VERSION 5.8 ;
BUSBITCHARS "[]" ;
DIVIDERCHAR "/" ;
UNITS
    DATABASE MICRONS 1000 ;
END UNITS

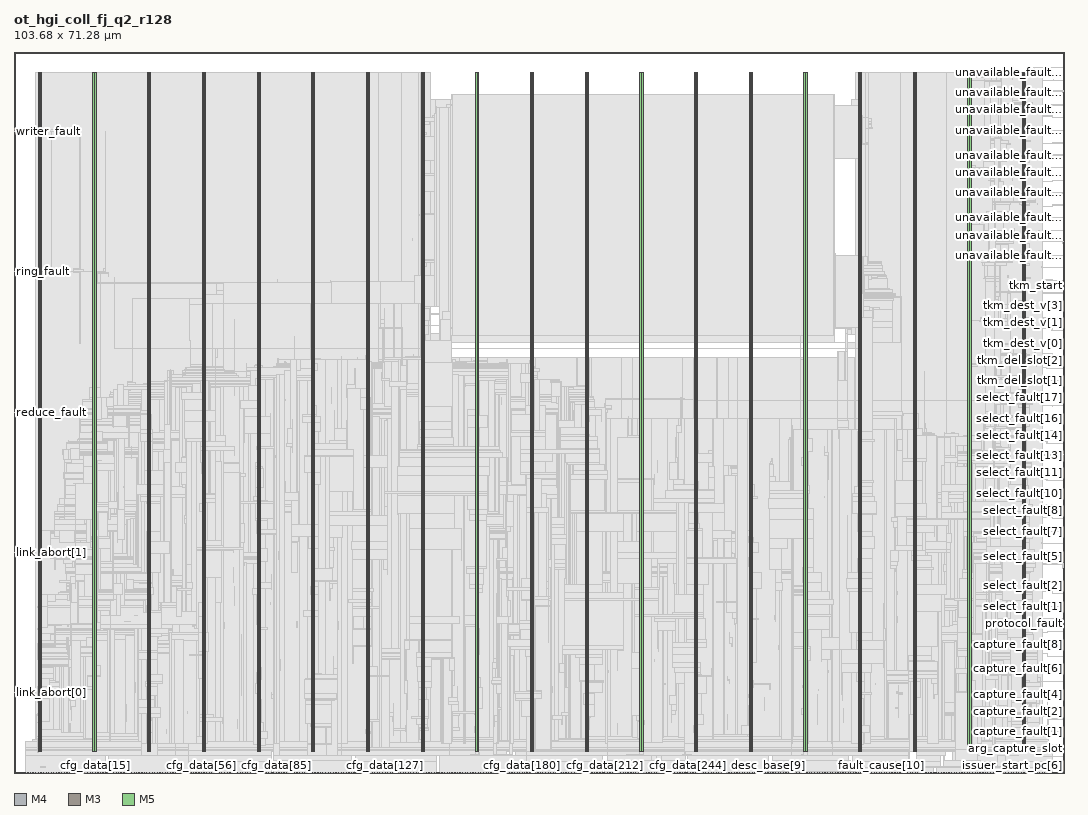
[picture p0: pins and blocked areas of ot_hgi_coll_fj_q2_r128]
MACRO ot_hgi_coll_fj_q2_r128
  FOREIGN ot_hgi_coll_fj_q2_r128 0 0 ;
  CLASS BLOCK ;
  SIZE 103.68 BY 71.28 ;
  PIN arg_capture_slot
    DIRECTION INPUT ;
    USE SIGNAL ;
    PORT
      LAYER M4 ;
        RECT  103.596 1.584 103.68 1.608 ;
    END
  END arg_capture_slot
  PIN capture_fault[0]
    DIRECTION INPUT ;
    USE SIGNAL ;
    PORT
      LAYER M4 ;
        RECT  103.596 2.832 103.68 2.856 ;
    END
  END capture_fault[0]
  PIN capture_fault[1]
    DIRECTION INPUT ;
    USE SIGNAL ;
    PORT
      LAYER M4 ;
        RECT  103.596 4.08 103.68 4.104 ;
    END
  END capture_fault[1]
  PIN capture_fault[2]
    DIRECTION INPUT ;
    USE SIGNAL ;
    PORT
      LAYER M4 ;
        RECT  103.596 5.328 103.68 5.352 ;
    END
  END capture_fault[2]
  PIN capture_fault[3]
    DIRECTION INPUT ;
    USE SIGNAL ;
    PORT
      LAYER M4 ;
        RECT  103.596 6.576 103.68 6.6 ;
    END
  END capture_fault[3]
  PIN capture_fault[4]
    DIRECTION INPUT ;
    USE SIGNAL ;
    PORT
      LAYER M4 ;
        RECT  103.596 7.776 103.68 7.8 ;
    END
  END capture_fault[4]
  PIN capture_fault[5]
    DIRECTION INPUT ;
    USE SIGNAL ;
    PORT
      LAYER M4 ;
        RECT  103.596 9.024 103.68 9.048 ;
    END
  END capture_fault[5]
  PIN capture_fault[6]
    DIRECTION INPUT ;
    USE SIGNAL ;
    PORT
      LAYER M4 ;
        RECT  103.596 10.272 103.68 10.296 ;
    END
  END capture_fault[6]
  PIN capture_fault[7]
    DIRECTION INPUT ;
    USE SIGNAL ;
    PORT
      LAYER M4 ;
        RECT  103.596 11.52 103.68 11.544 ;
    END
  END capture_fault[7]
  PIN capture_fault[8]
    DIRECTION INPUT ;
    USE SIGNAL ;
    PORT
      LAYER M4 ;
        RECT  103.596 12.72 103.68 12.744 ;
    END
  END capture_fault[8]
  PIN cfg_addr[0]
    DIRECTION INPUT ;
    USE SIGNAL ;
    PORT
      LAYER M3 ;
        RECT  1.116 0 1.134 0.038 ;
    END
  END cfg_addr[0]
  PIN cfg_addr[10]
    DIRECTION INPUT ;
    USE SIGNAL ;
    PORT
      LAYER M3 ;
        RECT  3.672 0 3.69 0.038 ;
    END
  END cfg_addr[10]
  PIN cfg_addr[11]
    DIRECTION INPUT ;
    USE SIGNAL ;
    PORT
      LAYER M3 ;
        RECT  3.924 0 3.942 0.038 ;
    END
  END cfg_addr[11]
  PIN cfg_addr[1]
    DIRECTION INPUT ;
    USE SIGNAL ;
    PORT
      LAYER M3 ;
        RECT  1.368 0 1.386 0.038 ;
    END
  END cfg_addr[1]
  PIN cfg_addr[2]
    DIRECTION INPUT ;
    USE SIGNAL ;
    PORT
      LAYER M3 ;
        RECT  1.62 0 1.638 0.038 ;
    END
  END cfg_addr[2]
  PIN cfg_addr[3]
    DIRECTION INPUT ;
    USE SIGNAL ;
    PORT
      LAYER M3 ;
        RECT  1.872 0 1.89 0.038 ;
    END
  END cfg_addr[3]
  PIN cfg_addr[4]
    DIRECTION INPUT ;
    USE SIGNAL ;
    PORT
      LAYER M3 ;
        RECT  2.124 0 2.142 0.038 ;
    END
  END cfg_addr[4]
  PIN cfg_addr[5]
    DIRECTION INPUT ;
    USE SIGNAL ;
    PORT
      LAYER M3 ;
        RECT  2.412 0 2.43 0.038 ;
    END
  END cfg_addr[5]
  PIN cfg_addr[6]
    DIRECTION INPUT ;
    USE SIGNAL ;
    PORT
      LAYER M3 ;
        RECT  2.664 0 2.682 0.038 ;
    END
  END cfg_addr[6]
  PIN cfg_addr[7]
    DIRECTION INPUT ;
    USE SIGNAL ;
    PORT
      LAYER M3 ;
        RECT  2.916 0 2.934 0.038 ;
    END
  END cfg_addr[7]
  PIN cfg_addr[8]
    DIRECTION INPUT ;
    USE SIGNAL ;
    PORT
      LAYER M3 ;
        RECT  3.168 0 3.186 0.038 ;
    END
  END cfg_addr[8]
  PIN cfg_addr[9]
    DIRECTION INPUT ;
    USE SIGNAL ;
    PORT
      LAYER M3 ;
        RECT  3.42 0 3.438 0.038 ;
    END
  END cfg_addr[9]
  PIN cfg_data[0]
    DIRECTION INPUT ;
    USE SIGNAL ;
    PORT
      LAYER M3 ;
        RECT  4.176 0 4.194 0.038 ;
    END
  END cfg_data[0]
  PIN cfg_data[100]
    DIRECTION INPUT ;
    USE SIGNAL ;
    PORT
      LAYER M5 ;
        RECT  29.712 0 29.736 0.084 ;
    END
  END cfg_data[100]
  PIN cfg_data[101]
    DIRECTION INPUT ;
    USE SIGNAL ;
    PORT
      LAYER M5 ;
        RECT  30 0 30.024 0.084 ;
    END
  END cfg_data[101]
  PIN cfg_data[102]
    DIRECTION INPUT ;
    USE SIGNAL ;
    PORT
      LAYER M5 ;
        RECT  30.24 0 30.264 0.084 ;
    END
  END cfg_data[102]
  PIN cfg_data[103]
    DIRECTION INPUT ;
    USE SIGNAL ;
    PORT
      LAYER M5 ;
        RECT  30.48 0 30.504 0.084 ;
    END
  END cfg_data[103]
  PIN cfg_data[104]
    DIRECTION INPUT ;
    USE SIGNAL ;
    PORT
      LAYER M5 ;
        RECT  30.768 0 30.792 0.084 ;
    END
  END cfg_data[104]
  PIN cfg_data[105]
    DIRECTION INPUT ;
    USE SIGNAL ;
    PORT
      LAYER M5 ;
        RECT  31.008 0 31.032 0.084 ;
    END
  END cfg_data[105]
  PIN cfg_data[106]
    DIRECTION INPUT ;
    USE SIGNAL ;
    PORT
      LAYER M5 ;
        RECT  31.248 0 31.272 0.084 ;
    END
  END cfg_data[106]
  PIN cfg_data[107]
    DIRECTION INPUT ;
    USE SIGNAL ;
    PORT
      LAYER M5 ;
        RECT  31.536 0 31.56 0.084 ;
    END
  END cfg_data[107]
  PIN cfg_data[108]
    DIRECTION INPUT ;
    USE SIGNAL ;
    PORT
      LAYER M5 ;
        RECT  31.776 0 31.8 0.084 ;
    END
  END cfg_data[108]
  PIN cfg_data[109]
    DIRECTION INPUT ;
    USE SIGNAL ;
    PORT
      LAYER M5 ;
        RECT  32.016 0 32.04 0.084 ;
    END
  END cfg_data[109]
  PIN cfg_data[10]
    DIRECTION INPUT ;
    USE SIGNAL ;
    PORT
      LAYER M3 ;
        RECT  6.732 0 6.75 0.038 ;
    END
  END cfg_data[10]
  PIN cfg_data[110]
    DIRECTION INPUT ;
    USE SIGNAL ;
    PORT
      LAYER M5 ;
        RECT  32.304 0 32.328 0.084 ;
    END
  END cfg_data[110]
  PIN cfg_data[111]
    DIRECTION INPUT ;
    USE SIGNAL ;
    PORT
      LAYER M5 ;
        RECT  32.544 0 32.568 0.084 ;
    END
  END cfg_data[111]
  PIN cfg_data[112]
    DIRECTION INPUT ;
    USE SIGNAL ;
    PORT
      LAYER M5 ;
        RECT  32.784 0 32.808 0.084 ;
    END
  END cfg_data[112]
  PIN cfg_data[113]
    DIRECTION INPUT ;
    USE SIGNAL ;
    PORT
      LAYER M5 ;
        RECT  33.072 0 33.096 0.084 ;
    END
  END cfg_data[113]
  PIN cfg_data[114]
    DIRECTION INPUT ;
    USE SIGNAL ;
    PORT
      LAYER M5 ;
        RECT  33.312 0 33.336 0.084 ;
    END
  END cfg_data[114]
  PIN cfg_data[115]
    DIRECTION INPUT ;
    USE SIGNAL ;
    PORT
      LAYER M5 ;
        RECT  33.552 0 33.576 0.084 ;
    END
  END cfg_data[115]
  PIN cfg_data[116]
    DIRECTION INPUT ;
    USE SIGNAL ;
    PORT
      LAYER M3 ;
        RECT  33.804 0 33.822 0.038 ;
    END
  END cfg_data[116]
  PIN cfg_data[117]
    DIRECTION INPUT ;
    USE SIGNAL ;
    PORT
      LAYER M3 ;
        RECT  34.092 0 34.11 0.038 ;
    END
  END cfg_data[117]
  PIN cfg_data[118]
    DIRECTION INPUT ;
    USE SIGNAL ;
    PORT
      LAYER M3 ;
        RECT  34.344 0 34.362 0.038 ;
    END
  END cfg_data[118]
  PIN cfg_data[119]
    DIRECTION INPUT ;
    USE SIGNAL ;
    PORT
      LAYER M3 ;
        RECT  34.596 0 34.614 0.038 ;
    END
  END cfg_data[119]
  PIN cfg_data[11]
    DIRECTION INPUT ;
    USE SIGNAL ;
    PORT
      LAYER M3 ;
        RECT  6.984 0 7.002 0.038 ;
    END
  END cfg_data[11]
  PIN cfg_data[120]
    DIRECTION INPUT ;
    USE SIGNAL ;
    PORT
      LAYER M3 ;
        RECT  34.848 0 34.866 0.038 ;
    END
  END cfg_data[120]
  PIN cfg_data[121]
    DIRECTION INPUT ;
    USE SIGNAL ;
    PORT
      LAYER M3 ;
        RECT  35.1 0 35.118 0.038 ;
    END
  END cfg_data[121]
  PIN cfg_data[122]
    DIRECTION INPUT ;
    USE SIGNAL ;
    PORT
      LAYER M3 ;
        RECT  35.352 0 35.37 0.038 ;
    END
  END cfg_data[122]
  PIN cfg_data[123]
    DIRECTION INPUT ;
    USE SIGNAL ;
    PORT
      LAYER M3 ;
        RECT  35.604 0 35.622 0.038 ;
    END
  END cfg_data[123]
  PIN cfg_data[124]
    DIRECTION INPUT ;
    USE SIGNAL ;
    PORT
      LAYER M3 ;
        RECT  35.856 0 35.874 0.038 ;
    END
  END cfg_data[124]
  PIN cfg_data[125]
    DIRECTION INPUT ;
    USE SIGNAL ;
    PORT
      LAYER M3 ;
        RECT  36.108 0 36.126 0.038 ;
    END
  END cfg_data[125]
  PIN cfg_data[126]
    DIRECTION INPUT ;
    USE SIGNAL ;
    PORT
      LAYER M3 ;
        RECT  36.36 0 36.378 0.038 ;
    END
  END cfg_data[126]
  PIN cfg_data[127]
    DIRECTION INPUT ;
    USE SIGNAL ;
    PORT
      LAYER M3 ;
        RECT  36.648 0 36.666 0.038 ;
    END
  END cfg_data[127]
  PIN cfg_data[128]
    DIRECTION INPUT ;
    USE SIGNAL ;
    PORT
      LAYER M3 ;
        RECT  36.9 0 36.918 0.038 ;
    END
  END cfg_data[128]
  PIN cfg_data[129]
    DIRECTION INPUT ;
    USE SIGNAL ;
    PORT
      LAYER M3 ;
        RECT  37.152 0 37.17 0.038 ;
    END
  END cfg_data[129]
  PIN cfg_data[12]
    DIRECTION INPUT ;
    USE SIGNAL ;
    PORT
      LAYER M3 ;
        RECT  7.236 0 7.254 0.038 ;
    END
  END cfg_data[12]
  PIN cfg_data[130]
    DIRECTION INPUT ;
    USE SIGNAL ;
    PORT
      LAYER M3 ;
        RECT  37.404 0 37.422 0.038 ;
    END
  END cfg_data[130]
  PIN cfg_data[131]
    DIRECTION INPUT ;
    USE SIGNAL ;
    PORT
      LAYER M3 ;
        RECT  37.656 0 37.674 0.038 ;
    END
  END cfg_data[131]
  PIN cfg_data[132]
    DIRECTION INPUT ;
    USE SIGNAL ;
    PORT
      LAYER M3 ;
        RECT  37.908 0 37.926 0.038 ;
    END
  END cfg_data[132]
  PIN cfg_data[133]
    DIRECTION INPUT ;
    USE SIGNAL ;
    PORT
      LAYER M3 ;
        RECT  38.16 0 38.178 0.038 ;
    END
  END cfg_data[133]
  PIN cfg_data[134]
    DIRECTION INPUT ;
    USE SIGNAL ;
    PORT
      LAYER M3 ;
        RECT  38.412 0 38.43 0.038 ;
    END
  END cfg_data[134]
  PIN cfg_data[135]
    DIRECTION INPUT ;
    USE SIGNAL ;
    PORT
      LAYER M3 ;
        RECT  38.664 0 38.682 0.038 ;
    END
  END cfg_data[135]
  PIN cfg_data[136]
    DIRECTION INPUT ;
    USE SIGNAL ;
    PORT
      LAYER M3 ;
        RECT  38.916 0 38.934 0.038 ;
    END
  END cfg_data[136]
  PIN cfg_data[137]
    DIRECTION INPUT ;
    USE SIGNAL ;
    PORT
      LAYER M3 ;
        RECT  39.168 0 39.186 0.038 ;
    END
  END cfg_data[137]
  PIN cfg_data[138]
    DIRECTION INPUT ;
    USE SIGNAL ;
    PORT
      LAYER M3 ;
        RECT  39.456 0 39.474 0.038 ;
    END
  END cfg_data[138]
  PIN cfg_data[139]
    DIRECTION INPUT ;
    USE SIGNAL ;
    PORT
      LAYER M3 ;
        RECT  39.708 0 39.726 0.038 ;
    END
  END cfg_data[139]
  PIN cfg_data[13]
    DIRECTION INPUT ;
    USE SIGNAL ;
    PORT
      LAYER M3 ;
        RECT  7.524 0 7.542 0.038 ;
    END
  END cfg_data[13]
  PIN cfg_data[140]
    DIRECTION INPUT ;
    USE SIGNAL ;
    PORT
      LAYER M3 ;
        RECT  39.96 0 39.978 0.038 ;
    END
  END cfg_data[140]
  PIN cfg_data[141]
    DIRECTION INPUT ;
    USE SIGNAL ;
    PORT
      LAYER M3 ;
        RECT  40.212 0 40.23 0.038 ;
    END
  END cfg_data[141]
  PIN cfg_data[142]
    DIRECTION INPUT ;
    USE SIGNAL ;
    PORT
      LAYER M3 ;
        RECT  40.464 0 40.482 0.038 ;
    END
  END cfg_data[142]
  PIN cfg_data[143]
    DIRECTION INPUT ;
    USE SIGNAL ;
    PORT
      LAYER M3 ;
        RECT  40.716 0 40.734 0.038 ;
    END
  END cfg_data[143]
  PIN cfg_data[144]
    DIRECTION INPUT ;
    USE SIGNAL ;
    PORT
      LAYER M3 ;
        RECT  40.968 0 40.986 0.038 ;
    END
  END cfg_data[144]
  PIN cfg_data[145]
    DIRECTION INPUT ;
    USE SIGNAL ;
    PORT
      LAYER M3 ;
        RECT  41.22 0 41.238 0.038 ;
    END
  END cfg_data[145]
  PIN cfg_data[146]
    DIRECTION INPUT ;
    USE SIGNAL ;
    PORT
      LAYER M3 ;
        RECT  41.472 0 41.49 0.038 ;
    END
  END cfg_data[146]
  PIN cfg_data[147]
    DIRECTION INPUT ;
    USE SIGNAL ;
    PORT
      LAYER M3 ;
        RECT  41.724 0 41.742 0.038 ;
    END
  END cfg_data[147]
  PIN cfg_data[148]
    DIRECTION INPUT ;
    USE SIGNAL ;
    PORT
      LAYER M5 ;
        RECT  42 0 42.024 0.084 ;
    END
  END cfg_data[148]
  PIN cfg_data[149]
    DIRECTION INPUT ;
    USE SIGNAL ;
    PORT
      LAYER M5 ;
        RECT  42.24 0 42.264 0.084 ;
    END
  END cfg_data[149]
  PIN cfg_data[14]
    DIRECTION INPUT ;
    USE SIGNAL ;
    PORT
      LAYER M3 ;
        RECT  7.776 0 7.794 0.038 ;
    END
  END cfg_data[14]
  PIN cfg_data[150]
    DIRECTION INPUT ;
    USE SIGNAL ;
    PORT
      LAYER M5 ;
        RECT  42.48 0 42.504 0.084 ;
    END
  END cfg_data[150]
  PIN cfg_data[151]
    DIRECTION INPUT ;
    USE SIGNAL ;
    PORT
      LAYER M5 ;
        RECT  42.768 0 42.792 0.084 ;
    END
  END cfg_data[151]
  PIN cfg_data[152]
    DIRECTION INPUT ;
    USE SIGNAL ;
    PORT
      LAYER M5 ;
        RECT  43.008 0 43.032 0.084 ;
    END
  END cfg_data[152]
  PIN cfg_data[153]
    DIRECTION INPUT ;
    USE SIGNAL ;
    PORT
      LAYER M5 ;
        RECT  43.248 0 43.272 0.084 ;
    END
  END cfg_data[153]
  PIN cfg_data[154]
    DIRECTION INPUT ;
    USE SIGNAL ;
    PORT
      LAYER M5 ;
        RECT  43.536 0 43.56 0.084 ;
    END
  END cfg_data[154]
  PIN cfg_data[155]
    DIRECTION INPUT ;
    USE SIGNAL ;
    PORT
      LAYER M5 ;
        RECT  43.776 0 43.8 0.084 ;
    END
  END cfg_data[155]
  PIN cfg_data[156]
    DIRECTION INPUT ;
    USE SIGNAL ;
    PORT
      LAYER M5 ;
        RECT  44.016 0 44.04 0.084 ;
    END
  END cfg_data[156]
  PIN cfg_data[157]
    DIRECTION INPUT ;
    USE SIGNAL ;
    PORT
      LAYER M5 ;
        RECT  44.304 0 44.328 0.084 ;
    END
  END cfg_data[157]
  PIN cfg_data[158]
    DIRECTION INPUT ;
    USE SIGNAL ;
    PORT
      LAYER M5 ;
        RECT  44.544 0 44.568 0.084 ;
    END
  END cfg_data[158]
  PIN cfg_data[159]
    DIRECTION INPUT ;
    USE SIGNAL ;
    PORT
      LAYER M5 ;
        RECT  44.784 0 44.808 0.084 ;
    END
  END cfg_data[159]
  PIN cfg_data[15]
    DIRECTION INPUT ;
    USE SIGNAL ;
    PORT
      LAYER M3 ;
        RECT  8.028 0 8.046 0.038 ;
    END
  END cfg_data[15]
  PIN cfg_data[160]
    DIRECTION INPUT ;
    USE SIGNAL ;
    PORT
      LAYER M5 ;
        RECT  45.072 0 45.096 0.084 ;
    END
  END cfg_data[160]
  PIN cfg_data[161]
    DIRECTION INPUT ;
    USE SIGNAL ;
    PORT
      LAYER M5 ;
        RECT  45.312 0 45.336 0.084 ;
    END
  END cfg_data[161]
  PIN cfg_data[162]
    DIRECTION INPUT ;
    USE SIGNAL ;
    PORT
      LAYER M5 ;
        RECT  45.552 0 45.576 0.084 ;
    END
  END cfg_data[162]
  PIN cfg_data[163]
    DIRECTION INPUT ;
    USE SIGNAL ;
    PORT
      LAYER M5 ;
        RECT  45.84 0 45.864 0.084 ;
    END
  END cfg_data[163]
  PIN cfg_data[164]
    DIRECTION INPUT ;
    USE SIGNAL ;
    PORT
      LAYER M5 ;
        RECT  46.08 0 46.104 0.084 ;
    END
  END cfg_data[164]
  PIN cfg_data[165]
    DIRECTION INPUT ;
    USE SIGNAL ;
    PORT
      LAYER M5 ;
        RECT  46.32 0 46.344 0.084 ;
    END
  END cfg_data[165]
  PIN cfg_data[166]
    DIRECTION INPUT ;
    USE SIGNAL ;
    PORT
      LAYER M5 ;
        RECT  46.608 0 46.632 0.084 ;
    END
  END cfg_data[166]
  PIN cfg_data[167]
    DIRECTION INPUT ;
    USE SIGNAL ;
    PORT
      LAYER M5 ;
        RECT  46.848 0 46.872 0.084 ;
    END
  END cfg_data[167]
  PIN cfg_data[168]
    DIRECTION INPUT ;
    USE SIGNAL ;
    PORT
      LAYER M5 ;
        RECT  47.088 0 47.112 0.084 ;
    END
  END cfg_data[168]
  PIN cfg_data[169]
    DIRECTION INPUT ;
    USE SIGNAL ;
    PORT
      LAYER M5 ;
        RECT  47.376 0 47.4 0.084 ;
    END
  END cfg_data[169]
  PIN cfg_data[16]
    DIRECTION INPUT ;
    USE SIGNAL ;
    PORT
      LAYER M3 ;
        RECT  8.28 0 8.298 0.038 ;
    END
  END cfg_data[16]
  PIN cfg_data[170]
    DIRECTION INPUT ;
    USE SIGNAL ;
    PORT
      LAYER M5 ;
        RECT  47.616 0 47.64 0.084 ;
    END
  END cfg_data[170]
  PIN cfg_data[171]
    DIRECTION INPUT ;
    USE SIGNAL ;
    PORT
      LAYER M5 ;
        RECT  47.856 0 47.88 0.084 ;
    END
  END cfg_data[171]
  PIN cfg_data[172]
    DIRECTION INPUT ;
    USE SIGNAL ;
    PORT
      LAYER M5 ;
        RECT  48.144 0 48.168 0.084 ;
    END
  END cfg_data[172]
  PIN cfg_data[173]
    DIRECTION INPUT ;
    USE SIGNAL ;
    PORT
      LAYER M5 ;
        RECT  48.384 0 48.408 0.084 ;
    END
  END cfg_data[173]
  PIN cfg_data[174]
    DIRECTION INPUT ;
    USE SIGNAL ;
    PORT
      LAYER M5 ;
        RECT  48.624 0 48.648 0.084 ;
    END
  END cfg_data[174]
  PIN cfg_data[175]
    DIRECTION INPUT ;
    USE SIGNAL ;
    PORT
      LAYER M5 ;
        RECT  48.912 0 48.936 0.084 ;
    END
  END cfg_data[175]
  PIN cfg_data[176]
    DIRECTION INPUT ;
    USE SIGNAL ;
    PORT
      LAYER M5 ;
        RECT  49.152 0 49.176 0.084 ;
    END
  END cfg_data[176]
  PIN cfg_data[177]
    DIRECTION INPUT ;
    USE SIGNAL ;
    PORT
      LAYER M5 ;
        RECT  49.392 0 49.416 0.084 ;
    END
  END cfg_data[177]
  PIN cfg_data[178]
    DIRECTION INPUT ;
    USE SIGNAL ;
    PORT
      LAYER M5 ;
        RECT  49.68 0 49.704 0.084 ;
    END
  END cfg_data[178]
  PIN cfg_data[179]
    DIRECTION INPUT ;
    USE SIGNAL ;
    PORT
      LAYER M5 ;
        RECT  49.92 0 49.944 0.084 ;
    END
  END cfg_data[179]
  PIN cfg_data[17]
    DIRECTION INPUT ;
    USE SIGNAL ;
    PORT
      LAYER M3 ;
        RECT  8.532 0 8.55 0.038 ;
    END
  END cfg_data[17]
  PIN cfg_data[180]
    DIRECTION INPUT ;
    USE SIGNAL ;
    PORT
      LAYER M3 ;
        RECT  50.184 0 50.202 0.038 ;
    END
  END cfg_data[180]
  PIN cfg_data[181]
    DIRECTION INPUT ;
    USE SIGNAL ;
    PORT
      LAYER M3 ;
        RECT  50.436 0 50.454 0.038 ;
    END
  END cfg_data[181]
  PIN cfg_data[182]
    DIRECTION INPUT ;
    USE SIGNAL ;
    PORT
      LAYER M3 ;
        RECT  50.688 0 50.706 0.038 ;
    END
  END cfg_data[182]
  PIN cfg_data[183]
    DIRECTION INPUT ;
    USE SIGNAL ;
    PORT
      LAYER M3 ;
        RECT  50.94 0 50.958 0.038 ;
    END
  END cfg_data[183]
  PIN cfg_data[184]
    DIRECTION INPUT ;
    USE SIGNAL ;
    PORT
      LAYER M3 ;
        RECT  51.192 0 51.21 0.038 ;
    END
  END cfg_data[184]
  PIN cfg_data[185]
    DIRECTION INPUT ;
    USE SIGNAL ;
    PORT
      LAYER M3 ;
        RECT  51.444 0 51.462 0.038 ;
    END
  END cfg_data[185]
  PIN cfg_data[186]
    DIRECTION INPUT ;
    USE SIGNAL ;
    PORT
      LAYER M3 ;
        RECT  51.696 0 51.714 0.038 ;
    END
  END cfg_data[186]
  PIN cfg_data[187]
    DIRECTION INPUT ;
    USE SIGNAL ;
    PORT
      LAYER M3 ;
        RECT  51.948 0 51.966 0.038 ;
    END
  END cfg_data[187]
  PIN cfg_data[188]
    DIRECTION INPUT ;
    USE SIGNAL ;
    PORT
      LAYER M3 ;
        RECT  52.2 0 52.218 0.038 ;
    END
  END cfg_data[188]
  PIN cfg_data[189]
    DIRECTION INPUT ;
    USE SIGNAL ;
    PORT
      LAYER M3 ;
        RECT  52.488 0 52.506 0.038 ;
    END
  END cfg_data[189]
  PIN cfg_data[18]
    DIRECTION INPUT ;
    USE SIGNAL ;
    PORT
      LAYER M3 ;
        RECT  8.784 0 8.802 0.038 ;
    END
  END cfg_data[18]
  PIN cfg_data[190]
    DIRECTION INPUT ;
    USE SIGNAL ;
    PORT
      LAYER M3 ;
        RECT  52.74 0 52.758 0.038 ;
    END
  END cfg_data[190]
  PIN cfg_data[191]
    DIRECTION INPUT ;
    USE SIGNAL ;
    PORT
      LAYER M3 ;
        RECT  52.992 0 53.01 0.038 ;
    END
  END cfg_data[191]
  PIN cfg_data[192]
    DIRECTION INPUT ;
    USE SIGNAL ;
    PORT
      LAYER M3 ;
        RECT  53.244 0 53.262 0.038 ;
    END
  END cfg_data[192]
  PIN cfg_data[193]
    DIRECTION INPUT ;
    USE SIGNAL ;
    PORT
      LAYER M3 ;
        RECT  53.496 0 53.514 0.038 ;
    END
  END cfg_data[193]
  PIN cfg_data[194]
    DIRECTION INPUT ;
    USE SIGNAL ;
    PORT
      LAYER M3 ;
        RECT  53.748 0 53.766 0.038 ;
    END
  END cfg_data[194]
  PIN cfg_data[195]
    DIRECTION INPUT ;
    USE SIGNAL ;
    PORT
      LAYER M3 ;
        RECT  54 0 54.018 0.038 ;
    END
  END cfg_data[195]
  PIN cfg_data[196]
    DIRECTION INPUT ;
    USE SIGNAL ;
    PORT
      LAYER M3 ;
        RECT  54.252 0 54.27 0.038 ;
    END
  END cfg_data[196]
  PIN cfg_data[197]
    DIRECTION INPUT ;
    USE SIGNAL ;
    PORT
      LAYER M3 ;
        RECT  54.504 0 54.522 0.038 ;
    END
  END cfg_data[197]
  PIN cfg_data[198]
    DIRECTION INPUT ;
    USE SIGNAL ;
    PORT
      LAYER M3 ;
        RECT  54.756 0 54.774 0.038 ;
    END
  END cfg_data[198]
  PIN cfg_data[199]
    DIRECTION INPUT ;
    USE SIGNAL ;
    PORT
      LAYER M3 ;
        RECT  55.008 0 55.026 0.038 ;
    END
  END cfg_data[199]
  PIN cfg_data[19]
    DIRECTION INPUT ;
    USE SIGNAL ;
    PORT
      LAYER M3 ;
        RECT  9.036 0 9.054 0.038 ;
    END
  END cfg_data[19]
  PIN cfg_data[1]
    DIRECTION INPUT ;
    USE SIGNAL ;
    PORT
      LAYER M3 ;
        RECT  4.428 0 4.446 0.038 ;
    END
  END cfg_data[1]
  PIN cfg_data[200]
    DIRECTION INPUT ;
    USE SIGNAL ;
    PORT
      LAYER M3 ;
        RECT  55.296 0 55.314 0.038 ;
    END
  END cfg_data[200]
  PIN cfg_data[201]
    DIRECTION INPUT ;
    USE SIGNAL ;
    PORT
      LAYER M3 ;
        RECT  55.548 0 55.566 0.038 ;
    END
  END cfg_data[201]
  PIN cfg_data[202]
    DIRECTION INPUT ;
    USE SIGNAL ;
    PORT
      LAYER M3 ;
        RECT  55.8 0 55.818 0.038 ;
    END
  END cfg_data[202]
  PIN cfg_data[203]
    DIRECTION INPUT ;
    USE SIGNAL ;
    PORT
      LAYER M3 ;
        RECT  56.052 0 56.07 0.038 ;
    END
  END cfg_data[203]
  PIN cfg_data[204]
    DIRECTION INPUT ;
    USE SIGNAL ;
    PORT
      LAYER M3 ;
        RECT  56.304 0 56.322 0.038 ;
    END
  END cfg_data[204]
  PIN cfg_data[205]
    DIRECTION INPUT ;
    USE SIGNAL ;
    PORT
      LAYER M3 ;
        RECT  56.556 0 56.574 0.038 ;
    END
  END cfg_data[205]
  PIN cfg_data[206]
    DIRECTION INPUT ;
    USE SIGNAL ;
    PORT
      LAYER M3 ;
        RECT  56.808 0 56.826 0.038 ;
    END
  END cfg_data[206]
  PIN cfg_data[207]
    DIRECTION INPUT ;
    USE SIGNAL ;
    PORT
      LAYER M3 ;
        RECT  57.06 0 57.078 0.038 ;
    END
  END cfg_data[207]
  PIN cfg_data[208]
    DIRECTION INPUT ;
    USE SIGNAL ;
    PORT
      LAYER M3 ;
        RECT  57.312 0 57.33 0.038 ;
    END
  END cfg_data[208]
  PIN cfg_data[209]
    DIRECTION INPUT ;
    USE SIGNAL ;
    PORT
      LAYER M3 ;
        RECT  57.564 0 57.582 0.038 ;
    END
  END cfg_data[209]
  PIN cfg_data[20]
    DIRECTION INPUT ;
    USE SIGNAL ;
    PORT
      LAYER M5 ;
        RECT  9.312 0 9.336 0.084 ;
    END
  END cfg_data[20]
  PIN cfg_data[210]
    DIRECTION INPUT ;
    USE SIGNAL ;
    PORT
      LAYER M3 ;
        RECT  57.852 0 57.87 0.038 ;
    END
  END cfg_data[210]
  PIN cfg_data[211]
    DIRECTION INPUT ;
    USE SIGNAL ;
    PORT
      LAYER M3 ;
        RECT  58.104 0 58.122 0.038 ;
    END
  END cfg_data[211]
  PIN cfg_data[212]
    DIRECTION INPUT ;
    USE SIGNAL ;
    PORT
      LAYER M5 ;
        RECT  58.32 0 58.344 0.084 ;
    END
  END cfg_data[212]
  PIN cfg_data[213]
    DIRECTION INPUT ;
    USE SIGNAL ;
    PORT
      LAYER M5 ;
        RECT  58.608 0 58.632 0.084 ;
    END
  END cfg_data[213]
  PIN cfg_data[214]
    DIRECTION INPUT ;
    USE SIGNAL ;
    PORT
      LAYER M5 ;
        RECT  58.848 0 58.872 0.084 ;
    END
  END cfg_data[214]
  PIN cfg_data[215]
    DIRECTION INPUT ;
    USE SIGNAL ;
    PORT
      LAYER M5 ;
        RECT  59.088 0 59.112 0.084 ;
    END
  END cfg_data[215]
  PIN cfg_data[216]
    DIRECTION INPUT ;
    USE SIGNAL ;
    PORT
      LAYER M5 ;
        RECT  59.376 0 59.4 0.084 ;
    END
  END cfg_data[216]
  PIN cfg_data[217]
    DIRECTION INPUT ;
    USE SIGNAL ;
    PORT
      LAYER M5 ;
        RECT  59.616 0 59.64 0.084 ;
    END
  END cfg_data[217]
  PIN cfg_data[218]
    DIRECTION INPUT ;
    USE SIGNAL ;
    PORT
      LAYER M5 ;
        RECT  59.856 0 59.88 0.084 ;
    END
  END cfg_data[218]
  PIN cfg_data[219]
    DIRECTION INPUT ;
    USE SIGNAL ;
    PORT
      LAYER M5 ;
        RECT  60.144 0 60.168 0.084 ;
    END
  END cfg_data[219]
  PIN cfg_data[21]
    DIRECTION INPUT ;
    USE SIGNAL ;
    PORT
      LAYER M5 ;
        RECT  9.552 0 9.576 0.084 ;
    END
  END cfg_data[21]
  PIN cfg_data[220]
    DIRECTION INPUT ;
    USE SIGNAL ;
    PORT
      LAYER M5 ;
        RECT  60.384 0 60.408 0.084 ;
    END
  END cfg_data[220]
  PIN cfg_data[221]
    DIRECTION INPUT ;
    USE SIGNAL ;
    PORT
      LAYER M5 ;
        RECT  60.624 0 60.648 0.084 ;
    END
  END cfg_data[221]
  PIN cfg_data[222]
    DIRECTION INPUT ;
    USE SIGNAL ;
    PORT
      LAYER M5 ;
        RECT  60.912 0 60.936 0.084 ;
    END
  END cfg_data[222]
  PIN cfg_data[223]
    DIRECTION INPUT ;
    USE SIGNAL ;
    PORT
      LAYER M5 ;
        RECT  61.152 0 61.176 0.084 ;
    END
  END cfg_data[223]
  PIN cfg_data[224]
    DIRECTION INPUT ;
    USE SIGNAL ;
    PORT
      LAYER M5 ;
        RECT  61.392 0 61.416 0.084 ;
    END
  END cfg_data[224]
  PIN cfg_data[225]
    DIRECTION INPUT ;
    USE SIGNAL ;
    PORT
      LAYER M5 ;
        RECT  61.68 0 61.704 0.084 ;
    END
  END cfg_data[225]
  PIN cfg_data[226]
    DIRECTION INPUT ;
    USE SIGNAL ;
    PORT
      LAYER M5 ;
        RECT  61.92 0 61.944 0.084 ;
    END
  END cfg_data[226]
  PIN cfg_data[227]
    DIRECTION INPUT ;
    USE SIGNAL ;
    PORT
      LAYER M5 ;
        RECT  62.16 0 62.184 0.084 ;
    END
  END cfg_data[227]
  PIN cfg_data[228]
    DIRECTION INPUT ;
    USE SIGNAL ;
    PORT
      LAYER M5 ;
        RECT  62.448 0 62.472 0.084 ;
    END
  END cfg_data[228]
  PIN cfg_data[229]
    DIRECTION INPUT ;
    USE SIGNAL ;
    PORT
      LAYER M5 ;
        RECT  62.688 0 62.712 0.084 ;
    END
  END cfg_data[229]
  PIN cfg_data[22]
    DIRECTION INPUT ;
    USE SIGNAL ;
    PORT
      LAYER M5 ;
        RECT  9.792 0 9.816 0.084 ;
    END
  END cfg_data[22]
  PIN cfg_data[230]
    DIRECTION INPUT ;
    USE SIGNAL ;
    PORT
      LAYER M5 ;
        RECT  62.928 0 62.952 0.084 ;
    END
  END cfg_data[230]
  PIN cfg_data[231]
    DIRECTION INPUT ;
    USE SIGNAL ;
    PORT
      LAYER M5 ;
        RECT  63.216 0 63.24 0.084 ;
    END
  END cfg_data[231]
  PIN cfg_data[232]
    DIRECTION INPUT ;
    USE SIGNAL ;
    PORT
      LAYER M5 ;
        RECT  63.456 0 63.48 0.084 ;
    END
  END cfg_data[232]
  PIN cfg_data[233]
    DIRECTION INPUT ;
    USE SIGNAL ;
    PORT
      LAYER M5 ;
        RECT  63.696 0 63.72 0.084 ;
    END
  END cfg_data[233]
  PIN cfg_data[234]
    DIRECTION INPUT ;
    USE SIGNAL ;
    PORT
      LAYER M5 ;
        RECT  63.984 0 64.008 0.084 ;
    END
  END cfg_data[234]
  PIN cfg_data[235]
    DIRECTION INPUT ;
    USE SIGNAL ;
    PORT
      LAYER M5 ;
        RECT  64.224 0 64.248 0.084 ;
    END
  END cfg_data[235]
  PIN cfg_data[236]
    DIRECTION INPUT ;
    USE SIGNAL ;
    PORT
      LAYER M5 ;
        RECT  64.464 0 64.488 0.084 ;
    END
  END cfg_data[236]
  PIN cfg_data[237]
    DIRECTION INPUT ;
    USE SIGNAL ;
    PORT
      LAYER M5 ;
        RECT  64.752 0 64.776 0.084 ;
    END
  END cfg_data[237]
  PIN cfg_data[238]
    DIRECTION INPUT ;
    USE SIGNAL ;
    PORT
      LAYER M5 ;
        RECT  64.992 0 65.016 0.084 ;
    END
  END cfg_data[238]
  PIN cfg_data[239]
    DIRECTION INPUT ;
    USE SIGNAL ;
    PORT
      LAYER M5 ;
        RECT  65.232 0 65.256 0.084 ;
    END
  END cfg_data[239]
  PIN cfg_data[23]
    DIRECTION INPUT ;
    USE SIGNAL ;
    PORT
      LAYER M5 ;
        RECT  10.08 0 10.104 0.084 ;
    END
  END cfg_data[23]
  PIN cfg_data[240]
    DIRECTION INPUT ;
    USE SIGNAL ;
    PORT
      LAYER M5 ;
        RECT  65.52 0 65.544 0.084 ;
    END
  END cfg_data[240]
  PIN cfg_data[241]
    DIRECTION INPUT ;
    USE SIGNAL ;
    PORT
      LAYER M5 ;
        RECT  65.76 0 65.784 0.084 ;
    END
  END cfg_data[241]
  PIN cfg_data[242]
    DIRECTION INPUT ;
    USE SIGNAL ;
    PORT
      LAYER M5 ;
        RECT  66 0 66.024 0.084 ;
    END
  END cfg_data[242]
  PIN cfg_data[243]
    DIRECTION INPUT ;
    USE SIGNAL ;
    PORT
      LAYER M5 ;
        RECT  66.24 0 66.264 0.084 ;
    END
  END cfg_data[243]
  PIN cfg_data[244]
    DIRECTION INPUT ;
    USE SIGNAL ;
    PORT
      LAYER M3 ;
        RECT  66.528 0 66.546 0.038 ;
    END
  END cfg_data[244]
  PIN cfg_data[245]
    DIRECTION INPUT ;
    USE SIGNAL ;
    PORT
      LAYER M3 ;
        RECT  66.78 0 66.798 0.038 ;
    END
  END cfg_data[245]
  PIN cfg_data[246]
    DIRECTION INPUT ;
    USE SIGNAL ;
    PORT
      LAYER M3 ;
        RECT  67.032 0 67.05 0.038 ;
    END
  END cfg_data[246]
  PIN cfg_data[247]
    DIRECTION INPUT ;
    USE SIGNAL ;
    PORT
      LAYER M3 ;
        RECT  67.284 0 67.302 0.038 ;
    END
  END cfg_data[247]
  PIN cfg_data[248]
    DIRECTION INPUT ;
    USE SIGNAL ;
    PORT
      LAYER M3 ;
        RECT  67.536 0 67.554 0.038 ;
    END
  END cfg_data[248]
  PIN cfg_data[249]
    DIRECTION INPUT ;
    USE SIGNAL ;
    PORT
      LAYER M3 ;
        RECT  67.788 0 67.806 0.038 ;
    END
  END cfg_data[249]
  PIN cfg_data[24]
    DIRECTION INPUT ;
    USE SIGNAL ;
    PORT
      LAYER M5 ;
        RECT  10.32 0 10.344 0.084 ;
    END
  END cfg_data[24]
  PIN cfg_data[250]
    DIRECTION INPUT ;
    USE SIGNAL ;
    PORT
      LAYER M3 ;
        RECT  68.04 0 68.058 0.038 ;
    END
  END cfg_data[250]
  PIN cfg_data[251]
    DIRECTION INPUT ;
    USE SIGNAL ;
    PORT
      LAYER M3 ;
        RECT  68.292 0 68.31 0.038 ;
    END
  END cfg_data[251]
  PIN cfg_data[252]
    DIRECTION INPUT ;
    USE SIGNAL ;
    PORT
      LAYER M3 ;
        RECT  68.58 0 68.598 0.038 ;
    END
  END cfg_data[252]
  PIN cfg_data[253]
    DIRECTION INPUT ;
    USE SIGNAL ;
    PORT
      LAYER M3 ;
        RECT  68.832 0 68.85 0.038 ;
    END
  END cfg_data[253]
  PIN cfg_data[254]
    DIRECTION INPUT ;
    USE SIGNAL ;
    PORT
      LAYER M3 ;
        RECT  69.084 0 69.102 0.038 ;
    END
  END cfg_data[254]
  PIN cfg_data[255]
    DIRECTION INPUT ;
    USE SIGNAL ;
    PORT
      LAYER M3 ;
        RECT  69.336 0 69.354 0.038 ;
    END
  END cfg_data[255]
  PIN cfg_data[25]
    DIRECTION INPUT ;
    USE SIGNAL ;
    PORT
      LAYER M5 ;
        RECT  10.56 0 10.584 0.084 ;
    END
  END cfg_data[25]
  PIN cfg_data[26]
    DIRECTION INPUT ;
    USE SIGNAL ;
    PORT
      LAYER M5 ;
        RECT  10.848 0 10.872 0.084 ;
    END
  END cfg_data[26]
  PIN cfg_data[27]
    DIRECTION INPUT ;
    USE SIGNAL ;
    PORT
      LAYER M5 ;
        RECT  11.088 0 11.112 0.084 ;
    END
  END cfg_data[27]
  PIN cfg_data[28]
    DIRECTION INPUT ;
    USE SIGNAL ;
    PORT
      LAYER M5 ;
        RECT  11.328 0 11.352 0.084 ;
    END
  END cfg_data[28]
  PIN cfg_data[29]
    DIRECTION INPUT ;
    USE SIGNAL ;
    PORT
      LAYER M5 ;
        RECT  11.568 0 11.592 0.084 ;
    END
  END cfg_data[29]
  PIN cfg_data[2]
    DIRECTION INPUT ;
    USE SIGNAL ;
    PORT
      LAYER M3 ;
        RECT  4.68 0 4.698 0.038 ;
    END
  END cfg_data[2]
  PIN cfg_data[30]
    DIRECTION INPUT ;
    USE SIGNAL ;
    PORT
      LAYER M5 ;
        RECT  11.856 0 11.88 0.084 ;
    END
  END cfg_data[30]
  PIN cfg_data[31]
    DIRECTION INPUT ;
    USE SIGNAL ;
    PORT
      LAYER M5 ;
        RECT  12.096 0 12.12 0.084 ;
    END
  END cfg_data[31]
  PIN cfg_data[32]
    DIRECTION INPUT ;
    USE SIGNAL ;
    PORT
      LAYER M5 ;
        RECT  12.336 0 12.36 0.084 ;
    END
  END cfg_data[32]
  PIN cfg_data[33]
    DIRECTION INPUT ;
    USE SIGNAL ;
    PORT
      LAYER M5 ;
        RECT  12.624 0 12.648 0.084 ;
    END
  END cfg_data[33]
  PIN cfg_data[34]
    DIRECTION INPUT ;
    USE SIGNAL ;
    PORT
      LAYER M5 ;
        RECT  12.864 0 12.888 0.084 ;
    END
  END cfg_data[34]
  PIN cfg_data[35]
    DIRECTION INPUT ;
    USE SIGNAL ;
    PORT
      LAYER M5 ;
        RECT  13.104 0 13.128 0.084 ;
    END
  END cfg_data[35]
  PIN cfg_data[36]
    DIRECTION INPUT ;
    USE SIGNAL ;
    PORT
      LAYER M5 ;
        RECT  13.392 0 13.416 0.084 ;
    END
  END cfg_data[36]
  PIN cfg_data[37]
    DIRECTION INPUT ;
    USE SIGNAL ;
    PORT
      LAYER M5 ;
        RECT  13.632 0 13.656 0.084 ;
    END
  END cfg_data[37]
  PIN cfg_data[38]
    DIRECTION INPUT ;
    USE SIGNAL ;
    PORT
      LAYER M5 ;
        RECT  13.872 0 13.896 0.084 ;
    END
  END cfg_data[38]
  PIN cfg_data[39]
    DIRECTION INPUT ;
    USE SIGNAL ;
    PORT
      LAYER M5 ;
        RECT  14.16 0 14.184 0.084 ;
    END
  END cfg_data[39]
  PIN cfg_data[3]
    DIRECTION INPUT ;
    USE SIGNAL ;
    PORT
      LAYER M3 ;
        RECT  4.968 0 4.986 0.038 ;
    END
  END cfg_data[3]
  PIN cfg_data[40]
    DIRECTION INPUT ;
    USE SIGNAL ;
    PORT
      LAYER M5 ;
        RECT  14.4 0 14.424 0.084 ;
    END
  END cfg_data[40]
  PIN cfg_data[41]
    DIRECTION INPUT ;
    USE SIGNAL ;
    PORT
      LAYER M5 ;
        RECT  14.64 0 14.664 0.084 ;
    END
  END cfg_data[41]
  PIN cfg_data[42]
    DIRECTION INPUT ;
    USE SIGNAL ;
    PORT
      LAYER M5 ;
        RECT  14.928 0 14.952 0.084 ;
    END
  END cfg_data[42]
  PIN cfg_data[43]
    DIRECTION INPUT ;
    USE SIGNAL ;
    PORT
      LAYER M5 ;
        RECT  15.168 0 15.192 0.084 ;
    END
  END cfg_data[43]
  PIN cfg_data[44]
    DIRECTION INPUT ;
    USE SIGNAL ;
    PORT
      LAYER M5 ;
        RECT  15.408 0 15.432 0.084 ;
    END
  END cfg_data[44]
  PIN cfg_data[45]
    DIRECTION INPUT ;
    USE SIGNAL ;
    PORT
      LAYER M5 ;
        RECT  15.696 0 15.72 0.084 ;
    END
  END cfg_data[45]
  PIN cfg_data[46]
    DIRECTION INPUT ;
    USE SIGNAL ;
    PORT
      LAYER M5 ;
        RECT  15.936 0 15.96 0.084 ;
    END
  END cfg_data[46]
  PIN cfg_data[47]
    DIRECTION INPUT ;
    USE SIGNAL ;
    PORT
      LAYER M5 ;
        RECT  16.176 0 16.2 0.084 ;
    END
  END cfg_data[47]
  PIN cfg_data[48]
    DIRECTION INPUT ;
    USE SIGNAL ;
    PORT
      LAYER M5 ;
        RECT  16.464 0 16.488 0.084 ;
    END
  END cfg_data[48]
  PIN cfg_data[49]
    DIRECTION INPUT ;
    USE SIGNAL ;
    PORT
      LAYER M5 ;
        RECT  16.704 0 16.728 0.084 ;
    END
  END cfg_data[49]
  PIN cfg_data[4]
    DIRECTION INPUT ;
    USE SIGNAL ;
    PORT
      LAYER M3 ;
        RECT  5.22 0 5.238 0.038 ;
    END
  END cfg_data[4]
  PIN cfg_data[50]
    DIRECTION INPUT ;
    USE SIGNAL ;
    PORT
      LAYER M5 ;
        RECT  16.944 0 16.968 0.084 ;
    END
  END cfg_data[50]
  PIN cfg_data[51]
    DIRECTION INPUT ;
    USE SIGNAL ;
    PORT
      LAYER M5 ;
        RECT  17.232 0 17.256 0.084 ;
    END
  END cfg_data[51]
  PIN cfg_data[52]
    DIRECTION INPUT ;
    USE SIGNAL ;
    PORT
      LAYER M3 ;
        RECT  17.46 0 17.478 0.038 ;
    END
  END cfg_data[52]
  PIN cfg_data[53]
    DIRECTION INPUT ;
    USE SIGNAL ;
    PORT
      LAYER M3 ;
        RECT  17.712 0 17.73 0.038 ;
    END
  END cfg_data[53]
  PIN cfg_data[54]
    DIRECTION INPUT ;
    USE SIGNAL ;
    PORT
      LAYER M3 ;
        RECT  17.964 0 17.982 0.038 ;
    END
  END cfg_data[54]
  PIN cfg_data[55]
    DIRECTION INPUT ;
    USE SIGNAL ;
    PORT
      LAYER M3 ;
        RECT  18.252 0 18.27 0.038 ;
    END
  END cfg_data[55]
  PIN cfg_data[56]
    DIRECTION INPUT ;
    USE SIGNAL ;
    PORT
      LAYER M3 ;
        RECT  18.504 0 18.522 0.038 ;
    END
  END cfg_data[56]
  PIN cfg_data[57]
    DIRECTION INPUT ;
    USE SIGNAL ;
    PORT
      LAYER M3 ;
        RECT  18.756 0 18.774 0.038 ;
    END
  END cfg_data[57]
  PIN cfg_data[58]
    DIRECTION INPUT ;
    USE SIGNAL ;
    PORT
      LAYER M3 ;
        RECT  19.008 0 19.026 0.038 ;
    END
  END cfg_data[58]
  PIN cfg_data[59]
    DIRECTION INPUT ;
    USE SIGNAL ;
    PORT
      LAYER M3 ;
        RECT  19.26 0 19.278 0.038 ;
    END
  END cfg_data[59]
  PIN cfg_data[5]
    DIRECTION INPUT ;
    USE SIGNAL ;
    PORT
      LAYER M3 ;
        RECT  5.472 0 5.49 0.038 ;
    END
  END cfg_data[5]
  PIN cfg_data[60]
    DIRECTION INPUT ;
    USE SIGNAL ;
    PORT
      LAYER M3 ;
        RECT  19.512 0 19.53 0.038 ;
    END
  END cfg_data[60]
  PIN cfg_data[61]
    DIRECTION INPUT ;
    USE SIGNAL ;
    PORT
      LAYER M3 ;
        RECT  19.764 0 19.782 0.038 ;
    END
  END cfg_data[61]
  PIN cfg_data[62]
    DIRECTION INPUT ;
    USE SIGNAL ;
    PORT
      LAYER M3 ;
        RECT  20.016 0 20.034 0.038 ;
    END
  END cfg_data[62]
  PIN cfg_data[63]
    DIRECTION INPUT ;
    USE SIGNAL ;
    PORT
      LAYER M3 ;
        RECT  20.268 0 20.286 0.038 ;
    END
  END cfg_data[63]
  PIN cfg_data[64]
    DIRECTION INPUT ;
    USE SIGNAL ;
    PORT
      LAYER M3 ;
        RECT  20.52 0 20.538 0.038 ;
    END
  END cfg_data[64]
  PIN cfg_data[65]
    DIRECTION INPUT ;
    USE SIGNAL ;
    PORT
      LAYER M3 ;
        RECT  20.808 0 20.826 0.038 ;
    END
  END cfg_data[65]
  PIN cfg_data[66]
    DIRECTION INPUT ;
    USE SIGNAL ;
    PORT
      LAYER M3 ;
        RECT  21.06 0 21.078 0.038 ;
    END
  END cfg_data[66]
  PIN cfg_data[67]
    DIRECTION INPUT ;
    USE SIGNAL ;
    PORT
      LAYER M3 ;
        RECT  21.312 0 21.33 0.038 ;
    END
  END cfg_data[67]
  PIN cfg_data[68]
    DIRECTION INPUT ;
    USE SIGNAL ;
    PORT
      LAYER M3 ;
        RECT  21.564 0 21.582 0.038 ;
    END
  END cfg_data[68]
  PIN cfg_data[69]
    DIRECTION INPUT ;
    USE SIGNAL ;
    PORT
      LAYER M3 ;
        RECT  21.816 0 21.834 0.038 ;
    END
  END cfg_data[69]
  PIN cfg_data[6]
    DIRECTION INPUT ;
    USE SIGNAL ;
    PORT
      LAYER M3 ;
        RECT  5.724 0 5.742 0.038 ;
    END
  END cfg_data[6]
  PIN cfg_data[70]
    DIRECTION INPUT ;
    USE SIGNAL ;
    PORT
      LAYER M3 ;
        RECT  22.068 0 22.086 0.038 ;
    END
  END cfg_data[70]
  PIN cfg_data[71]
    DIRECTION INPUT ;
    USE SIGNAL ;
    PORT
      LAYER M3 ;
        RECT  22.32 0 22.338 0.038 ;
    END
  END cfg_data[71]
  PIN cfg_data[72]
    DIRECTION INPUT ;
    USE SIGNAL ;
    PORT
      LAYER M3 ;
        RECT  22.572 0 22.59 0.038 ;
    END
  END cfg_data[72]
  PIN cfg_data[73]
    DIRECTION INPUT ;
    USE SIGNAL ;
    PORT
      LAYER M3 ;
        RECT  22.824 0 22.842 0.038 ;
    END
  END cfg_data[73]
  PIN cfg_data[74]
    DIRECTION INPUT ;
    USE SIGNAL ;
    PORT
      LAYER M3 ;
        RECT  23.076 0 23.094 0.038 ;
    END
  END cfg_data[74]
  PIN cfg_data[75]
    DIRECTION INPUT ;
    USE SIGNAL ;
    PORT
      LAYER M3 ;
        RECT  23.328 0 23.346 0.038 ;
    END
  END cfg_data[75]
  PIN cfg_data[76]
    DIRECTION INPUT ;
    USE SIGNAL ;
    PORT
      LAYER M3 ;
        RECT  23.616 0 23.634 0.038 ;
    END
  END cfg_data[76]
  PIN cfg_data[77]
    DIRECTION INPUT ;
    USE SIGNAL ;
    PORT
      LAYER M3 ;
        RECT  23.868 0 23.886 0.038 ;
    END
  END cfg_data[77]
  PIN cfg_data[78]
    DIRECTION INPUT ;
    USE SIGNAL ;
    PORT
      LAYER M3 ;
        RECT  24.12 0 24.138 0.038 ;
    END
  END cfg_data[78]
  PIN cfg_data[79]
    DIRECTION INPUT ;
    USE SIGNAL ;
    PORT
      LAYER M3 ;
        RECT  24.372 0 24.39 0.038 ;
    END
  END cfg_data[79]
  PIN cfg_data[7]
    DIRECTION INPUT ;
    USE SIGNAL ;
    PORT
      LAYER M3 ;
        RECT  5.976 0 5.994 0.038 ;
    END
  END cfg_data[7]
  PIN cfg_data[80]
    DIRECTION INPUT ;
    USE SIGNAL ;
    PORT
      LAYER M3 ;
        RECT  24.624 0 24.642 0.038 ;
    END
  END cfg_data[80]
  PIN cfg_data[81]
    DIRECTION INPUT ;
    USE SIGNAL ;
    PORT
      LAYER M3 ;
        RECT  24.876 0 24.894 0.038 ;
    END
  END cfg_data[81]
  PIN cfg_data[82]
    DIRECTION INPUT ;
    USE SIGNAL ;
    PORT
      LAYER M3 ;
        RECT  25.128 0 25.146 0.038 ;
    END
  END cfg_data[82]
  PIN cfg_data[83]
    DIRECTION INPUT ;
    USE SIGNAL ;
    PORT
      LAYER M3 ;
        RECT  25.38 0 25.398 0.038 ;
    END
  END cfg_data[83]
  PIN cfg_data[84]
    DIRECTION INPUT ;
    USE SIGNAL ;
    PORT
      LAYER M5 ;
        RECT  25.632 0 25.656 0.084 ;
    END
  END cfg_data[84]
  PIN cfg_data[85]
    DIRECTION INPUT ;
    USE SIGNAL ;
    PORT
      LAYER M5 ;
        RECT  25.92 0 25.944 0.084 ;
    END
  END cfg_data[85]
  PIN cfg_data[86]
    DIRECTION INPUT ;
    USE SIGNAL ;
    PORT
      LAYER M5 ;
        RECT  26.16 0 26.184 0.084 ;
    END
  END cfg_data[86]
  PIN cfg_data[87]
    DIRECTION INPUT ;
    USE SIGNAL ;
    PORT
      LAYER M5 ;
        RECT  26.4 0 26.424 0.084 ;
    END
  END cfg_data[87]
  PIN cfg_data[88]
    DIRECTION INPUT ;
    USE SIGNAL ;
    PORT
      LAYER M5 ;
        RECT  26.64 0 26.664 0.084 ;
    END
  END cfg_data[88]
  PIN cfg_data[89]
    DIRECTION INPUT ;
    USE SIGNAL ;
    PORT
      LAYER M5 ;
        RECT  26.928 0 26.952 0.084 ;
    END
  END cfg_data[89]
  PIN cfg_data[8]
    DIRECTION INPUT ;
    USE SIGNAL ;
    PORT
      LAYER M3 ;
        RECT  6.228 0 6.246 0.038 ;
    END
  END cfg_data[8]
  PIN cfg_data[90]
    DIRECTION INPUT ;
    USE SIGNAL ;
    PORT
      LAYER M5 ;
        RECT  27.168 0 27.192 0.084 ;
    END
  END cfg_data[90]
  PIN cfg_data[91]
    DIRECTION INPUT ;
    USE SIGNAL ;
    PORT
      LAYER M5 ;
        RECT  27.408 0 27.432 0.084 ;
    END
  END cfg_data[91]
  PIN cfg_data[92]
    DIRECTION INPUT ;
    USE SIGNAL ;
    PORT
      LAYER M5 ;
        RECT  27.696 0 27.72 0.084 ;
    END
  END cfg_data[92]
  PIN cfg_data[93]
    DIRECTION INPUT ;
    USE SIGNAL ;
    PORT
      LAYER M5 ;
        RECT  27.936 0 27.96 0.084 ;
    END
  END cfg_data[93]
  PIN cfg_data[94]
    DIRECTION INPUT ;
    USE SIGNAL ;
    PORT
      LAYER M5 ;
        RECT  28.176 0 28.2 0.084 ;
    END
  END cfg_data[94]
  PIN cfg_data[95]
    DIRECTION INPUT ;
    USE SIGNAL ;
    PORT
      LAYER M5 ;
        RECT  28.464 0 28.488 0.084 ;
    END
  END cfg_data[95]
  PIN cfg_data[96]
    DIRECTION INPUT ;
    USE SIGNAL ;
    PORT
      LAYER M5 ;
        RECT  28.704 0 28.728 0.084 ;
    END
  END cfg_data[96]
  PIN cfg_data[97]
    DIRECTION INPUT ;
    USE SIGNAL ;
    PORT
      LAYER M5 ;
        RECT  28.944 0 28.968 0.084 ;
    END
  END cfg_data[97]
  PIN cfg_data[98]
    DIRECTION INPUT ;
    USE SIGNAL ;
    PORT
      LAYER M5 ;
        RECT  29.232 0 29.256 0.084 ;
    END
  END cfg_data[98]
  PIN cfg_data[99]
    DIRECTION INPUT ;
    USE SIGNAL ;
    PORT
      LAYER M5 ;
        RECT  29.472 0 29.496 0.084 ;
    END
  END cfg_data[99]
  PIN cfg_data[9]
    DIRECTION INPUT ;
    USE SIGNAL ;
    PORT
      LAYER M3 ;
        RECT  6.48 0 6.498 0.038 ;
    END
  END cfg_data[9]
  PIN cfg_target[0]
    DIRECTION INPUT ;
    USE SIGNAL ;
    PORT
      LAYER M3 ;
        RECT  69.588 0 69.606 0.038 ;
    END
  END cfg_target[0]
  PIN cfg_target[1]
    DIRECTION INPUT ;
    USE SIGNAL ;
    PORT
      LAYER M3 ;
        RECT  69.84 0 69.858 0.038 ;
    END
  END cfg_target[1]
  PIN cfg_target[2]
    DIRECTION INPUT ;
    USE SIGNAL ;
    PORT
      LAYER M3 ;
        RECT  70.092 0 70.11 0.038 ;
    END
  END cfg_target[2]
  PIN cfg_target[3]
    DIRECTION INPUT ;
    USE SIGNAL ;
    PORT
      LAYER M3 ;
        RECT  70.344 0 70.362 0.038 ;
    END
  END cfg_target[3]
  PIN cfg_target[4]
    DIRECTION INPUT ;
    USE SIGNAL ;
    PORT
      LAYER M3 ;
        RECT  70.596 0 70.614 0.038 ;
    END
  END cfg_target[4]
  PIN cfg_target[5]
    DIRECTION INPUT ;
    USE SIGNAL ;
    PORT
      LAYER M3 ;
        RECT  70.848 0 70.866 0.038 ;
    END
  END cfg_target[5]
  PIN cfg_target[6]
    DIRECTION INPUT ;
    USE SIGNAL ;
    PORT
      LAYER M3 ;
        RECT  71.136 0 71.154 0.038 ;
    END
  END cfg_target[6]
  PIN cfg_target[7]
    DIRECTION INPUT ;
    USE SIGNAL ;
    PORT
      LAYER M3 ;
        RECT  71.388 0 71.406 0.038 ;
    END
  END cfg_target[7]
  PIN cfg_v
    DIRECTION INPUT ;
    USE SIGNAL ;
    PORT
      LAYER M3 ;
        RECT  71.64 0 71.658 0.038 ;
    END
  END cfg_v
  PIN clk
    DIRECTION INPUT ;
    USE SIGNAL ;
    PORT
      LAYER M3 ;
        RECT  50.58 0 50.598 0.038 ;
    END
  END clk
  PIN configured
    DIRECTION OUTPUT ;
    USE SIGNAL ;
    PORT
      LAYER M3 ;
        RECT  71.892 0 71.91 0.038 ;
    END
  END configured
  PIN desc_base[0]
    DIRECTION INPUT ;
    USE SIGNAL ;
    PORT
      LAYER M3 ;
        RECT  72.144 0 72.162 0.038 ;
    END
  END desc_base[0]
  PIN desc_base[10]
    DIRECTION INPUT ;
    USE SIGNAL ;
    PORT
      LAYER M5 ;
        RECT  74.688 0 74.712 0.084 ;
    END
  END desc_base[10]
  PIN desc_base[11]
    DIRECTION INPUT ;
    USE SIGNAL ;
    PORT
      LAYER M5 ;
        RECT  74.928 0 74.952 0.084 ;
    END
  END desc_base[11]
  PIN desc_base[1]
    DIRECTION INPUT ;
    USE SIGNAL ;
    PORT
      LAYER M3 ;
        RECT  72.396 0 72.414 0.038 ;
    END
  END desc_base[1]
  PIN desc_base[2]
    DIRECTION INPUT ;
    USE SIGNAL ;
    PORT
      LAYER M3 ;
        RECT  72.648 0 72.666 0.038 ;
    END
  END desc_base[2]
  PIN desc_base[3]
    DIRECTION INPUT ;
    USE SIGNAL ;
    PORT
      LAYER M3 ;
        RECT  72.9 0 72.918 0.038 ;
    END
  END desc_base[3]
  PIN desc_base[4]
    DIRECTION INPUT ;
    USE SIGNAL ;
    PORT
      LAYER M3 ;
        RECT  73.152 0 73.17 0.038 ;
    END
  END desc_base[4]
  PIN desc_base[5]
    DIRECTION INPUT ;
    USE SIGNAL ;
    PORT
      LAYER M3 ;
        RECT  73.404 0 73.422 0.038 ;
    END
  END desc_base[5]
  PIN desc_base[6]
    DIRECTION INPUT ;
    USE SIGNAL ;
    PORT
      LAYER M3 ;
        RECT  73.692 0 73.71 0.038 ;
    END
  END desc_base[6]
  PIN desc_base[7]
    DIRECTION INPUT ;
    USE SIGNAL ;
    PORT
      LAYER M3 ;
        RECT  73.944 0 73.962 0.038 ;
    END
  END desc_base[7]
  PIN desc_base[8]
    DIRECTION INPUT ;
    USE SIGNAL ;
    PORT
      LAYER M3 ;
        RECT  74.196 0 74.214 0.038 ;
    END
  END desc_base[8]
  PIN desc_base[9]
    DIRECTION INPUT ;
    USE SIGNAL ;
    PORT
      LAYER M3 ;
        RECT  74.448 0 74.466 0.038 ;
    END
  END desc_base[9]
  PIN desc_limit[0]
    DIRECTION INPUT ;
    USE SIGNAL ;
    PORT
      LAYER M5 ;
        RECT  75.216 0 75.24 0.084 ;
    END
  END desc_limit[0]
  PIN desc_limit[10]
    DIRECTION INPUT ;
    USE SIGNAL ;
    PORT
      LAYER M5 ;
        RECT  77.76 0 77.784 0.084 ;
    END
  END desc_limit[10]
  PIN desc_limit[11]
    DIRECTION INPUT ;
    USE SIGNAL ;
    PORT
      LAYER M5 ;
        RECT  78 0 78.024 0.084 ;
    END
  END desc_limit[11]
  PIN desc_limit[12]
    DIRECTION INPUT ;
    USE SIGNAL ;
    PORT
      LAYER M5 ;
        RECT  78.288 0 78.312 0.084 ;
    END
  END desc_limit[12]
  PIN desc_limit[1]
    DIRECTION INPUT ;
    USE SIGNAL ;
    PORT
      LAYER M5 ;
        RECT  75.456 0 75.48 0.084 ;
    END
  END desc_limit[1]
  PIN desc_limit[2]
    DIRECTION INPUT ;
    USE SIGNAL ;
    PORT
      LAYER M5 ;
        RECT  75.696 0 75.72 0.084 ;
    END
  END desc_limit[2]
  PIN desc_limit[3]
    DIRECTION INPUT ;
    USE SIGNAL ;
    PORT
      LAYER M5 ;
        RECT  75.984 0 76.008 0.084 ;
    END
  END desc_limit[3]
  PIN desc_limit[4]
    DIRECTION INPUT ;
    USE SIGNAL ;
    PORT
      LAYER M5 ;
        RECT  76.224 0 76.248 0.084 ;
    END
  END desc_limit[4]
  PIN desc_limit[5]
    DIRECTION INPUT ;
    USE SIGNAL ;
    PORT
      LAYER M5 ;
        RECT  76.464 0 76.488 0.084 ;
    END
  END desc_limit[5]
  PIN desc_limit[6]
    DIRECTION INPUT ;
    USE SIGNAL ;
    PORT
      LAYER M5 ;
        RECT  76.752 0 76.776 0.084 ;
    END
  END desc_limit[6]
  PIN desc_limit[7]
    DIRECTION INPUT ;
    USE SIGNAL ;
    PORT
      LAYER M5 ;
        RECT  76.992 0 77.016 0.084 ;
    END
  END desc_limit[7]
  PIN desc_limit[8]
    DIRECTION INPUT ;
    USE SIGNAL ;
    PORT
      LAYER M5 ;
        RECT  77.232 0 77.256 0.084 ;
    END
  END desc_limit[8]
  PIN desc_limit[9]
    DIRECTION INPUT ;
    USE SIGNAL ;
    PORT
      LAYER M5 ;
        RECT  77.52 0 77.544 0.084 ;
    END
  END desc_limit[9]
  PIN desc_loops[0]
    DIRECTION INPUT ;
    USE SIGNAL ;
    PORT
      LAYER M5 ;
        RECT  78.528 0 78.552 0.084 ;
    END
  END desc_loops[0]
  PIN desc_loops[10]
    DIRECTION INPUT ;
    USE SIGNAL ;
    PORT
      LAYER M5 ;
        RECT  81.072 0 81.096 0.084 ;
    END
  END desc_loops[10]
  PIN desc_loops[11]
    DIRECTION INPUT ;
    USE SIGNAL ;
    PORT
      LAYER M5 ;
        RECT  81.36 0 81.384 0.084 ;
    END
  END desc_loops[11]
  PIN desc_loops[12]
    DIRECTION INPUT ;
    USE SIGNAL ;
    PORT
      LAYER M5 ;
        RECT  81.6 0 81.624 0.084 ;
    END
  END desc_loops[12]
  PIN desc_loops[13]
    DIRECTION INPUT ;
    USE SIGNAL ;
    PORT
      LAYER M5 ;
        RECT  81.84 0 81.864 0.084 ;
    END
  END desc_loops[13]
  PIN desc_loops[14]
    DIRECTION INPUT ;
    USE SIGNAL ;
    PORT
      LAYER M5 ;
        RECT  82.08 0 82.104 0.084 ;
    END
  END desc_loops[14]
  PIN desc_loops[15]
    DIRECTION INPUT ;
    USE SIGNAL ;
    PORT
      LAYER M5 ;
        RECT  82.368 0 82.392 0.084 ;
    END
  END desc_loops[15]
  PIN desc_loops[1]
    DIRECTION INPUT ;
    USE SIGNAL ;
    PORT
      LAYER M5 ;
        RECT  78.768 0 78.792 0.084 ;
    END
  END desc_loops[1]
  PIN desc_loops[2]
    DIRECTION INPUT ;
    USE SIGNAL ;
    PORT
      LAYER M5 ;
        RECT  79.056 0 79.08 0.084 ;
    END
  END desc_loops[2]
  PIN desc_loops[3]
    DIRECTION INPUT ;
    USE SIGNAL ;
    PORT
      LAYER M5 ;
        RECT  79.296 0 79.32 0.084 ;
    END
  END desc_loops[3]
  PIN desc_loops[4]
    DIRECTION INPUT ;
    USE SIGNAL ;
    PORT
      LAYER M5 ;
        RECT  79.536 0 79.56 0.084 ;
    END
  END desc_loops[4]
  PIN desc_loops[5]
    DIRECTION INPUT ;
    USE SIGNAL ;
    PORT
      LAYER M5 ;
        RECT  79.824 0 79.848 0.084 ;
    END
  END desc_loops[5]
  PIN desc_loops[6]
    DIRECTION INPUT ;
    USE SIGNAL ;
    PORT
      LAYER M5 ;
        RECT  80.064 0 80.088 0.084 ;
    END
  END desc_loops[6]
  PIN desc_loops[7]
    DIRECTION INPUT ;
    USE SIGNAL ;
    PORT
      LAYER M5 ;
        RECT  80.304 0 80.328 0.084 ;
    END
  END desc_loops[7]
  PIN desc_loops[8]
    DIRECTION INPUT ;
    USE SIGNAL ;
    PORT
      LAYER M5 ;
        RECT  80.592 0 80.616 0.084 ;
    END
  END desc_loops[8]
  PIN desc_loops[9]
    DIRECTION INPUT ;
    USE SIGNAL ;
    PORT
      LAYER M5 ;
        RECT  80.832 0 80.856 0.084 ;
    END
  END desc_loops[9]
  PIN desc_v
    DIRECTION INPUT ;
    USE SIGNAL ;
    PORT
      LAYER M5 ;
        RECT  82.608 0 82.632 0.084 ;
    END
  END desc_v
  PIN fault
    DIRECTION OUTPUT ;
    USE SIGNAL ;
    PORT
      LAYER M3 ;
        RECT  82.872 0 82.89 0.038 ;
    END
  END fault
  PIN fault_cause[0]
    DIRECTION OUTPUT ;
    USE SIGNAL ;
    PORT
      LAYER M3 ;
        RECT  83.124 0 83.142 0.038 ;
    END
  END fault_cause[0]
  PIN fault_cause[10]
    DIRECTION OUTPUT ;
    USE SIGNAL ;
    PORT
      LAYER M3 ;
        RECT  85.68 0 85.698 0.038 ;
    END
  END fault_cause[10]
  PIN fault_cause[11]
    DIRECTION OUTPUT ;
    USE SIGNAL ;
    PORT
      LAYER M3 ;
        RECT  85.932 0 85.95 0.038 ;
    END
  END fault_cause[11]
  PIN fault_cause[12]
    DIRECTION OUTPUT ;
    USE SIGNAL ;
    PORT
      LAYER M3 ;
        RECT  86.184 0 86.202 0.038 ;
    END
  END fault_cause[12]
  PIN fault_cause[13]
    DIRECTION OUTPUT ;
    USE SIGNAL ;
    PORT
      LAYER M3 ;
        RECT  86.436 0 86.454 0.038 ;
    END
  END fault_cause[13]
  PIN fault_cause[14]
    DIRECTION OUTPUT ;
    USE SIGNAL ;
    PORT
      LAYER M3 ;
        RECT  86.688 0 86.706 0.038 ;
    END
  END fault_cause[14]
  PIN fault_cause[15]
    DIRECTION OUTPUT ;
    USE SIGNAL ;
    PORT
      LAYER M3 ;
        RECT  86.976 0 86.994 0.038 ;
    END
  END fault_cause[15]
  PIN fault_cause[1]
    DIRECTION OUTPUT ;
    USE SIGNAL ;
    PORT
      LAYER M3 ;
        RECT  83.376 0 83.394 0.038 ;
    END
  END fault_cause[1]
  PIN fault_cause[2]
    DIRECTION OUTPUT ;
    USE SIGNAL ;
    PORT
      LAYER M3 ;
        RECT  83.628 0 83.646 0.038 ;
    END
  END fault_cause[2]
  PIN fault_cause[3]
    DIRECTION OUTPUT ;
    USE SIGNAL ;
    PORT
      LAYER M3 ;
        RECT  83.88 0 83.898 0.038 ;
    END
  END fault_cause[3]
  PIN fault_cause[4]
    DIRECTION OUTPUT ;
    USE SIGNAL ;
    PORT
      LAYER M3 ;
        RECT  84.132 0 84.15 0.038 ;
    END
  END fault_cause[4]
  PIN fault_cause[5]
    DIRECTION OUTPUT ;
    USE SIGNAL ;
    PORT
      LAYER M3 ;
        RECT  84.42 0 84.438 0.038 ;
    END
  END fault_cause[5]
  PIN fault_cause[6]
    DIRECTION OUTPUT ;
    USE SIGNAL ;
    PORT
      LAYER M3 ;
        RECT  84.672 0 84.69 0.038 ;
    END
  END fault_cause[6]
  PIN fault_cause[7]
    DIRECTION OUTPUT ;
    USE SIGNAL ;
    PORT
      LAYER M3 ;
        RECT  84.924 0 84.942 0.038 ;
    END
  END fault_cause[7]
  PIN fault_cause[8]
    DIRECTION OUTPUT ;
    USE SIGNAL ;
    PORT
      LAYER M3 ;
        RECT  85.176 0 85.194 0.038 ;
    END
  END fault_cause[8]
  PIN fault_cause[9]
    DIRECTION OUTPUT ;
    USE SIGNAL ;
    PORT
      LAYER M3 ;
        RECT  85.428 0 85.446 0.038 ;
    END
  END fault_cause[9]
  PIN init_busy
    DIRECTION OUTPUT ;
    USE SIGNAL ;
    PORT
      LAYER M3 ;
        RECT  87.228 0 87.246 0.038 ;
    END
  END init_busy
  PIN issuer_busy
    DIRECTION INPUT ;
    USE SIGNAL ;
    PORT
      LAYER M3 ;
        RECT  87.48 0 87.498 0.038 ;
    END
  END issuer_busy
  PIN issuer_cfg[0]
    DIRECTION OUTPUT ;
    USE SIGNAL ;
    PORT
      LAYER M3 ;
        RECT  87.732 0 87.75 0.038 ;
    END
  END issuer_cfg[0]
  PIN issuer_cfg[10]
    DIRECTION OUTPUT ;
    USE SIGNAL ;
    PORT
      LAYER M3 ;
        RECT  90.288 0 90.306 0.038 ;
    END
  END issuer_cfg[10]
  PIN issuer_cfg[11]
    DIRECTION OUTPUT ;
    USE SIGNAL ;
    PORT
      LAYER M3 ;
        RECT  90.54 0 90.558 0.038 ;
    END
  END issuer_cfg[11]
  PIN issuer_cfg[12]
    DIRECTION OUTPUT ;
    USE SIGNAL ;
    PORT
      LAYER M3 ;
        RECT  90.792 0 90.81 0.038 ;
    END
  END issuer_cfg[12]
  PIN issuer_cfg[13]
    DIRECTION OUTPUT ;
    USE SIGNAL ;
    PORT
      LAYER M5 ;
        RECT  91.056 0 91.08 0.084 ;
    END
  END issuer_cfg[13]
  PIN issuer_cfg[14]
    DIRECTION OUTPUT ;
    USE SIGNAL ;
    PORT
      LAYER M5 ;
        RECT  91.296 0 91.32 0.084 ;
    END
  END issuer_cfg[14]
  PIN issuer_cfg[15]
    DIRECTION OUTPUT ;
    USE SIGNAL ;
    PORT
      LAYER M5 ;
        RECT  91.536 0 91.56 0.084 ;
    END
  END issuer_cfg[15]
  PIN issuer_cfg[16]
    DIRECTION OUTPUT ;
    USE SIGNAL ;
    PORT
      LAYER M5 ;
        RECT  91.824 0 91.848 0.084 ;
    END
  END issuer_cfg[16]
  PIN issuer_cfg[17]
    DIRECTION OUTPUT ;
    USE SIGNAL ;
    PORT
      LAYER M5 ;
        RECT  92.064 0 92.088 0.084 ;
    END
  END issuer_cfg[17]
  PIN issuer_cfg[18]
    DIRECTION OUTPUT ;
    USE SIGNAL ;
    PORT
      LAYER M5 ;
        RECT  92.304 0 92.328 0.084 ;
    END
  END issuer_cfg[18]
  PIN issuer_cfg[19]
    DIRECTION OUTPUT ;
    USE SIGNAL ;
    PORT
      LAYER M5 ;
        RECT  92.592 0 92.616 0.084 ;
    END
  END issuer_cfg[19]
  PIN issuer_cfg[1]
    DIRECTION OUTPUT ;
    USE SIGNAL ;
    PORT
      LAYER M3 ;
        RECT  87.984 0 88.002 0.038 ;
    END
  END issuer_cfg[1]
  PIN issuer_cfg[20]
    DIRECTION OUTPUT ;
    USE SIGNAL ;
    PORT
      LAYER M5 ;
        RECT  92.832 0 92.856 0.084 ;
    END
  END issuer_cfg[20]
  PIN issuer_cfg[21]
    DIRECTION OUTPUT ;
    USE SIGNAL ;
    PORT
      LAYER M5 ;
        RECT  93.072 0 93.096 0.084 ;
    END
  END issuer_cfg[21]
  PIN issuer_cfg[22]
    DIRECTION OUTPUT ;
    USE SIGNAL ;
    PORT
      LAYER M5 ;
        RECT  93.36 0 93.384 0.084 ;
    END
  END issuer_cfg[22]
  PIN issuer_cfg[23]
    DIRECTION OUTPUT ;
    USE SIGNAL ;
    PORT
      LAYER M5 ;
        RECT  93.6 0 93.624 0.084 ;
    END
  END issuer_cfg[23]
  PIN issuer_cfg[24]
    DIRECTION OUTPUT ;
    USE SIGNAL ;
    PORT
      LAYER M5 ;
        RECT  93.84 0 93.864 0.084 ;
    END
  END issuer_cfg[24]
  PIN issuer_cfg[25]
    DIRECTION OUTPUT ;
    USE SIGNAL ;
    PORT
      LAYER M5 ;
        RECT  94.128 0 94.152 0.084 ;
    END
  END issuer_cfg[25]
  PIN issuer_cfg[26]
    DIRECTION OUTPUT ;
    USE SIGNAL ;
    PORT
      LAYER M5 ;
        RECT  94.368 0 94.392 0.084 ;
    END
  END issuer_cfg[26]
  PIN issuer_cfg[27]
    DIRECTION OUTPUT ;
    USE SIGNAL ;
    PORT
      LAYER M5 ;
        RECT  94.608 0 94.632 0.084 ;
    END
  END issuer_cfg[27]
  PIN issuer_cfg[28]
    DIRECTION OUTPUT ;
    USE SIGNAL ;
    PORT
      LAYER M5 ;
        RECT  94.896 0 94.92 0.084 ;
    END
  END issuer_cfg[28]
  PIN issuer_cfg[29]
    DIRECTION OUTPUT ;
    USE SIGNAL ;
    PORT
      LAYER M5 ;
        RECT  95.136 0 95.16 0.084 ;
    END
  END issuer_cfg[29]
  PIN issuer_cfg[2]
    DIRECTION OUTPUT ;
    USE SIGNAL ;
    PORT
      LAYER M3 ;
        RECT  88.236 0 88.254 0.038 ;
    END
  END issuer_cfg[2]
  PIN issuer_cfg[30]
    DIRECTION OUTPUT ;
    USE SIGNAL ;
    PORT
      LAYER M5 ;
        RECT  95.376 0 95.4 0.084 ;
    END
  END issuer_cfg[30]
  PIN issuer_cfg[31]
    DIRECTION OUTPUT ;
    USE SIGNAL ;
    PORT
      LAYER M5 ;
        RECT  95.664 0 95.688 0.084 ;
    END
  END issuer_cfg[31]
  PIN issuer_cfg[32]
    DIRECTION OUTPUT ;
    USE SIGNAL ;
    PORT
      LAYER M5 ;
        RECT  95.904 0 95.928 0.084 ;
    END
  END issuer_cfg[32]
  PIN issuer_cfg[33]
    DIRECTION OUTPUT ;
    USE SIGNAL ;
    PORT
      LAYER M5 ;
        RECT  96.144 0 96.168 0.084 ;
    END
  END issuer_cfg[33]
  PIN issuer_cfg[34]
    DIRECTION OUTPUT ;
    USE SIGNAL ;
    PORT
      LAYER M5 ;
        RECT  96.432 0 96.456 0.084 ;
    END
  END issuer_cfg[34]
  PIN issuer_cfg[35]
    DIRECTION OUTPUT ;
    USE SIGNAL ;
    PORT
      LAYER M5 ;
        RECT  96.672 0 96.696 0.084 ;
    END
  END issuer_cfg[35]
  PIN issuer_cfg[36]
    DIRECTION OUTPUT ;
    USE SIGNAL ;
    PORT
      LAYER M5 ;
        RECT  96.912 0 96.936 0.084 ;
    END
  END issuer_cfg[36]
  PIN issuer_cfg[3]
    DIRECTION OUTPUT ;
    USE SIGNAL ;
    PORT
      LAYER M3 ;
        RECT  88.488 0 88.506 0.038 ;
    END
  END issuer_cfg[3]
  PIN issuer_cfg[4]
    DIRECTION OUTPUT ;
    USE SIGNAL ;
    PORT
      LAYER M3 ;
        RECT  88.74 0 88.758 0.038 ;
    END
  END issuer_cfg[4]
  PIN issuer_cfg[5]
    DIRECTION OUTPUT ;
    USE SIGNAL ;
    PORT
      LAYER M3 ;
        RECT  88.992 0 89.01 0.038 ;
    END
  END issuer_cfg[5]
  PIN issuer_cfg[6]
    DIRECTION OUTPUT ;
    USE SIGNAL ;
    PORT
      LAYER M3 ;
        RECT  89.244 0 89.262 0.038 ;
    END
  END issuer_cfg[6]
  PIN issuer_cfg[7]
    DIRECTION OUTPUT ;
    USE SIGNAL ;
    PORT
      LAYER M3 ;
        RECT  89.532 0 89.55 0.038 ;
    END
  END issuer_cfg[7]
  PIN issuer_cfg[8]
    DIRECTION OUTPUT ;
    USE SIGNAL ;
    PORT
      LAYER M3 ;
        RECT  89.784 0 89.802 0.038 ;
    END
  END issuer_cfg[8]
  PIN issuer_cfg[9]
    DIRECTION OUTPUT ;
    USE SIGNAL ;
    PORT
      LAYER M3 ;
        RECT  90.036 0 90.054 0.038 ;
    END
  END issuer_cfg[9]
  PIN issuer_fault
    DIRECTION INPUT ;
    USE SIGNAL ;
    PORT
      LAYER M5 ;
        RECT  97.152 0 97.176 0.084 ;
    END
  END issuer_fault
  PIN issuer_start
    DIRECTION OUTPUT ;
    USE SIGNAL ;
    PORT
      LAYER M5 ;
        RECT  97.44 0 97.464 0.084 ;
    END
  END issuer_start
  PIN issuer_start_pc[0]
    DIRECTION OUTPUT ;
    USE SIGNAL ;
    PORT
      LAYER M5 ;
        RECT  97.68 0 97.704 0.084 ;
    END
  END issuer_start_pc[0]
  PIN issuer_start_pc[1]
    DIRECTION OUTPUT ;
    USE SIGNAL ;
    PORT
      LAYER M5 ;
        RECT  97.92 0 97.944 0.084 ;
    END
  END issuer_start_pc[1]
  PIN issuer_start_pc[2]
    DIRECTION OUTPUT ;
    USE SIGNAL ;
    PORT
      LAYER M5 ;
        RECT  98.208 0 98.232 0.084 ;
    END
  END issuer_start_pc[2]
  PIN issuer_start_pc[3]
    DIRECTION OUTPUT ;
    USE SIGNAL ;
    PORT
      LAYER M5 ;
        RECT  98.448 0 98.472 0.084 ;
    END
  END issuer_start_pc[3]
  PIN issuer_start_pc[4]
    DIRECTION OUTPUT ;
    USE SIGNAL ;
    PORT
      LAYER M5 ;
        RECT  98.688 0 98.712 0.084 ;
    END
  END issuer_start_pc[4]
  PIN issuer_start_pc[5]
    DIRECTION OUTPUT ;
    USE SIGNAL ;
    PORT
      LAYER M5 ;
        RECT  98.976 0 99 0.084 ;
    END
  END issuer_start_pc[5]
  PIN issuer_start_pc[6]
    DIRECTION OUTPUT ;
    USE SIGNAL ;
    PORT
      LAYER M3 ;
        RECT  99.216 0 99.234 0.038 ;
    END
  END issuer_start_pc[6]
  PIN issuer_uop_pc[0]
    DIRECTION INPUT ;
    USE SIGNAL ;
    PORT
      LAYER M3 ;
        RECT  99.468 0 99.486 0.038 ;
    END
  END issuer_uop_pc[0]
  PIN issuer_uop_pc[1]
    DIRECTION INPUT ;
    USE SIGNAL ;
    PORT
      LAYER M3 ;
        RECT  99.72 0 99.738 0.038 ;
    END
  END issuer_uop_pc[1]
  PIN issuer_uop_pc[2]
    DIRECTION INPUT ;
    USE SIGNAL ;
    PORT
      LAYER M3 ;
        RECT  99.972 0 99.99 0.038 ;
    END
  END issuer_uop_pc[2]
  PIN issuer_uop_pc[3]
    DIRECTION INPUT ;
    USE SIGNAL ;
    PORT
      LAYER M3 ;
        RECT  100.26 0 100.278 0.038 ;
    END
  END issuer_uop_pc[3]
  PIN issuer_uop_pc[4]
    DIRECTION INPUT ;
    USE SIGNAL ;
    PORT
      LAYER M3 ;
        RECT  100.512 0 100.53 0.038 ;
    END
  END issuer_uop_pc[4]
  PIN issuer_uop_pc[5]
    DIRECTION INPUT ;
    USE SIGNAL ;
    PORT
      LAYER M3 ;
        RECT  100.764 0 100.782 0.038 ;
    END
  END issuer_uop_pc[5]
  PIN issuer_uop_pc[6]
    DIRECTION INPUT ;
    USE SIGNAL ;
    PORT
      LAYER M3 ;
        RECT  101.016 0 101.034 0.038 ;
    END
  END issuer_uop_pc[6]
  PIN issuer_uop_v
    DIRECTION INPUT ;
    USE SIGNAL ;
    PORT
      LAYER M3 ;
        RECT  101.268 0 101.286 0.038 ;
    END
  END issuer_uop_v
  PIN launch_v
    DIRECTION INPUT ;
    USE SIGNAL ;
    PORT
      LAYER M3 ;
        RECT  101.52 0 101.538 0.038 ;
    END
  END launch_v
  PIN link_abort[0]
    DIRECTION INPUT ;
    USE SIGNAL ;
    PORT
      LAYER M4 ;
        RECT  0 7.92 0.084 7.944 ;
    END
  END link_abort[0]
  PIN link_abort[1]
    DIRECTION INPUT ;
    USE SIGNAL ;
    PORT
      LAYER M4 ;
        RECT  0 21.792 0.084 21.816 ;
    END
  END link_abort[1]
  PIN program_active
    DIRECTION INPUT ;
    USE SIGNAL ;
    PORT
      LAYER M3 ;
        RECT  101.772 0 101.79 0.038 ;
    END
  END program_active
  PIN program_fault
    DIRECTION OUTPUT ;
    USE SIGNAL ;
    PORT
      LAYER M3 ;
        RECT  102.024 0 102.042 0.038 ;
    END
  END program_fault
  PIN protocol_fault
    DIRECTION INPUT ;
    USE SIGNAL ;
    PORT
      LAYER M4 ;
        RECT  103.596 13.968 103.68 13.992 ;
    END
  END protocol_fault
  PIN qid[0]
    DIRECTION INPUT ;
    USE SIGNAL ;
    PORT
      LAYER M3 ;
        RECT  102.276 0 102.294 0.038 ;
    END
  END qid[0]
  PIN qid[1]
    DIRECTION INPUT ;
    USE SIGNAL ;
    PORT
      LAYER M3 ;
        RECT  102.528 0 102.546 0.038 ;
    END
  END qid[1]
  PIN reduce_fault
    DIRECTION INPUT ;
    USE SIGNAL ;
    PORT
      LAYER M4 ;
        RECT  0 35.616 0.084 35.64 ;
    END
  END reduce_fault
  PIN ring_fault
    DIRECTION INPUT ;
    USE SIGNAL ;
    PORT
      LAYER M4 ;
        RECT  0 49.488 0.084 49.512 ;
    END
  END ring_fault
  PIN rst_n
    DIRECTION INPUT ;
    USE SIGNAL ;
    PORT
      LAYER M3 ;
        RECT  51.804 0 51.822 0.038 ;
    END
  END rst_n
  PIN select_fault[0]
    DIRECTION INPUT ;
    USE SIGNAL ;
    PORT
      LAYER M4 ;
        RECT  103.596 15.216 103.68 15.24 ;
    END
  END select_fault[0]
  PIN select_fault[10]
    DIRECTION INPUT ;
    USE SIGNAL ;
    PORT
      LAYER M4 ;
        RECT  103.596 27.6 103.68 27.624 ;
    END
  END select_fault[10]
  PIN select_fault[11]
    DIRECTION INPUT ;
    USE SIGNAL ;
    PORT
      LAYER M4 ;
        RECT  103.596 28.848 103.68 28.872 ;
    END
  END select_fault[11]
  PIN select_fault[12]
    DIRECTION INPUT ;
    USE SIGNAL ;
    PORT
      LAYER M4 ;
        RECT  103.596 30.048 103.68 30.072 ;
    END
  END select_fault[12]
  PIN select_fault[13]
    DIRECTION INPUT ;
    USE SIGNAL ;
    PORT
      LAYER M4 ;
        RECT  103.596 31.296 103.68 31.32 ;
    END
  END select_fault[13]
  PIN select_fault[14]
    DIRECTION INPUT ;
    USE SIGNAL ;
    PORT
      LAYER M4 ;
        RECT  103.596 32.544 103.68 32.568 ;
    END
  END select_fault[14]
  PIN select_fault[15]
    DIRECTION INPUT ;
    USE SIGNAL ;
    PORT
      LAYER M4 ;
        RECT  103.596 33.792 103.68 33.816 ;
    END
  END select_fault[15]
  PIN select_fault[16]
    DIRECTION INPUT ;
    USE SIGNAL ;
    PORT
      LAYER M4 ;
        RECT  103.596 34.992 103.68 35.016 ;
    END
  END select_fault[16]
  PIN select_fault[17]
    DIRECTION INPUT ;
    USE SIGNAL ;
    PORT
      LAYER M4 ;
        RECT  103.596 36.24 103.68 36.264 ;
    END
  END select_fault[17]
  PIN select_fault[1]
    DIRECTION INPUT ;
    USE SIGNAL ;
    PORT
      LAYER M4 ;
        RECT  103.596 16.464 103.68 16.488 ;
    END
  END select_fault[1]
  PIN select_fault[2]
    DIRECTION INPUT ;
    USE SIGNAL ;
    PORT
      LAYER M4 ;
        RECT  103.596 17.712 103.68 17.736 ;
    END
  END select_fault[2]
  PIN select_fault[3]
    DIRECTION INPUT ;
    USE SIGNAL ;
    PORT
      LAYER M4 ;
        RECT  103.596 18.912 103.68 18.936 ;
    END
  END select_fault[3]
  PIN select_fault[4]
    DIRECTION INPUT ;
    USE SIGNAL ;
    PORT
      LAYER M4 ;
        RECT  103.596 20.16 103.68 20.184 ;
    END
  END select_fault[4]
  PIN select_fault[5]
    DIRECTION INPUT ;
    USE SIGNAL ;
    PORT
      LAYER M4 ;
        RECT  103.596 21.408 103.68 21.432 ;
    END
  END select_fault[5]
  PIN select_fault[6]
    DIRECTION INPUT ;
    USE SIGNAL ;
    PORT
      LAYER M4 ;
        RECT  103.596 22.656 103.68 22.68 ;
    END
  END select_fault[6]
  PIN select_fault[7]
    DIRECTION INPUT ;
    USE SIGNAL ;
    PORT
      LAYER M4 ;
        RECT  103.596 23.856 103.68 23.88 ;
    END
  END select_fault[7]
  PIN select_fault[8]
    DIRECTION INPUT ;
    USE SIGNAL ;
    PORT
      LAYER M4 ;
        RECT  103.596 25.104 103.68 25.128 ;
    END
  END select_fault[8]
  PIN select_fault[9]
    DIRECTION INPUT ;
    USE SIGNAL ;
    PORT
      LAYER M4 ;
        RECT  103.596 26.352 103.68 26.376 ;
    END
  END select_fault[9]
  PIN tkm_del_slot[0]
    DIRECTION INPUT ;
    USE SIGNAL ;
    PORT
      LAYER M4 ;
        RECT  103.596 37.488 103.68 37.512 ;
    END
  END tkm_del_slot[0]
  PIN tkm_del_slot[1]
    DIRECTION INPUT ;
    USE SIGNAL ;
    PORT
      LAYER M4 ;
        RECT  103.596 38.736 103.68 38.76 ;
    END
  END tkm_del_slot[1]
  PIN tkm_del_slot[2]
    DIRECTION INPUT ;
    USE SIGNAL ;
    PORT
      LAYER M4 ;
        RECT  103.596 39.936 103.68 39.96 ;
    END
  END tkm_del_slot[2]
  PIN tkm_del_slot[3]
    DIRECTION INPUT ;
    USE SIGNAL ;
    PORT
      LAYER M4 ;
        RECT  103.596 41.184 103.68 41.208 ;
    END
  END tkm_del_slot[3]
  PIN tkm_dest_v[0]
    DIRECTION INPUT ;
    USE SIGNAL ;
    PORT
      LAYER M4 ;
        RECT  103.596 42.432 103.68 42.456 ;
    END
  END tkm_dest_v[0]
  PIN tkm_dest_v[1]
    DIRECTION INPUT ;
    USE SIGNAL ;
    PORT
      LAYER M4 ;
        RECT  103.596 43.68 103.68 43.704 ;
    END
  END tkm_dest_v[1]
  PIN tkm_dest_v[2]
    DIRECTION INPUT ;
    USE SIGNAL ;
    PORT
      LAYER M4 ;
        RECT  103.596 44.928 103.68 44.952 ;
    END
  END tkm_dest_v[2]
  PIN tkm_dest_v[3]
    DIRECTION INPUT ;
    USE SIGNAL ;
    PORT
      LAYER M4 ;
        RECT  103.596 46.128 103.68 46.152 ;
    END
  END tkm_dest_v[3]
  PIN tkm_start
    DIRECTION INPUT ;
    USE SIGNAL ;
    PORT
      LAYER M4 ;
        RECT  103.596 47.376 103.68 47.4 ;
    END
  END tkm_start
  PIN unavailable_fault[0]
    DIRECTION INPUT ;
    USE SIGNAL ;
    PORT
      LAYER M4 ;
        RECT  103.596 48.624 103.68 48.648 ;
    END
  END unavailable_fault[0]
  PIN unavailable_fault[10]
    DIRECTION INPUT ;
    USE SIGNAL ;
    PORT
      LAYER M4 ;
        RECT  103.596 61.008 103.68 61.032 ;
    END
  END unavailable_fault[10]
  PIN unavailable_fault[11]
    DIRECTION INPUT ;
    USE SIGNAL ;
    PORT
      LAYER M4 ;
        RECT  103.596 62.208 103.68 62.232 ;
    END
  END unavailable_fault[11]
  PIN unavailable_fault[12]
    DIRECTION INPUT ;
    USE SIGNAL ;
    PORT
      LAYER M4 ;
        RECT  103.596 63.456 103.68 63.48 ;
    END
  END unavailable_fault[12]
  PIN unavailable_fault[13]
    DIRECTION INPUT ;
    USE SIGNAL ;
    PORT
      LAYER M4 ;
        RECT  103.596 64.704 103.68 64.728 ;
    END
  END unavailable_fault[13]
  PIN unavailable_fault[14]
    DIRECTION INPUT ;
    USE SIGNAL ;
    PORT
      LAYER M4 ;
        RECT  103.596 65.952 103.68 65.976 ;
    END
  END unavailable_fault[14]
  PIN unavailable_fault[15]
    DIRECTION INPUT ;
    USE SIGNAL ;
    PORT
      LAYER M4 ;
        RECT  103.596 67.152 103.68 67.176 ;
    END
  END unavailable_fault[15]
  PIN unavailable_fault[16]
    DIRECTION INPUT ;
    USE SIGNAL ;
    PORT
      LAYER M4 ;
        RECT  103.596 68.4 103.68 68.424 ;
    END
  END unavailable_fault[16]
  PIN unavailable_fault[17]
    DIRECTION INPUT ;
    USE SIGNAL ;
    PORT
      LAYER M4 ;
        RECT  103.596 69.648 103.68 69.672 ;
    END
  END unavailable_fault[17]
  PIN unavailable_fault[1]
    DIRECTION INPUT ;
    USE SIGNAL ;
    PORT
      LAYER M4 ;
        RECT  103.596 49.872 103.68 49.896 ;
    END
  END unavailable_fault[1]
  PIN unavailable_fault[2]
    DIRECTION INPUT ;
    USE SIGNAL ;
    PORT
      LAYER M4 ;
        RECT  103.596 51.072 103.68 51.096 ;
    END
  END unavailable_fault[2]
  PIN unavailable_fault[3]
    DIRECTION INPUT ;
    USE SIGNAL ;
    PORT
      LAYER M4 ;
        RECT  103.596 52.32 103.68 52.344 ;
    END
  END unavailable_fault[3]
  PIN unavailable_fault[4]
    DIRECTION INPUT ;
    USE SIGNAL ;
    PORT
      LAYER M4 ;
        RECT  103.596 53.568 103.68 53.592 ;
    END
  END unavailable_fault[4]
  PIN unavailable_fault[5]
    DIRECTION INPUT ;
    USE SIGNAL ;
    PORT
      LAYER M4 ;
        RECT  103.596 54.816 103.68 54.84 ;
    END
  END unavailable_fault[5]
  PIN unavailable_fault[6]
    DIRECTION INPUT ;
    USE SIGNAL ;
    PORT
      LAYER M4 ;
        RECT  103.596 56.064 103.68 56.088 ;
    END
  END unavailable_fault[6]
  PIN unavailable_fault[7]
    DIRECTION INPUT ;
    USE SIGNAL ;
    PORT
      LAYER M4 ;
        RECT  103.596 57.264 103.68 57.288 ;
    END
  END unavailable_fault[7]
  PIN unavailable_fault[8]
    DIRECTION INPUT ;
    USE SIGNAL ;
    PORT
      LAYER M4 ;
        RECT  103.596 58.512 103.68 58.536 ;
    END
  END unavailable_fault[8]
  PIN unavailable_fault[9]
    DIRECTION INPUT ;
    USE SIGNAL ;
    PORT
      LAYER M4 ;
        RECT  103.596 59.76 103.68 59.784 ;
    END
  END unavailable_fault[9]
  PIN writer_fault
    DIRECTION INPUT ;
    USE SIGNAL ;
    PORT
      LAYER M4 ;
        RECT  0 63.36 0.084 63.384 ;
    END
  END writer_fault
  PIN VDD
    DIRECTION INOUT ;
    USE POWER ;
    PORT
      LAYER M5 ;
        RECT  99.792 2.151 99.912 69.129 ;
        RECT  94.392 2.151 94.512 69.129 ;
        RECT  88.992 2.151 89.112 69.129 ;
        RECT  83.592 2.151 83.712 69.129 ;
        RECT  78.192 2.151 78.312 69.129 ;
        RECT  72.792 2.151 72.912 69.129 ;
        RECT  67.392 2.151 67.512 69.129 ;
        RECT  61.992 2.151 62.112 69.129 ;
        RECT  56.592 2.151 56.712 69.129 ;
        RECT  51.192 2.151 51.312 69.129 ;
        RECT  45.792 2.151 45.912 69.129 ;
        RECT  40.392 2.151 40.512 69.129 ;
        RECT  34.992 2.151 35.112 69.129 ;
        RECT  29.592 2.151 29.712 69.129 ;
        RECT  24.192 2.151 24.312 69.129 ;
        RECT  18.792 2.151 18.912 69.129 ;
        RECT  13.392 2.151 13.512 69.129 ;
        RECT  7.992 2.151 8.112 69.129 ;
        RECT  2.592 2.151 2.712 69.129 ;
    END
  END VDD
  PIN VSS
    DIRECTION INOUT ;
    USE GROUND ;
    PORT
      LAYER M5 ;
        RECT  99.6 2.137 99.72 69.143 ;
        RECT  94.2 2.137 94.32 69.143 ;
        RECT  88.8 2.137 88.92 69.143 ;
        RECT  83.4 2.137 83.52 69.143 ;
        RECT  78 2.137 78.12 69.129 ;
        RECT  72.6 2.137 72.72 69.129 ;
        RECT  67.2 2.137 67.32 69.129 ;
        RECT  61.8 2.137 61.92 69.129 ;
        RECT  56.4 2.137 56.52 69.129 ;
        RECT  51 2.137 51.12 69.129 ;
        RECT  45.6 2.137 45.72 69.129 ;
        RECT  40.2 2.137 40.32 69.143 ;
        RECT  34.8 2.137 34.92 69.143 ;
        RECT  29.4 2.137 29.52 69.143 ;
        RECT  24 2.137 24.12 69.143 ;
        RECT  18.6 2.137 18.72 69.143 ;
        RECT  13.2 2.137 13.32 69.143 ;
        RECT  7.8 2.137 7.92 69.143 ;
        RECT  2.4 2.137 2.52 69.143 ;
    END
  END VSS
  OBS
    LAYER RVTN ;
     RECT  2.16 2.16 101.52 2.295 ;
     RECT  2.16 2.565 101.52 2.835 ;
     RECT  2.16 3.105 101.52 3.375 ;
     RECT  2.16 3.645 101.52 3.915 ;
     RECT  2.16 4.185 101.52 4.455 ;
     RECT  2.16 4.725 101.52 4.995 ;
     RECT  2.16 5.265 101.52 5.535 ;
     RECT  2.16 5.805 101.52 6.075 ;
     RECT  2.16 6.345 101.52 6.615 ;
     RECT  2.16 6.885 101.52 7.155 ;
     RECT  2.16 7.425 101.52 7.695 ;
     RECT  2.16 7.965 101.52 8.235 ;
     RECT  2.16 8.505 101.52 8.775 ;
     RECT  2.16 9.045 101.52 9.315 ;
     RECT  2.16 9.585 101.52 9.855 ;
     RECT  2.16 10.125 101.52 10.395 ;
     RECT  2.16 10.665 101.52 10.935 ;
     RECT  2.16 11.205 101.52 11.475 ;
     RECT  2.16 11.745 101.52 12.015 ;
     RECT  2.16 12.285 101.52 12.555 ;
     RECT  2.16 12.825 101.52 13.095 ;
     RECT  2.16 13.365 101.52 13.635 ;
     RECT  2.16 13.905 101.52 14.175 ;
     RECT  2.16 14.445 101.52 14.715 ;
     RECT  2.16 14.985 101.52 15.255 ;
     RECT  2.16 15.525 101.52 15.795 ;
     RECT  2.16 16.065 101.52 16.335 ;
     RECT  2.16 16.605 101.52 16.875 ;
     RECT  2.16 17.145 101.52 17.415 ;
     RECT  2.16 17.685 101.52 17.955 ;
     RECT  2.16 18.225 101.52 18.495 ;
     RECT  2.16 18.765 101.52 19.035 ;
     RECT  2.16 19.305 101.52 19.575 ;
     RECT  2.16 19.845 101.52 20.115 ;
     RECT  2.16 20.385 101.52 20.655 ;
     RECT  2.16 20.925 101.52 21.195 ;
     RECT  2.16 21.465 101.52 21.735 ;
     RECT  2.16 22.005 101.52 22.275 ;
     RECT  2.16 22.545 101.52 22.815 ;
     RECT  2.16 23.085 101.52 23.355 ;
     RECT  2.16 23.625 101.52 23.895 ;
     RECT  2.16 24.165 101.52 24.435 ;
     RECT  2.16 24.705 101.52 24.975 ;
     RECT  2.16 25.245 101.52 25.515 ;
     RECT  2.16 25.785 101.52 26.055 ;
     RECT  2.16 26.325 101.52 26.595 ;
     RECT  2.16 26.865 101.52 27.135 ;
     RECT  2.16 27.405 101.52 27.675 ;
     RECT  2.16 27.945 101.52 28.215 ;
     RECT  2.16 28.485 101.52 28.755 ;
     RECT  2.16 29.025 101.52 29.295 ;
     RECT  2.16 29.565 101.52 29.835 ;
     RECT  2.16 30.105 101.52 30.375 ;
     RECT  2.16 30.645 101.52 30.915 ;
     RECT  2.16 31.185 101.52 31.455 ;
     RECT  2.16 31.725 101.52 31.995 ;
     RECT  2.16 32.265 101.52 32.535 ;
     RECT  2.16 32.805 101.52 33.075 ;
     RECT  2.16 33.345 101.52 33.615 ;
     RECT  2.16 33.885 101.52 34.155 ;
     RECT  2.16 34.425 101.52 34.695 ;
     RECT  2.16 34.965 101.52 35.235 ;
     RECT  2.16 35.505 101.52 35.775 ;
     RECT  2.16 36.045 101.52 36.315 ;
     RECT  2.16 36.585 101.52 36.855 ;
     RECT  2.16 37.125 101.52 37.395 ;
     RECT  2.16 37.665 101.52 37.935 ;
     RECT  2.16 38.205 101.52 38.475 ;
     RECT  2.16 38.745 101.52 39.015 ;
     RECT  2.16 39.285 101.52 39.555 ;
     RECT  2.16 39.825 101.52 40.095 ;
     RECT  2.16 40.365 101.52 40.635 ;
     RECT  2.16 40.905 101.52 41.04 ;
     RECT  2.16 41.04 41.148 41.175 ;
     RECT  83.052 41.04 101.52 41.175 ;
     RECT  2.16 41.445 41.148 41.715 ;
     RECT  83.052 41.445 101.52 41.715 ;
     RECT  2.16 41.985 41.148 42.255 ;
     RECT  83.052 41.985 101.52 42.255 ;
     RECT  2.16 42.525 41.148 42.795 ;
     RECT  83.052 42.525 101.52 42.795 ;
     RECT  2.16 43.065 41.148 43.335 ;
     RECT  83.052 43.065 101.52 43.335 ;
     RECT  2.16 43.605 41.148 43.875 ;
     RECT  83.052 43.605 101.52 43.875 ;
     RECT  2.16 44.145 41.148 44.415 ;
     RECT  83.052 44.145 101.52 44.415 ;
     RECT  2.16 44.685 41.148 44.955 ;
     RECT  83.052 44.685 101.52 44.955 ;
     RECT  2.16 45.225 41.148 45.495 ;
     RECT  83.052 45.225 101.52 45.495 ;
     RECT  2.16 45.765 41.148 46.035 ;
     RECT  83.052 45.765 101.52 46.035 ;
     RECT  2.16 46.305 41.148 46.575 ;
     RECT  83.052 46.305 101.52 46.575 ;
     RECT  2.16 46.845 41.148 47.115 ;
     RECT  83.052 46.845 101.52 47.115 ;
     RECT  2.16 47.385 41.148 47.655 ;
     RECT  83.052 47.385 101.52 47.655 ;
     RECT  2.16 47.925 41.148 48.195 ;
     RECT  83.052 47.925 101.52 48.195 ;
     RECT  2.16 48.465 41.148 48.735 ;
     RECT  83.052 48.465 101.52 48.735 ;
     RECT  2.16 49.005 41.148 49.275 ;
     RECT  83.052 49.005 101.52 49.275 ;
     RECT  2.16 49.545 41.148 49.815 ;
     RECT  83.052 49.545 101.52 49.815 ;
     RECT  2.16 50.085 41.148 50.355 ;
     RECT  83.052 50.085 101.52 50.355 ;
     RECT  2.16 50.625 41.148 50.895 ;
     RECT  83.052 50.625 101.52 50.895 ;
     RECT  2.16 51.165 41.148 51.435 ;
     RECT  83.052 51.165 101.52 51.435 ;
     RECT  2.16 51.705 41.148 51.975 ;
     RECT  83.052 51.705 101.52 51.975 ;
     RECT  2.16 52.245 41.148 52.515 ;
     RECT  83.052 52.245 101.52 52.515 ;
     RECT  2.16 52.785 41.148 53.055 ;
     RECT  83.052 52.785 101.52 53.055 ;
     RECT  2.16 53.325 41.148 53.595 ;
     RECT  83.052 53.325 101.52 53.595 ;
     RECT  2.16 53.865 41.148 54.135 ;
     RECT  83.052 53.865 101.52 54.135 ;
     RECT  2.16 54.405 41.148 54.675 ;
     RECT  83.052 54.405 101.52 54.675 ;
     RECT  2.16 54.945 41.148 55.215 ;
     RECT  83.052 54.945 101.52 55.215 ;
     RECT  2.16 55.485 41.148 55.755 ;
     RECT  83.052 55.485 101.52 55.755 ;
     RECT  2.16 56.025 41.148 56.295 ;
     RECT  83.052 56.025 101.52 56.295 ;
     RECT  2.16 56.565 41.148 56.835 ;
     RECT  83.052 56.565 101.52 56.835 ;
     RECT  2.16 57.105 41.148 57.375 ;
     RECT  83.052 57.105 101.52 57.375 ;
     RECT  2.16 57.645 41.148 57.915 ;
     RECT  83.052 57.645 101.52 57.915 ;
     RECT  2.16 58.185 41.148 58.455 ;
     RECT  83.052 58.185 101.52 58.455 ;
     RECT  2.16 58.725 41.148 58.995 ;
     RECT  83.052 58.725 101.52 58.995 ;
     RECT  2.16 59.265 41.148 59.535 ;
     RECT  83.052 59.265 101.52 59.535 ;
     RECT  2.16 59.805 41.148 60.075 ;
     RECT  83.052 59.805 101.52 60.075 ;
     RECT  2.16 60.345 41.148 60.615 ;
     RECT  83.052 60.345 101.52 60.615 ;
     RECT  2.16 60.885 41.148 61.155 ;
     RECT  83.052 60.885 101.52 61.155 ;
     RECT  2.16 61.425 41.148 61.695 ;
     RECT  83.052 61.425 101.52 61.695 ;
     RECT  2.16 61.965 41.148 62.235 ;
     RECT  83.052 61.965 101.52 62.235 ;
     RECT  2.16 62.505 41.148 62.775 ;
     RECT  83.052 62.505 101.52 62.775 ;
     RECT  2.16 63.045 41.148 63.315 ;
     RECT  83.052 63.045 101.52 63.315 ;
     RECT  2.16 63.585 41.148 63.855 ;
     RECT  83.052 63.585 101.52 63.855 ;
     RECT  2.16 64.125 41.148 64.395 ;
     RECT  83.052 64.125 101.52 64.395 ;
     RECT  2.16 64.665 41.148 64.935 ;
     RECT  83.052 64.665 101.52 64.935 ;
     RECT  2.16 65.205 41.148 65.475 ;
     RECT  83.052 65.205 101.52 65.475 ;
     RECT  2.16 65.745 41.148 66.015 ;
     RECT  83.052 65.745 101.52 66.015 ;
     RECT  2.16 66.285 41.148 66.555 ;
     RECT  83.052 66.285 101.52 66.555 ;
     RECT  2.16 66.825 41.148 67.095 ;
     RECT  83.052 66.825 101.52 67.095 ;
     RECT  2.16 67.365 41.148 67.635 ;
     RECT  83.052 67.365 101.52 67.635 ;
     RECT  2.16 67.905 41.148 68.175 ;
     RECT  83.052 67.905 101.52 68.175 ;
     RECT  2.16 68.445 41.148 68.715 ;
     RECT  83.052 68.445 101.52 68.715 ;
     RECT  2.16 68.985 41.148 69.12 ;
     RECT  83.052 68.985 101.52 69.12 ;
    LAYER RVTP ;
     RECT  2.16 2.295 101.52 2.565 ;
     RECT  2.16 2.835 101.52 3.105 ;
     RECT  2.16 3.375 101.52 3.645 ;
     RECT  2.16 3.915 101.52 4.185 ;
     RECT  2.16 4.455 101.52 4.725 ;
     RECT  2.16 4.995 101.52 5.265 ;
     RECT  2.16 5.535 101.52 5.805 ;
     RECT  2.16 6.075 101.52 6.345 ;
     RECT  2.16 6.615 101.52 6.885 ;
     RECT  2.16 7.155 101.52 7.425 ;
     RECT  2.16 7.695 101.52 7.965 ;
     RECT  2.16 8.235 101.52 8.505 ;
     RECT  2.16 8.775 101.52 9.045 ;
     RECT  2.16 9.315 101.52 9.585 ;
     RECT  2.16 9.855 101.52 10.125 ;
     RECT  2.16 10.395 101.52 10.665 ;
     RECT  2.16 10.935 101.52 11.205 ;
     RECT  2.16 11.475 101.52 11.745 ;
     RECT  2.16 12.015 101.52 12.285 ;
     RECT  2.16 12.555 101.52 12.825 ;
     RECT  2.16 13.095 101.52 13.365 ;
     RECT  2.16 13.635 101.52 13.905 ;
     RECT  2.16 14.175 101.52 14.445 ;
     RECT  2.16 14.715 101.52 14.985 ;
     RECT  2.16 15.255 101.52 15.525 ;
     RECT  2.16 15.795 101.52 16.065 ;
     RECT  2.16 16.335 101.52 16.605 ;
     RECT  2.16 16.875 101.52 17.145 ;
     RECT  2.16 17.415 101.52 17.685 ;
     RECT  2.16 17.955 101.52 18.225 ;
     RECT  2.16 18.495 101.52 18.765 ;
     RECT  2.16 19.035 101.52 19.305 ;
     RECT  2.16 19.575 101.52 19.845 ;
     RECT  2.16 20.115 101.52 20.385 ;
     RECT  2.16 20.655 101.52 20.925 ;
     RECT  2.16 21.195 101.52 21.465 ;
     RECT  2.16 21.735 101.52 22.005 ;
     RECT  2.16 22.275 101.52 22.545 ;
     RECT  2.16 22.815 101.52 23.085 ;
     RECT  2.16 23.355 101.52 23.625 ;
     RECT  2.16 23.895 101.52 24.165 ;
     RECT  2.16 24.435 101.52 24.705 ;
     RECT  2.16 24.975 101.52 25.245 ;
     RECT  2.16 25.515 101.52 25.785 ;
     RECT  2.16 26.055 101.52 26.325 ;
     RECT  2.16 26.595 101.52 26.865 ;
     RECT  2.16 27.135 101.52 27.405 ;
     RECT  2.16 27.675 101.52 27.945 ;
     RECT  2.16 28.215 101.52 28.485 ;
     RECT  2.16 28.755 101.52 29.025 ;
     RECT  2.16 29.295 101.52 29.565 ;
     RECT  2.16 29.835 101.52 30.105 ;
     RECT  2.16 30.375 101.52 30.645 ;
     RECT  2.16 30.915 101.52 31.185 ;
     RECT  2.16 31.455 101.52 31.725 ;
     RECT  2.16 31.995 101.52 32.265 ;
     RECT  2.16 32.535 101.52 32.805 ;
     RECT  2.16 33.075 101.52 33.345 ;
     RECT  2.16 33.615 101.52 33.885 ;
     RECT  2.16 34.155 101.52 34.425 ;
     RECT  2.16 34.695 101.52 34.965 ;
     RECT  2.16 35.235 101.52 35.505 ;
     RECT  2.16 35.775 101.52 36.045 ;
     RECT  2.16 36.315 101.52 36.585 ;
     RECT  2.16 36.855 101.52 37.125 ;
     RECT  2.16 37.395 101.52 37.665 ;
     RECT  2.16 37.935 101.52 38.205 ;
     RECT  2.16 38.475 101.52 38.745 ;
     RECT  2.16 39.015 101.52 39.285 ;
     RECT  2.16 39.555 101.52 39.825 ;
     RECT  2.16 40.095 101.52 40.365 ;
     RECT  2.16 40.635 101.52 40.905 ;
     RECT  2.16 41.175 41.148 41.445 ;
     RECT  83.052 41.175 101.52 41.445 ;
     RECT  2.16 41.715 41.148 41.985 ;
     RECT  83.052 41.715 101.52 41.985 ;
     RECT  2.16 42.255 41.148 42.525 ;
     RECT  83.052 42.255 101.52 42.525 ;
     RECT  2.16 42.795 41.148 43.065 ;
     RECT  83.052 42.795 101.52 43.065 ;
     RECT  2.16 43.335 41.148 43.605 ;
     RECT  83.052 43.335 101.52 43.605 ;
     RECT  2.16 43.875 41.148 44.145 ;
     RECT  83.052 43.875 101.52 44.145 ;
     RECT  2.16 44.415 41.148 44.685 ;
     RECT  83.052 44.415 101.52 44.685 ;
     RECT  2.16 44.955 41.148 45.225 ;
     RECT  83.052 44.955 101.52 45.225 ;
     RECT  2.16 45.495 41.148 45.765 ;
     RECT  83.052 45.495 101.52 45.765 ;
     RECT  2.16 46.035 41.148 46.305 ;
     RECT  83.052 46.035 101.52 46.305 ;
     RECT  2.16 46.575 41.148 46.845 ;
     RECT  83.052 46.575 101.52 46.845 ;
     RECT  2.16 47.115 41.148 47.385 ;
     RECT  83.052 47.115 101.52 47.385 ;
     RECT  2.16 47.655 41.148 47.925 ;
     RECT  83.052 47.655 101.52 47.925 ;
     RECT  2.16 48.195 41.148 48.465 ;
     RECT  83.052 48.195 101.52 48.465 ;
     RECT  2.16 48.735 41.148 49.005 ;
     RECT  83.052 48.735 101.52 49.005 ;
     RECT  2.16 49.275 41.148 49.545 ;
     RECT  83.052 49.275 101.52 49.545 ;
     RECT  2.16 49.815 41.148 50.085 ;
     RECT  83.052 49.815 101.52 50.085 ;
     RECT  2.16 50.355 41.148 50.625 ;
     RECT  83.052 50.355 101.52 50.625 ;
     RECT  2.16 50.895 41.148 51.165 ;
     RECT  83.052 50.895 101.52 51.165 ;
     RECT  2.16 51.435 41.148 51.705 ;
     RECT  83.052 51.435 101.52 51.705 ;
     RECT  2.16 51.975 41.148 52.245 ;
     RECT  83.052 51.975 101.52 52.245 ;
     RECT  2.16 52.515 41.148 52.785 ;
     RECT  83.052 52.515 101.52 52.785 ;
     RECT  2.16 53.055 41.148 53.325 ;
     RECT  83.052 53.055 101.52 53.325 ;
     RECT  2.16 53.595 41.148 53.865 ;
     RECT  83.052 53.595 101.52 53.865 ;
     RECT  2.16 54.135 41.148 54.405 ;
     RECT  83.052 54.135 101.52 54.405 ;
     RECT  2.16 54.675 41.148 54.945 ;
     RECT  83.052 54.675 101.52 54.945 ;
     RECT  2.16 55.215 41.148 55.485 ;
     RECT  83.052 55.215 101.52 55.485 ;
     RECT  2.16 55.755 41.148 56.025 ;
     RECT  83.052 55.755 101.52 56.025 ;
     RECT  2.16 56.295 41.148 56.565 ;
     RECT  83.052 56.295 101.52 56.565 ;
     RECT  2.16 56.835 41.148 57.105 ;
     RECT  83.052 56.835 101.52 57.105 ;
     RECT  2.16 57.375 41.148 57.645 ;
     RECT  83.052 57.375 101.52 57.645 ;
     RECT  2.16 57.915 41.148 58.185 ;
     RECT  83.052 57.915 101.52 58.185 ;
     RECT  2.16 58.455 41.148 58.725 ;
     RECT  83.052 58.455 101.52 58.725 ;
     RECT  2.16 58.995 41.148 59.265 ;
     RECT  83.052 58.995 101.52 59.265 ;
     RECT  2.16 59.535 41.148 59.805 ;
     RECT  83.052 59.535 101.52 59.805 ;
     RECT  2.16 60.075 41.148 60.345 ;
     RECT  83.052 60.075 101.52 60.345 ;
     RECT  2.16 60.615 41.148 60.885 ;
     RECT  83.052 60.615 101.52 60.885 ;
     RECT  2.16 61.155 41.148 61.425 ;
     RECT  83.052 61.155 101.52 61.425 ;
     RECT  2.16 61.695 41.148 61.965 ;
     RECT  83.052 61.695 101.52 61.965 ;
     RECT  2.16 62.235 41.148 62.505 ;
     RECT  83.052 62.235 101.52 62.505 ;
     RECT  2.16 62.775 41.148 63.045 ;
     RECT  83.052 62.775 101.52 63.045 ;
     RECT  2.16 63.315 41.148 63.585 ;
     RECT  83.052 63.315 101.52 63.585 ;
     RECT  2.16 63.855 41.148 64.125 ;
     RECT  83.052 63.855 101.52 64.125 ;
     RECT  2.16 64.395 41.148 64.665 ;
     RECT  83.052 64.395 101.52 64.665 ;
     RECT  2.16 64.935 41.148 65.205 ;
     RECT  83.052 64.935 101.52 65.205 ;
     RECT  2.16 65.475 41.148 65.745 ;
     RECT  83.052 65.475 101.52 65.745 ;
     RECT  2.16 66.015 41.148 66.285 ;
     RECT  83.052 66.015 101.52 66.285 ;
     RECT  2.16 66.555 41.148 66.825 ;
     RECT  83.052 66.555 101.52 66.825 ;
     RECT  2.16 67.095 41.148 67.365 ;
     RECT  83.052 67.095 101.52 67.365 ;
     RECT  2.16 67.635 41.148 67.905 ;
     RECT  83.052 67.635 101.52 67.905 ;
     RECT  2.16 68.175 41.148 68.445 ;
     RECT  83.052 68.175 101.52 68.445 ;
     RECT  2.16 68.715 41.148 68.985 ;
     RECT  83.052 68.715 101.52 68.985 ;
    LAYER M1 ;
     RECT  2.16 2.151 101.52 41.049 ;
     RECT  43.2 43.2 81 66.984 ;
     RECT  2.16 41.049 41.148 69.129 ;
     RECT  83.052 41.049 101.52 69.129 ;
    LAYER M2 ;
     RECT  1.111 3.042 1.363 3.06 ;
     RECT  1.363 3.042 1.615 3.132 ;
     RECT  1.615 2.772 1.867 3.132 ;
     RECT  1.867 2.772 2.16 3.33 ;
     RECT  0.103 7.902 2.16 7.92 ;
     RECT  0.103 21.78 2.16 21.798 ;
     RECT  0.535 35.55 2.16 35.568 ;
     RECT  0.103 49.482 2.16 49.5 ;
     RECT  4.639 0.036 4.703 0.054 ;
     RECT  20.983 0.036 21.083 0.054 ;
     RECT  21.811 0.036 22.127 0.054 ;
     RECT  22.099 1.152 22.199 1.17 ;
     RECT  24.115 0.036 24.215 0.054 ;
     RECT  28.975 1.152 29.075 1.17 ;
     RECT  34.771 0.036 34.871 0.054 ;
     RECT  35.599 1.152 35.699 1.17 ;
     RECT  2.16 2.151 36.031 69.129 ;
     RECT  36.031 2.106 38.219 69.129 ;
     RECT  38.219 2.151 39.955 69.129 ;
     RECT  39.955 1.728 40.127 69.129 ;
     RECT  40.207 0.036 40.559 0.054 ;
     RECT  40.127 2.151 41.148 69.129 ;
     RECT  41.148 48.78 41.603 61.11 ;
     RECT  41.148 62.172 41.603 66.51 ;
     RECT  41.603 48.78 41.639 50.148 ;
     RECT  41.603 54.036 41.639 58.644 ;
     RECT  41.603 59.706 41.711 61.11 ;
     RECT  41.639 49.32 42.179 50.148 ;
     RECT  41.603 51.102 42.179 53.28 ;
     RECT  41.639 54.036 42.179 56.862 ;
     RECT  41.711 59.706 42.179 60.336 ;
     RECT  41.603 62.172 42.179 63.27 ;
     RECT  41.603 64.098 42.179 64.89 ;
     RECT  41.148 45.306 42.215 45.324 ;
     RECT  42.179 55.116 42.215 56.124 ;
     RECT  41.639 57.816 42.215 58.644 ;
     RECT  42.179 60.318 42.215 60.336 ;
     RECT  42.179 62.172 42.215 63.072 ;
     RECT  42.215 55.8 42.251 55.818 ;
     RECT  41.148 42.462 42.467 43.398 ;
     RECT  42.467 42.462 43.2 43.29 ;
     RECT  42.179 50.13 43.2 50.148 ;
     RECT  42.179 51.336 43.2 53.28 ;
     RECT  42.215 57.816 43.2 57.834 ;
     RECT  41.711 61.092 43.2 61.11 ;
     RECT  42.215 62.172 43.2 62.73 ;
     RECT  42.179 64.098 43.2 64.116 ;
     RECT  41.603 65.646 43.2 66.51 ;
     RECT  41.148 2.151 43.987 41.049 ;
     RECT  43.987 2.106 45.167 41.049 ;
     RECT  50.971 0.036 51.215 0.054 ;
     RECT  45.167 2.151 51.331 41.049 ;
     RECT  51.331 1.728 51.467 41.049 ;
     RECT  51.619 1.152 51.827 1.17 ;
     RECT  51.467 2.151 55.543 41.049 ;
     RECT  55.543 1.728 55.679 41.049 ;
     RECT  55.679 2.151 56.803 41.049 ;
     RECT  56.803 1.728 56.975 41.049 ;
     RECT  56.975 2.151 60.007 41.049 ;
     RECT  60.007 2.106 61.043 41.049 ;
     RECT  61.043 2.151 66.019 41.049 ;
     RECT  66.019 2.106 67.091 41.049 ;
     RECT  67.279 0.036 67.379 0.054 ;
     RECT  67.091 2.151 69.331 41.049 ;
     RECT  69.331 1.728 69.503 41.049 ;
     RECT  69.503 2.151 70.591 41.049 ;
     RECT  70.591 2.106 71.447 41.049 ;
     RECT  72.571 0.036 72.671 0.054 ;
     RECT  74.407 0.036 74.471 0.054 ;
     RECT  77.287 0.036 78.979 0.054 ;
     RECT  78.979 0.036 80.347 0.09 ;
     RECT  43.2 42.462 81 66.984 ;
     RECT  71.447 2.151 81.355 41.049 ;
     RECT  81.355 2.151 82.039 41.634 ;
     RECT  81 43.848 82.075 43.866 ;
     RECT  82.039 2.106 82.103 41.634 ;
     RECT  81 42.462 82.147 42.516 ;
     RECT  82.075 43.344 82.651 43.866 ;
     RECT  82.651 65.142 82.687 65.16 ;
     RECT  82.651 65.916 82.687 65.934 ;
     RECT  82.687 65.142 82.723 65.934 ;
     RECT  82.651 47.286 82.903 47.304 ;
     RECT  82.939 45.738 83.011 45.756 ;
     RECT  82.103 2.106 83.039 41.049 ;
     RECT  83.039 2.151 83.052 41.049 ;
     RECT  82.147 41.886 83.052 42.516 ;
     RECT  82.651 43.344 83.052 44.37 ;
     RECT  83.011 45.738 83.052 45.99 ;
     RECT  82.903 47.124 83.052 47.304 ;
     RECT  82.651 61.056 83.052 61.074 ;
     RECT  82.651 62.136 83.052 62.694 ;
     RECT  82.723 65.142 83.052 66.474 ;
     RECT  80.347 0.036 83.083 0.162 ;
     RECT  83.083 0.036 83.975 0.594 ;
     RECT  83.052 2.151 84.055 69.129 ;
     RECT  84.055 2.106 84.335 69.129 ;
     RECT  83.975 0.576 84.443 0.594 ;
     RECT  85.423 0.036 85.819 0.054 ;
     RECT  85.819 0.036 85.955 0.09 ;
     RECT  84.335 2.151 87.583 69.129 ;
     RECT  86.791 1.152 88.511 1.17 ;
     RECT  85.955 0.036 88.735 0.054 ;
     RECT  88.735 0.036 89.339 0.666 ;
     RECT  89.339 0.036 90.383 0.126 ;
     RECT  90.383 0.108 90.527 0.126 ;
     RECT  90.535 0.576 90.851 0.594 ;
     RECT  87.583 2.106 92.075 69.129 ;
     RECT  92.075 2.151 96.979 69.129 ;
     RECT  96.979 2.106 97.439 69.129 ;
     RECT  97.699 1.152 97.799 1.17 ;
     RECT  99.571 0.036 100.535 0.054 ;
     RECT  97.439 2.151 101.52 69.129 ;
     RECT  101.52 2.34 101.795 3.06 ;
     RECT  101.52 54.918 101.939 54.936 ;
     RECT  101.52 9.018 102.011 9.036 ;
     RECT  101.52 15.228 102.011 15.246 ;
     RECT  101.52 28.962 102.011 28.98 ;
     RECT  101.52 30.042 102.011 30.06 ;
     RECT  101.52 32.742 102.011 32.76 ;
     RECT  101.52 37.602 102.011 37.62 ;
     RECT  101.52 40.032 102.011 40.05 ;
     RECT  101.52 44.928 102.011 44.946 ;
     RECT  101.52 47.394 102.011 47.412 ;
     RECT  101.52 57.348 102.011 57.366 ;
     RECT  101.52 59.742 102.011 59.76 ;
     RECT  101.52 63.522 102.011 63.54 ;
     RECT  101.52 5.58 102.047 5.679 ;
     RECT  101.52 7.596 102.047 7.614 ;
     RECT  101.52 10.44 102.047 10.458 ;
     RECT  101.52 11.79 102.047 11.808 ;
     RECT  101.52 13.842 102.047 13.86 ;
     RECT  101.52 16.65 102.047 16.668 ;
     RECT  101.52 27.72 102.047 27.738 ;
     RECT  101.795 2.34 102.119 2.898 ;
     RECT  102.047 5.661 102.119 5.679 ;
     RECT  102.119 2.34 102.299 2.556 ;
     RECT  101.52 4.698 102.515 4.716 ;
     RECT  101.52 12.798 102.515 12.816 ;
     RECT  101.52 43.848 102.515 43.866 ;
     RECT  102.299 2.34 102.551 2.358 ;
     RECT  101.52 6.588 102.587 6.606 ;
     RECT  101.52 17.892 102.587 17.91 ;
     RECT  101.52 18.972 102.587 18.99 ;
     RECT  101.52 21.402 102.587 21.42 ;
     RECT  101.52 23.832 102.587 23.85 ;
     RECT  101.52 25.182 102.587 25.2 ;
     RECT  101.52 26.532 102.587 26.55 ;
     RECT  101.52 35.172 102.587 35.19 ;
     RECT  101.52 36.252 102.587 36.27 ;
     RECT  101.52 41.382 102.587 41.4 ;
     RECT  101.52 42.462 102.587 42.48 ;
     RECT  101.52 46.242 102.587 46.26 ;
     RECT  101.52 48.672 102.587 48.69 ;
     RECT  101.52 51.102 102.587 51.12 ;
     RECT  101.52 53.568 102.587 53.586 ;
     RECT  101.52 55.962 102.587 55.98 ;
     RECT  101.52 58.392 102.587 58.41 ;
     RECT  101.52 62.172 102.587 62.19 ;
     RECT  101.52 64.872 102.587 64.89 ;
     RECT  101.52 65.952 102.587 65.97 ;
     RECT  101.52 60.822 102.623 60.84 ;
     RECT  101.52 68.382 102.623 68.4 ;
     RECT  101.52 20.628 103.595 20.646 ;
     RECT  101.52 31.392 103.595 31.41 ;
     RECT  101.52 52.452 103.595 52.47 ;
     RECT  101.52 67.338 103.595 67.356 ;
    LAYER M3 ;
     RECT  82.872 0.012 90.81 0.059 ;
     RECT  99.216 0.012 102.546 0.091 ;
     RECT  95.976 0.091 96.534 0.475 ;
     RECT  29.592 0.091 29.61 0.523 ;
     RECT  83.088 0.059 90.81 0.523 ;
     RECT  95.976 0.475 96.75 0.523 ;
     RECT  97.704 0.091 102.546 0.523 ;
     RECT  61.956 0.091 61.974 0.571 ;
     RECT  77.292 0.031 77.31 0.571 ;
     RECT  93.384 0.091 94.734 0.571 ;
     RECT  95.976 0.523 102.546 0.571 ;
     RECT  17.46 0.012 25.398 1.147 ;
     RECT  29.052 0.523 29.61 1.147 ;
     RECT  33.804 0.012 41.742 1.147 ;
     RECT  43.812 0.571 43.83 1.147 ;
     RECT  50.184 0.012 58.122 1.147 ;
     RECT  61.956 0.571 63.234 1.147 ;
     RECT  78.984 0.067 79.002 1.147 ;
     RECT  83.088 0.523 91.53 1.147 ;
     RECT  92.808 0.571 102.546 1.147 ;
     RECT  82.8 1.147 91.53 1.175 ;
     RECT  28.548 1.147 29.61 1.675 ;
     RECT  1.116 0.012 9.054 1.723 ;
     RECT  10.62 0.571 10.638 1.723 ;
     RECT  11.592 1.147 12.294 1.723 ;
     RECT  14.184 0.571 14.202 1.723 ;
     RECT  16.56 1.147 25.398 1.723 ;
     RECT  26.172 0.571 26.19 1.723 ;
     RECT  28.548 1.675 29.754 1.723 ;
     RECT  31.284 0.571 31.302 1.723 ;
     RECT  32.472 0.571 32.49 1.723 ;
     RECT  33.732 1.147 41.742 1.723 ;
     RECT  42.588 0.571 42.606 1.723 ;
     RECT  43.812 1.147 44.37 1.723 ;
     RECT  45.756 1.675 45.774 1.723 ;
     RECT  47.376 1.147 47.934 1.723 ;
     RECT  49.536 1.147 58.122 1.723 ;
     RECT  61.956 1.147 63.918 1.723 ;
     RECT  65.628 1.147 65.646 1.723 ;
     RECT  66.528 0.012 74.466 1.723 ;
     RECT  76.284 0.571 77.526 1.723 ;
     RECT  78.66 1.147 79.002 1.723 ;
     RECT  80.352 0.139 80.37 1.723 ;
     RECT  81.108 0.091 81.126 1.723 ;
     RECT  82.008 0.571 82.026 1.723 ;
     RECT  82.8 1.175 88.326 1.723 ;
     RECT  89.136 1.175 91.53 1.723 ;
     RECT  49.5 1.723 60.21 1.771 ;
     RECT  60.984 1.723 88.326 1.771 ;
     RECT  89.136 1.723 91.962 2.101 ;
     RECT  92.7 1.147 102.546 2.101 ;
     RECT  49.5 1.771 88.326 2.143 ;
     RECT  89.136 2.101 102.546 2.143 ;
     RECT  1.116 1.723 25.398 2.191 ;
     RECT  26.172 1.723 48.582 2.191 ;
     RECT  49.5 2.143 102.546 2.191 ;
     RECT  1.116 2.191 48.582 2.263 ;
     RECT  49.356 2.191 102.546 2.263 ;
     RECT  1.116 2.263 102.546 2.363 ;
     RECT  1.116 2.363 102.294 2.561 ;
     RECT  1.116 2.561 102.114 3.065 ;
     RECT  1.368 3.065 102.114 3.137 ;
     RECT  1.872 3.137 102.114 3.335 ;
     RECT  2.268 3.335 102.114 3.569 ;
     RECT  102.096 3.569 102.114 4.075 ;
     RECT  102.096 4.075 102.51 4.721 ;
     RECT  2.268 3.569 101.286 4.955 ;
     RECT  102.096 4.721 102.114 5.323 ;
     RECT  102.024 5.323 102.114 5.684 ;
     RECT  2.268 4.955 79.434 5.701 ;
     RECT  2.268 5.701 79.47 5.765 ;
     RECT  80.316 4.955 101.286 5.789 ;
     RECT  2.304 5.765 79.47 5.809 ;
     RECT  80.316 5.789 101.25 5.809 ;
     RECT  2.304 5.809 101.25 5.909 ;
     RECT  2.376 5.909 101.25 5.999 ;
     RECT  102.024 5.684 102.042 6.571 ;
     RECT  102.024 6.571 102.582 6.611 ;
     RECT  2.376 5.999 101.214 6.925 ;
     RECT  2.34 6.925 101.25 7.421 ;
     RECT  2.415 7.421 101.25 7.501 ;
     RECT  102.024 6.611 102.042 7.501 ;
     RECT  2.415 7.501 102.042 7.619 ;
     RECT  0.108 7.897 0.126 7.949 ;
     RECT  2.415 7.619 101.394 8.539 ;
     RECT  2.376 8.539 101.394 8.969 ;
     RECT  101.052 8.969 101.394 9.013 ;
     RECT  101.052 9.013 102.006 9.053 ;
     RECT  66.24 8.969 100.314 9.113 ;
     RECT  101.052 9.053 101.394 9.419 ;
     RECT  66.24 9.113 99.897 9.581 ;
     RECT  77.436 9.581 99.897 9.677 ;
     RECT  2.376 8.969 65.466 9.787 ;
     RECT  66.24 9.581 76.662 9.787 ;
     RECT  102.024 10.267 102.042 10.463 ;
     RECT  2.376 9.787 76.662 10.471 ;
     RECT  77.436 9.677 98.874 10.471 ;
     RECT  2.376 10.471 98.874 10.625 ;
     RECT  2.376 10.625 75.006 10.697 ;
     RECT  2.376 10.697 74.934 10.733 ;
     RECT  99.615 9.677 99.897 11.173 ;
     RECT  101.052 9.419 101.07 11.173 ;
     RECT  2.376 10.733 74.682 11.209 ;
     RECT  75.78 10.625 98.874 11.245 ;
     RECT  99.615 11.173 101.07 11.245 ;
     RECT  2.34 11.209 74.682 11.261 ;
     RECT  75.78 11.245 101.07 11.479 ;
     RECT  2.415 11.261 74.682 11.512 ;
     RECT  75.564 11.479 101.07 11.512 ;
     RECT  102.024 11.515 102.042 11.813 ;
     RECT  2.415 11.512 101.07 11.821 ;
     RECT  2.415 11.821 101.106 11.939 ;
     RECT  2.415 11.939 101.07 12.389 ;
     RECT  2.415 12.389 100.71 12.715 ;
     RECT  2.376 12.715 100.71 12.755 ;
     RECT  102.492 12.715 102.51 12.821 ;
     RECT  2.415 12.755 100.71 13.055 ;
     RECT  3.564 13.055 100.71 13.667 ;
     RECT  3.564 13.667 100.602 13.829 ;
     RECT  102.024 13.837 102.042 13.997 ;
     RECT  2.415 13.055 2.697 14.071 ;
     RECT  3.564 13.829 15.606 14.071 ;
     RECT  2.415 14.071 15.606 14.203 ;
     RECT  2.34 14.203 15.606 14.243 ;
     RECT  2.415 14.243 15.606 14.683 ;
     RECT  16.344 13.829 100.602 14.683 ;
     RECT  101.988 15.211 102.006 15.251 ;
     RECT  2.415 14.683 100.602 16.363 ;
     RECT  2.376 16.363 100.602 16.529 ;
     RECT  102.024 16.459 102.042 16.673 ;
     RECT  2.415 16.529 100.602 17.117 ;
     RECT  3.42 17.117 100.602 17.609 ;
     RECT  3.42 17.609 3.438 17.645 ;
     RECT  4.176 17.609 100.602 17.645 ;
     RECT  4.392 17.645 100.602 17.789 ;
     RECT  102.564 17.707 102.582 17.915 ;
     RECT  4.608 17.789 100.602 17.951 ;
     RECT  5.184 17.951 100.602 18.031 ;
     RECT  5.184 18.031 101.106 18.149 ;
     RECT  5.184 18.149 100.386 18.419 ;
     RECT  5.184 18.419 100.35 18.563 ;
     RECT  5.184 18.563 100.242 18.811 ;
     RECT  4.464 18.811 100.242 18.995 ;
     RECT  102.564 18.907 102.582 18.995 ;
     RECT  5.148 18.995 100.242 19.741 ;
     RECT  5.112 19.741 100.242 19.777 ;
     RECT  5.112 19.777 100.386 19.849 ;
     RECT  5.04 19.849 100.386 19.885 ;
     RECT  5.04 19.885 100.71 20.281 ;
     RECT  103.572 20.155 103.59 20.651 ;
     RECT  5.04 20.281 100.854 20.731 ;
     RECT  4.032 20.047 4.05 21.091 ;
     RECT  4.932 20.731 100.854 21.091 ;
     RECT  4.032 21.091 100.854 21.199 ;
     RECT  3.6 21.199 100.854 21.271 ;
     RECT  3.6 21.271 100.926 21.389 ;
     RECT  102.564 21.397 102.582 21.437 ;
     RECT  0.108 21.775 0.126 21.821 ;
     RECT  3.6 21.389 100.782 22.073 ;
     RECT  101.448 22.651 101.466 22.775 ;
     RECT  3.6 22.073 100.242 23.125 ;
     RECT  3.6 23.125 100.53 23.665 ;
     RECT  3.6 23.665 100.566 23.701 ;
     RECT  3.564 23.701 100.566 23.819 ;
     RECT  102.564 23.827 102.582 23.885 ;
     RECT  3.564 23.819 100.242 23.933 ;
     RECT  4.032 23.933 100.242 24.509 ;
     RECT  55.944 24.509 100.242 24.745 ;
     RECT  102.564 25.099 102.582 25.205 ;
     RECT  4.032 24.509 55.206 25.321 ;
     RECT  55.944 24.745 100.278 25.321 ;
     RECT  4.032 25.321 100.278 25.519 ;
     RECT  4.032 25.519 100.386 25.591 ;
     RECT  4.032 25.591 100.602 25.853 ;
     RECT  4.248 25.853 100.602 25.861 ;
     RECT  4.248 25.861 100.746 26.285 ;
     RECT  4.248 26.285 100.602 26.519 ;
     RECT  102.564 26.347 102.582 26.555 ;
     RECT  4.464 26.519 100.314 27.095 ;
     RECT  101.124 27.163 101.142 27.329 ;
     RECT  5.04 27.095 100.314 27.473 ;
     RECT  101.088 27.481 101.106 27.599 ;
     RECT  102.024 27.595 102.042 27.743 ;
     RECT  5.04 27.473 100.17 28.409 ;
     RECT  5.04 28.409 100.062 28.949 ;
     RECT  101.988 28.843 102.006 28.985 ;
     RECT  5.04 28.949 70.038 29.101 ;
     RECT  70.848 28.949 100.062 29.227 ;
     RECT  70.848 29.227 100.098 29.371 ;
     RECT  4.932 29.101 70.038 29.605 ;
     RECT  70.848 29.371 100.278 29.605 ;
     RECT  4.896 29.605 70.038 29.645 ;
     RECT  101.988 30.037 102.006 30.077 ;
     RECT  70.848 29.605 100.422 30.109 ;
     RECT  70.776 30.109 100.422 30.181 ;
     RECT  70.776 30.181 100.89 30.299 ;
     RECT  5.148 29.645 70.038 30.605 ;
     RECT  70.776 30.299 100.494 30.605 ;
     RECT  99.615 30.605 100.494 30.677 ;
     RECT  70.776 30.605 98.874 30.875 ;
     RECT  70.776 30.875 97.398 31.339 ;
     RECT  103.572 31.291 103.59 31.415 ;
     RECT  99.615 30.677 99.897 31.459 ;
     RECT  5.148 30.605 69.75 31.495 ;
     RECT  4.788 31.495 69.75 31.531 ;
     RECT  70.704 31.339 97.398 31.531 ;
     RECT  98.28 30.875 98.874 31.531 ;
     RECT  99.615 31.459 99.954 31.531 ;
     RECT  4.788 31.531 97.398 31.621 ;
     RECT  98.28 31.531 100.566 31.621 ;
     RECT  4.788 31.621 100.566 31.685 ;
     RECT  4.788 31.685 69.75 31.757 ;
     RECT  70.596 31.685 100.314 31.757 ;
     RECT  70.596 31.757 99.954 31.805 ;
     RECT  4.788 31.757 69.462 31.901 ;
     RECT  79.524 31.805 99.954 31.919 ;
     RECT  79.524 31.919 94.806 31.955 ;
     RECT  95.544 31.919 99.954 32.189 ;
     RECT  95.544 32.189 97.47 32.225 ;
     RECT  79.524 31.955 94.497 32.495 ;
     RECT  5.148 31.901 69.462 32.503 ;
     RECT  95.544 32.225 97.398 32.531 ;
     RECT  70.596 31.805 78.714 32.533 ;
     RECT  79.524 32.495 93.222 32.533 ;
     RECT  5.148 32.503 69.858 32.575 ;
     RECT  70.596 32.533 93.222 32.575 ;
     RECT  5.148 32.575 93.222 32.603 ;
     RECT  5.364 32.603 93.222 32.729 ;
     RECT  5.364 32.729 5.454 32.765 ;
     RECT  101.988 32.539 102.006 32.765 ;
     RECT  5.364 32.765 5.382 32.873 ;
     RECT  98.244 32.189 99.954 32.881 ;
     RECT  6.3 32.729 93.222 32.909 ;
     RECT  95.976 32.531 97.398 32.971 ;
     RECT  98.244 32.881 100.17 32.971 ;
     RECT  6.372 32.909 93.222 32.999 ;
     RECT  6.372 32.999 63.27 33.035 ;
     RECT  95.976 32.971 100.35 33.053 ;
     RECT  64.08 32.999 93.222 33.179 ;
     RECT  95.976 33.053 99.954 33.179 ;
     RECT  64.08 33.179 78.297 33.245 ;
     RECT  95.976 33.179 99.897 33.259 ;
     RECT  79.128 33.179 93.222 33.269 ;
     RECT  64.08 33.245 71.874 33.305 ;
     RECT  79.128 33.269 91.098 33.305 ;
     RECT  95.76 33.259 99.897 33.305 ;
     RECT  64.26 33.305 71.874 33.413 ;
     RECT  79.56 33.305 90.918 33.413 ;
     RECT  72.615 33.245 78.297 33.449 ;
     RECT  64.26 33.413 71.73 33.539 ;
     RECT  74.664 33.449 78.297 33.539 ;
     RECT  79.56 33.413 90.882 33.539 ;
     RECT  91.836 33.269 93.222 33.539 ;
     RECT  6.516 33.035 63.27 33.575 ;
     RECT  67.215 33.539 67.77 33.575 ;
     RECT  68.508 33.539 71.658 33.575 ;
     RECT  79.56 33.539 90.558 33.575 ;
     RECT  91.836 33.539 91.854 33.575 ;
     RECT  92.592 33.539 92.898 33.575 ;
     RECT  79.56 33.575 82.422 33.581 ;
     RECT  72.615 33.449 73.854 33.611 ;
     RECT  75.456 33.539 78.297 33.611 ;
     RECT  80.1 33.581 82.422 33.611 ;
     RECT  6.516 33.575 58.194 33.629 ;
     RECT  59.04 33.575 63.27 33.629 ;
     RECT  74.664 33.539 74.682 33.629 ;
     RECT  80.244 33.611 82.422 33.629 ;
     RECT  59.04 33.629 62.874 33.719 ;
     RECT  73.8 33.611 73.854 33.809 ;
     RECT  75.96 33.611 78.297 33.809 ;
     RECT  80.964 33.629 82.422 33.809 ;
     RECT  68.508 33.575 71.55 33.832 ;
     RECT  68.508 33.832 70.002 33.845 ;
     RECT  73.8 33.809 73.818 33.845 ;
     RECT  83.376 33.575 89.097 33.845 ;
     RECT  101.448 33.787 101.466 33.845 ;
     RECT  64.332 33.539 66.258 33.953 ;
     RECT  81.108 33.809 82.422 33.953 ;
     RECT  83.376 33.845 87.606 33.953 ;
     RECT  99.615 33.305 99.897 33.961 ;
     RECT  95.76 33.305 98.874 33.965 ;
     RECT  69.372 33.845 70.002 33.989 ;
     RECT  89.892 33.575 90.09 33.989 ;
     RECT  95.94 33.965 98.874 34.013 ;
     RECT  59.04 33.719 62.73 34.079 ;
     RECT  64.62 33.953 66.258 34.079 ;
     RECT  68.508 33.845 68.634 34.079 ;
     RECT  69.84 33.989 70.002 34.079 ;
     RECT  71.244 33.832 71.55 34.079 ;
     RECT  75.96 33.809 76.842 34.079 ;
     RECT  64.62 34.079 65.322 34.115 ;
     RECT  68.508 34.079 68.526 34.115 ;
     RECT  69.84 34.079 69.858 34.115 ;
     RECT  71.28 34.079 71.55 34.115 ;
     RECT  75.96 34.079 75.978 34.115 ;
     RECT  81.36 33.953 82.422 34.151 ;
     RECT  61.815 34.079 62.73 34.187 ;
     RECT  66.096 34.079 66.258 34.187 ;
     RECT  67.215 33.575 67.626 34.187 ;
     RECT  71.532 34.115 71.55 34.187 ;
     RECT  95.976 34.013 98.874 34.187 ;
     RECT  99.615 33.961 99.918 34.195 ;
     RECT  59.04 34.079 60.75 34.205 ;
     RECT  97.164 34.187 98.874 34.223 ;
     RECT  6.588 33.629 58.194 34.321 ;
     RECT  59.04 34.205 60.714 34.321 ;
     RECT  65.052 34.115 65.322 34.349 ;
     RECT  76.716 34.079 76.842 34.349 ;
     RECT  65.304 34.349 65.322 34.355 ;
     RECT  76.716 34.349 76.77 34.385 ;
     RECT  6.588 34.321 60.714 34.397 ;
     RECT  66.096 34.187 66.114 34.397 ;
     RECT  76.716 34.385 76.734 34.397 ;
     RECT  89.892 33.989 89.982 34.493 ;
     RECT  59.76 34.397 60.714 34.529 ;
     RECT  60.048 34.529 60.714 34.655 ;
     RECT  6.588 34.397 58.878 34.727 ;
     RECT  95.976 34.187 96.426 34.735 ;
     RECT  81.36 34.151 82.386 34.763 ;
     RECT  95.904 34.735 96.426 34.795 ;
     RECT  60.12 34.655 60.714 34.925 ;
     RECT  61.815 34.187 62.226 34.925 ;
     RECT  95.544 34.795 96.426 35.041 ;
     RECT  97.164 34.223 98.298 35.041 ;
     RECT  95.544 35.041 98.298 35.131 ;
     RECT  60.696 34.925 60.714 35.159 ;
     RECT  95.544 35.131 98.622 35.159 ;
     RECT  102.564 34.987 102.582 35.195 ;
     RECT  99.615 34.195 100.314 35.227 ;
     RECT  95.544 35.159 96.894 35.231 ;
     RECT  97.704 35.159 98.622 35.261 ;
     RECT  95.724 35.231 96.894 35.267 ;
     RECT  83.415 33.953 87.606 35.323 ;
     RECT  99.615 35.227 100.386 35.339 ;
     RECT  95.724 35.267 96.282 35.357 ;
     RECT  6.588 34.727 58.554 35.401 ;
     RECT  6.48 35.401 58.554 35.453 ;
     RECT  6.768 35.453 58.554 35.581 ;
     RECT  0.54 35.545 0.558 35.645 ;
     RECT  83.415 35.323 87.75 35.699 ;
     RECT  95.904 35.357 96.282 35.735 ;
     RECT  6.768 35.581 58.59 35.851 ;
     RECT  6.768 35.851 59.022 35.969 ;
     RECT  99.615 35.339 100.314 36.121 ;
     RECT  58.32 35.969 59.022 36.239 ;
     RECT  58.32 36.239 58.914 36.275 ;
     RECT  102.564 36.235 102.582 36.275 ;
     RECT  97.704 35.261 98.298 36.355 ;
     RECT  99.18 36.121 100.314 36.355 ;
     RECT  97.704 36.355 100.314 36.391 ;
     RECT  97.704 36.391 100.566 36.461 ;
     RECT  58.32 36.275 58.338 36.509 ;
     RECT  6.768 35.969 57.366 36.653 ;
     RECT  99.615 36.461 100.566 36.653 ;
     RECT  88.815 33.845 89.097 36.751 ;
     RECT  88.704 36.751 89.097 36.797 ;
     RECT  6.768 36.653 57.33 36.851 ;
     RECT  65.844 36.475 65.862 36.859 ;
     RECT  7.452 36.851 57.33 36.887 ;
     RECT  65.844 36.859 66.186 36.959 ;
     RECT  65.844 36.959 65.862 37.049 ;
     RECT  7.452 36.887 57.258 37.091 ;
     RECT  9.468 37.091 57.258 37.157 ;
     RECT  9.468 37.157 56.697 37.355 ;
     RECT  97.704 36.461 98.298 37.399 ;
     RECT  99.615 36.653 99.897 37.399 ;
     RECT  97.56 37.399 98.298 37.471 ;
     RECT  99.18 37.399 99.897 37.471 ;
     RECT  97.56 37.471 99.897 37.579 ;
     RECT  9.54 37.355 56.697 37.589 ;
     RECT  97.38 37.579 99.897 37.589 ;
     RECT  9.54 37.589 9.558 37.625 ;
     RECT  97.38 37.589 98.334 37.625 ;
     RECT  101.988 37.483 102.006 37.625 ;
     RECT  99.18 37.589 99.897 37.859 ;
     RECT  10.332 37.589 56.697 37.895 ;
     RECT  99.576 37.859 99.897 38.003 ;
     RECT  7.452 37.091 8.586 38.039 ;
     RECT  55.26 37.895 56.697 38.165 ;
     RECT  10.332 37.895 32.85 38.201 ;
     RECT  55.692 38.165 56.697 38.309 ;
     RECT  10.332 38.201 10.422 38.347 ;
     RECT  10.26 38.347 10.422 38.399 ;
     RECT  11.196 38.201 32.85 38.399 ;
     RECT  12.744 38.399 32.85 38.435 ;
     RECT  33.624 37.895 54.09 38.435 ;
     RECT  12.924 38.435 32.85 38.507 ;
     RECT  11.196 38.399 11.97 38.543 ;
     RECT  13.215 38.507 32.85 38.669 ;
     RECT  33.624 38.435 52.398 38.669 ;
     RECT  11.196 38.543 11.718 38.705 ;
     RECT  13.215 38.669 14.022 38.705 ;
     RECT  14.832 38.669 32.85 38.705 ;
     RECT  53.208 38.435 54.09 38.705 ;
     RECT  14.904 38.705 32.85 38.741 ;
     RECT  53.208 38.705 53.874 38.741 ;
     RECT  97.704 37.625 98.334 38.749 ;
     RECT  15.156 38.741 32.85 38.765 ;
     RECT  33.624 38.669 52.362 38.765 ;
     RECT  101.448 38.677 101.466 38.765 ;
     RECT  81.36 34.763 82.314 38.777 ;
     RECT  53.208 38.741 53.802 38.813 ;
     RECT  99.615 38.003 99.897 38.821 ;
     RECT  53.784 38.813 53.802 38.849 ;
     RECT  99.615 38.821 100.458 38.939 ;
     RECT  15.192 38.765 32.85 39.011 ;
     RECT  96.768 38.779 96.786 39.019 ;
     RECT  97.524 38.749 98.334 39.019 ;
     RECT  99.615 38.939 99.897 39.019 ;
     RECT  23.004 39.011 32.85 39.055 ;
     RECT  33.624 38.765 51.714 39.055 ;
     RECT  96.768 39.019 99.897 39.209 ;
     RECT  97.488 39.209 98.802 39.245 ;
     RECT  16.632 39.011 22.158 39.281 ;
     RECT  23.004 39.055 51.714 39.281 ;
     RECT  16.632 39.281 21.978 39.479 ;
     RECT  16.632 39.479 21.798 39.515 ;
     RECT  89.892 34.493 89.91 39.623 ;
     RECT  31.716 39.281 51.714 39.631 ;
     RECT  15.192 39.011 15.462 39.739 ;
     RECT  15.192 39.739 15.714 39.749 ;
     RECT  16.632 39.515 21.762 39.749 ;
     RECT  15.372 39.749 15.714 39.785 ;
     RECT  16.884 39.749 21.006 39.785 ;
     RECT  15.444 39.785 15.462 39.821 ;
     RECT  16.884 39.785 20.79 39.821 ;
     RECT  16.884 39.821 20.718 39.857 ;
     RECT  31.716 39.631 51.858 39.893 ;
     RECT  16.956 39.857 20.718 40.019 ;
     RECT  23.004 39.281 30.798 40.019 ;
     RECT  23.724 40.019 30.798 40.021 ;
     RECT  31.716 39.893 51.498 40.021 ;
     RECT  23.724 40.021 51.498 40.055 ;
     RECT  101.988 39.931 102.006 40.055 ;
     RECT  94.215 32.495 94.497 40.099 ;
     RECT  17.388 40.019 20.718 40.127 ;
     RECT  25.668 40.055 51.498 40.127 ;
     RECT  95.904 35.735 95.922 40.171 ;
     RECT  99.615 39.209 99.897 40.171 ;
     RECT  23.724 40.055 24.534 40.199 ;
     RECT  25.92 40.127 51.297 40.199 ;
     RECT  23.832 40.199 24.297 40.289 ;
     RECT  94.215 40.099 95.13 40.289 ;
     RECT  100.944 40.171 100.962 40.289 ;
     RECT  95.868 40.171 95.922 40.297 ;
     RECT  23.976 40.289 24.297 40.325 ;
     RECT  25.92 40.199 48.762 40.325 ;
     RECT  97.524 39.245 98.334 40.333 ;
     RECT  17.388 40.127 18.897 40.361 ;
     RECT  32.148 40.325 47.214 40.397 ;
     RECT  22.968 40.027 22.986 40.433 ;
     RECT  25.92 40.325 31.374 40.433 ;
     RECT  33.876 40.397 47.214 40.433 ;
     RECT  27.72 40.433 31.374 40.445 ;
     RECT  44.352 40.433 47.214 40.445 ;
     RECT  50.364 40.199 51.297 40.445 ;
     RECT  94.215 40.289 94.986 40.445 ;
     RECT  26.028 40.433 26.91 40.469 ;
     RECT  31.356 40.445 31.374 40.469 ;
     RECT  26.712 40.469 26.91 40.559 ;
     RECT  32.148 40.397 33.102 40.559 ;
     RECT  33.876 40.433 41.202 40.559 ;
     RECT  47.952 40.325 48.762 40.559 ;
     RECT  26.712 40.559 26.802 40.595 ;
     RECT  27.72 40.445 28.062 40.595 ;
     RECT  32.256 40.559 32.922 40.595 ;
     RECT  33.876 40.559 35.298 40.595 ;
     RECT  44.352 40.445 46.782 40.595 ;
     RECT  95.76 40.297 95.922 40.595 ;
     RECT  101.016 40.441 101.034 40.595 ;
     RECT  97.524 40.333 98.442 40.603 ;
     RECT  44.352 40.595 44.37 40.631 ;
     RECT  26.712 40.595 26.73 40.667 ;
     RECT  27.72 40.595 28.026 40.667 ;
     RECT  36.036 40.559 41.202 40.667 ;
     RECT  45.36 40.595 46.782 40.739 ;
     RECT  50.904 40.445 51.297 40.739 ;
     RECT  45.576 40.739 45.897 40.787 ;
     RECT  51.015 40.739 51.297 40.787 ;
     RECT  56.415 38.309 56.697 40.787 ;
     RECT  61.815 34.925 62.097 40.787 ;
     RECT  67.215 34.187 67.497 40.787 ;
     RECT  72.615 33.611 72.897 40.787 ;
     RECT  77.652 33.809 78.297 40.787 ;
     RECT  29.232 40.445 30.474 40.829 ;
     RECT  33.876 40.595 35.097 40.829 ;
     RECT  36.036 40.667 41.058 40.829 ;
     RECT  42.012 40.433 43.542 40.829 ;
     RECT  48.636 40.559 48.762 40.829 ;
     RECT  36.18 40.829 41.058 40.865 ;
     RECT  45.576 40.787 45.705 40.865 ;
     RECT  48.636 40.829 48.654 40.865 ;
     RECT  33.876 40.829 33.966 40.877 ;
     RECT  46.764 40.739 46.782 40.937 ;
     RECT  29.232 40.829 30.258 40.973 ;
     RECT  33.948 40.877 33.966 41.009 ;
     RECT  36.612 40.865 41.058 41.009 ;
     RECT  45.615 40.865 45.705 41.057 ;
     RECT  51.015 40.787 51.105 41.057 ;
     RECT  56.415 40.787 56.505 41.057 ;
     RECT  61.815 40.787 61.905 41.057 ;
     RECT  67.215 40.787 67.305 41.057 ;
     RECT  72.615 40.787 72.705 41.057 ;
     RECT  77.652 40.787 78.105 41.057 ;
     RECT  38.7 41.009 41.058 41.099 ;
     RECT  38.7 41.099 38.718 41.135 ;
     RECT  39.456 41.099 41.058 41.135 ;
     RECT  32.364 40.595 32.382 41.171 ;
     RECT  40.215 41.135 40.914 41.171 ;
     RECT  34.704 40.829 35.097 41.243 ;
     RECT  97.164 40.603 98.442 41.251 ;
     RECT  99.615 40.171 99.954 41.251 ;
     RECT  39.456 41.135 39.474 41.279 ;
     RECT  40.215 41.171 40.806 41.279 ;
     RECT  97.164 41.251 98.694 41.368 ;
     RECT  99.615 41.251 100.314 41.368 ;
     RECT  97.164 41.368 100.314 41.369 ;
     RECT  97.164 41.369 99.954 41.405 ;
     RECT  102.564 41.179 102.582 41.405 ;
     RECT  99.576 41.405 99.954 41.441 ;
     RECT  81.36 38.777 81.378 41.611 ;
     RECT  82.152 38.777 82.314 41.611 ;
     RECT  81.36 41.611 82.314 41.639 ;
     RECT  100.8 41.521 100.818 41.675 ;
     RECT  97.164 41.405 98.694 42.331 ;
     RECT  99.576 41.441 99.897 42.331 ;
     RECT  83.415 35.699 87.606 42.485 ;
     RECT  102.564 42.427 102.582 42.485 ;
     RECT  40.215 41.279 40.497 42.715 ;
     RECT  17.388 40.361 17.406 42.727 ;
     RECT  17.316 42.727 17.406 42.755 ;
     RECT  97.164 42.331 99.897 42.755 ;
     RECT  27.72 40.667 27.738 43.061 ;
     RECT  42.012 40.829 43.146 43.2 ;
     RECT  77.652 41.057 77.67 43.2 ;
     RECT  40.215 42.715 40.662 43.303 ;
     RECT  82.08 41.639 82.314 43.367 ;
     RECT  82.296 43.367 82.314 43.807 ;
     RECT  42.012 43.2 81 43.843 ;
     RECT  82.296 43.807 82.674 43.871 ;
     RECT  102.492 43.675 102.51 43.871 ;
     RECT  36.612 41.009 36.63 43.915 ;
     RECT  97.164 42.755 98.37 43.951 ;
     RECT  99.615 42.755 99.897 43.951 ;
     RECT  82.656 43.871 82.674 43.963 ;
     RECT  83.415 42.485 86.742 43.963 ;
     RECT  97.164 43.951 99.897 44.069 ;
     RECT  97.164 44.069 98.118 44.077 ;
     RECT  36.144 43.915 36.63 44.339 ;
     RECT  82.656 43.963 86.742 44.573 ;
     RECT  97.02 44.077 98.118 44.609 ;
     RECT  95.904 40.595 95.922 44.617 ;
     RECT  95.292 44.617 96.03 44.653 ;
     RECT  95.292 44.653 96.246 44.669 ;
     RECT  40.215 43.303 40.914 44.725 ;
     RECT  21.744 39.749 21.762 44.753 ;
     RECT  99.615 44.069 99.897 44.761 ;
     RECT  36.18 44.339 36.63 44.813 ;
     RECT  95.436 44.669 96.246 44.851 ;
     RECT  95.436 44.851 96.822 44.879 ;
     RECT  97.56 44.609 98.118 44.879 ;
     RECT  95.436 44.879 96.03 44.915 ;
     RECT  99.615 44.761 100.35 44.951 ;
     RECT  42.012 43.843 81.054 44.957 ;
     RECT  101.988 44.923 102.006 44.96 ;
     RECT  95.436 44.915 95.922 44.987 ;
     RECT  99.615 44.951 100.17 45.023 ;
     RECT  42.048 44.957 81.054 45.725 ;
     RECT  83.16 44.573 86.742 45.733 ;
     RECT  40.215 44.725 41.058 45.841 ;
     RECT  99.615 45.023 99.897 45.841 ;
     RECT  36.612 44.813 36.63 45.869 ;
     RECT  97.884 44.879 98.118 45.869 ;
     RECT  42.192 45.725 81.054 45.917 ;
     RECT  99.615 45.841 100.314 46.229 ;
     RECT  99.615 46.229 99.897 46.264 ;
     RECT  102.564 46.123 102.582 46.265 ;
     RECT  17.316 42.755 17.334 46.301 ;
     RECT  42.228 45.917 81.054 46.301 ;
     RECT  99 46.264 99.897 46.301 ;
     RECT  24.015 40.325 24.297 46.363 ;
     RECT  34.815 41.243 35.097 46.363 ;
     RECT  40.215 45.841 41.094 46.363 ;
     RECT  23.904 46.363 24.297 46.409 ;
     RECT  34.704 46.363 35.097 46.409 ;
     RECT  40.104 46.363 41.094 46.409 ;
     RECT  100.764 46.381 100.782 46.535 ;
     RECT  82.944 45.733 86.742 46.615 ;
     RECT  99.18 46.301 99.897 46.679 ;
     RECT  40.215 46.409 41.094 46.685 ;
     RECT  96.804 44.879 96.822 46.747 ;
     RECT  82.944 46.615 86.814 46.849 ;
     RECT  11.7 38.705 11.718 46.877 ;
     RECT  82.944 46.849 86.85 46.921 ;
     RECT  87.588 42.485 87.606 46.921 ;
     RECT  96.804 46.747 97.182 47.011 ;
     RECT  82.944 46.921 87.606 47.039 ;
     RECT  82.944 47.039 87.03 47.119 ;
     RECT  19.62 40.127 20.718 47.213 ;
     RECT  40.215 46.685 40.59 47.261 ;
     RECT  82.908 47.119 87.03 47.281 ;
     RECT  82.656 47.281 87.03 47.309 ;
     RECT  98.1 45.869 98.118 47.317 ;
     RECT  101.988 47.371 102.006 47.417 ;
     RECT  29.232 40.973 29.697 47.453 ;
     RECT  82.656 47.309 86.742 47.453 ;
     RECT  96.804 47.011 97.326 47.461 ;
     RECT  98.1 47.317 98.37 47.461 ;
     RECT  99.615 46.679 99.897 47.461 ;
     RECT  96.804 47.461 99.897 47.579 ;
     RECT  100.836 47.461 100.854 47.579 ;
     RECT  20.016 47.213 20.718 47.645 ;
     RECT  98.172 47.579 99.897 47.687 ;
     RECT  42.444 46.301 81.054 47.707 ;
     RECT  37.512 41.009 37.53 47.741 ;
     RECT  82.908 47.453 86.742 47.759 ;
     RECT  42.444 47.707 81.09 47.837 ;
     RECT  82.908 47.759 86.418 47.849 ;
     RECT  98.172 47.687 98.19 47.849 ;
     RECT  98.964 47.687 99.897 47.885 ;
     RECT  42.444 47.837 81.054 48.029 ;
     RECT  20.016 47.645 20.034 48.361 ;
     RECT  19.872 48.361 20.034 48.389 ;
     RECT  19.872 48.389 19.89 48.413 ;
     RECT  40.215 47.261 40.497 48.433 ;
     RECT  34.815 46.409 35.097 48.523 ;
     RECT  31.32 48.361 31.338 48.541 ;
     RECT  95.904 44.987 95.922 48.541 ;
     RECT  96.804 47.579 97.326 48.541 ;
     RECT  31.248 48.541 31.338 48.557 ;
     RECT  34.704 48.523 35.097 48.569 ;
     RECT  31.248 48.557 31.266 48.659 ;
     RECT  25.992 48.361 26.01 48.695 ;
     RECT  102.564 48.619 102.582 48.695 ;
     RECT  42.588 48.029 81.054 48.797 ;
     RECT  82.908 47.849 86.274 48.803 ;
     RECT  95.904 48.541 97.326 48.805 ;
     RECT  99.615 47.885 99.897 48.811 ;
     RECT  95.796 48.805 97.326 48.845 ;
     RECT  9.9 41.899 9.918 48.929 ;
     RECT  99.615 48.811 100.35 48.965 ;
     RECT  95.94 48.845 97.326 49.001 ;
     RECT  43.092 48.797 81.054 49.051 ;
     RECT  39.6 48.433 40.497 49.085 ;
     RECT  82.908 48.803 86.166 49.085 ;
     RECT  98.136 48.973 98.154 49.109 ;
     RECT  43.092 49.051 81.09 49.181 ;
     RECT  82.908 49.085 86.022 49.199 ;
     RECT  41.616 48.775 41.634 49.315 ;
     RECT  7.815 38.039 8.586 49.351 ;
     RECT  9.36 49.045 9.378 49.351 ;
     RECT  6.516 42.457 6.534 49.441 ;
     RECT  7.815 49.351 9.378 49.469 ;
     RECT  5.868 49.441 6.534 49.477 ;
     RECT  41.616 49.315 42.174 49.477 ;
     RECT  82.908 49.199 85.986 49.505 ;
     RECT  0.108 49.477 0.126 49.517 ;
     RECT  7.815 49.469 9.054 49.541 ;
     RECT  41.58 49.477 42.174 49.565 ;
     RECT  5.868 49.477 6.822 49.739 ;
     RECT  5.868 49.739 6.534 49.775 ;
     RECT  8.82 49.541 9.054 49.775 ;
     RECT  82.908 49.505 85.806 49.775 ;
     RECT  41.616 49.565 42.174 49.949 ;
     RECT  40.215 49.085 40.497 50.017 ;
     RECT  101.448 49.867 101.466 50.045 ;
     RECT  43.2 49.181 81.054 50.125 ;
     RECT  99.615 48.965 99.897 50.125 ;
     RECT  41.616 49.949 41.634 50.141 ;
     RECT  82.908 49.775 85.77 50.153 ;
     RECT  96.12 49.001 97.326 50.161 ;
     RECT  82.908 50.153 85.698 50.279 ;
     RECT  99.615 50.125 100.314 50.279 ;
     RECT  42.732 50.125 81.054 50.333 ;
     RECT  40.215 50.017 40.734 50.395 ;
     RECT  43.2 50.333 81.054 50.395 ;
     RECT  95.652 50.161 97.974 50.395 ;
     RECT  95.508 50.395 97.974 50.431 ;
     RECT  95.508 50.431 98.622 50.432 ;
     RECT  82.908 50.279 85.626 50.459 ;
     RECT  82.908 50.459 84.726 50.549 ;
     RECT  96.12 50.432 98.622 50.549 ;
     RECT  40.215 50.395 41.598 50.585 ;
     RECT  98.172 50.549 98.622 50.657 ;
     RECT  40.215 50.585 41.058 50.717 ;
     RECT  40.215 50.717 40.734 50.909 ;
     RECT  82.908 50.549 84.33 50.909 ;
     RECT  83.415 50.909 84.33 50.957 ;
     RECT  99.615 50.279 99.897 50.971 ;
     RECT  102.564 51.067 102.582 51.125 ;
     RECT  43.2 50.395 81.09 51.163 ;
     RECT  99.576 50.971 99.897 51.169 ;
     RECT  99 51.169 99.897 51.241 ;
     RECT  99 51.241 100.566 51.245 ;
     RECT  43.2 51.163 81.126 51.259 ;
     RECT  43.092 51.259 81.126 51.293 ;
     RECT  99.576 51.245 100.566 51.395 ;
     RECT  99.576 51.395 100.314 51.539 ;
     RECT  41.4 51.451 41.418 51.737 ;
     RECT  40.215 50.909 40.497 52.027 ;
     RECT  96.264 50.549 97.398 52.177 ;
     RECT  98.172 50.657 98.19 52.177 ;
     RECT  99.615 51.539 100.314 52.313 ;
     RECT  96.264 52.177 98.19 52.321 ;
     RECT  96.264 52.321 98.694 52.439 ;
     RECT  40.215 52.027 41.058 52.445 ;
     RECT  103.572 52.315 103.59 52.475 ;
     RECT  42.156 51.067 42.174 52.591 ;
     RECT  43.092 51.293 81 52.591 ;
     RECT  99.615 52.313 99.897 52.591 ;
     RECT  42.156 52.591 81 52.637 ;
     RECT  96.264 52.439 98.262 52.709 ;
     RECT  39.312 52.591 39.33 52.745 ;
     RECT  99.18 52.591 99.897 52.745 ;
     RECT  42.156 52.637 42.174 52.829 ;
     RECT  43.092 52.637 81 53.285 ;
     RECT  96.264 52.709 97.722 53.401 ;
     RECT  101.196 53.401 101.214 53.519 ;
     RECT  95.94 53.401 97.722 53.557 ;
     RECT  95.76 53.557 97.722 53.597 ;
     RECT  102.564 53.563 102.582 53.6 ;
     RECT  41.58 53.371 41.598 53.755 ;
     RECT  98.748 53.401 98.766 53.789 ;
     RECT  41.58 53.755 42.174 53.825 ;
     RECT  99.576 52.745 99.897 53.933 ;
     RECT  40.215 52.445 40.497 54.031 ;
     RECT  40.215 54.031 40.734 54.331 ;
     RECT  95.328 54.139 95.346 54.409 ;
     RECT  96.264 53.597 97.722 54.481 ;
     RECT  98.532 54.409 98.55 54.481 ;
     RECT  95.328 54.409 95.526 54.671 ;
     RECT  96.264 54.481 98.55 54.715 ;
     RECT  96.048 54.715 98.55 54.751 ;
     RECT  101.016 54.571 101.034 54.869 ;
     RECT  96.048 54.751 98.622 54.905 ;
     RECT  101.916 54.811 101.934 54.941 ;
     RECT  40.215 54.331 41.058 55.021 ;
     RECT  42.156 53.825 42.174 55.021 ;
     RECT  40.068 55.021 42.174 55.111 ;
     RECT  40.068 55.111 42.21 55.139 ;
     RECT  40.215 55.139 42.21 55.283 ;
     RECT  96.048 54.905 98.334 55.409 ;
     RECT  41.616 55.283 42.21 55.795 ;
     RECT  41.616 55.795 42.246 55.901 ;
     RECT  41.616 55.901 42.21 56.029 ;
     RECT  99.615 53.933 99.897 56.065 ;
     RECT  102.564 55.957 102.582 56.093 ;
     RECT  96.624 55.409 98.334 56.101 ;
     RECT  99.468 56.065 100.278 56.101 ;
     RECT  41.58 56.029 42.21 56.129 ;
     RECT  101.088 56.101 101.106 56.219 ;
     RECT  96.624 56.101 98.37 56.335 ;
     RECT  99.324 56.101 100.314 56.335 ;
     RECT  96.624 56.335 100.314 56.371 ;
     RECT  96.624 56.371 100.89 56.429 ;
     RECT  99.432 56.429 100.89 56.489 ;
     RECT  100.872 56.489 100.89 56.633 ;
     RECT  41.58 56.129 42.174 56.867 ;
     RECT  99.432 56.489 99.897 57.209 ;
     RECT  96.624 56.429 98.694 57.271 ;
     RECT  96.444 57.271 98.694 57.299 ;
     RECT  101.988 57.259 102.006 57.371 ;
     RECT  40.215 55.283 40.497 57.403 ;
     RECT  41.58 56.867 41.634 57.403 ;
     RECT  96.444 57.299 98.37 57.407 ;
     RECT  99.615 57.209 99.897 57.451 ;
     RECT  96.444 57.407 98.262 57.605 ;
     RECT  99.615 57.451 100.314 57.641 ;
     RECT  43.2 53.285 81 57.811 ;
     RECT  42.768 57.811 81 58.013 ;
     RECT  40.215 57.403 41.634 58.117 ;
     RECT  96.444 57.605 97.722 58.379 ;
     RECT  96.444 58.379 97.326 58.495 ;
     RECT  96.264 58.495 97.326 58.541 ;
     RECT  102.564 58.387 102.582 58.541 ;
     RECT  98.604 58.531 98.622 58.685 ;
     RECT  96.408 58.541 97.326 58.721 ;
     RECT  40.215 58.117 42.21 59.165 ;
     RECT  40.215 59.165 42.174 59.189 ;
     RECT  94.215 40.445 94.497 59.539 ;
     RECT  94.215 59.539 94.662 59.611 ;
     RECT  94.215 59.611 95.166 59.701 ;
     RECT  96.444 58.721 97.326 59.701 ;
     RECT  94.215 59.701 97.326 59.737 ;
     RECT  94.212 59.737 97.326 59.789 ;
     RECT  101.988 59.737 102.006 59.789 ;
     RECT  94.215 59.789 97.326 59.801 ;
     RECT  99.615 57.641 99.897 59.881 ;
     RECT  94.215 59.801 94.986 60.035 ;
     RECT  99.615 59.881 99.918 60.277 ;
     RECT  41.58 59.189 42.174 60.313 ;
     RECT  95.76 59.801 97.326 60.377 ;
     RECT  96.444 60.377 97.326 60.385 ;
     RECT  40.215 59.189 40.497 60.475 ;
     RECT  41.58 60.313 42.21 60.475 ;
     RECT  96.444 60.385 98.046 60.539 ;
     RECT  40.215 60.475 42.21 60.701 ;
     RECT  99.615 60.277 100.314 60.809 ;
     RECT  43.2 58.013 81 60.859 ;
     RECT  99.615 60.809 99.897 60.889 ;
     RECT  99.108 60.889 99.897 60.989 ;
     RECT  102.6 60.817 102.618 61.037 ;
     RECT  82.656 60.859 82.674 61.051 ;
     RECT  83.415 50.957 83.697 61.051 ;
     RECT  82.656 61.051 83.697 61.079 ;
     RECT  40.215 60.701 41.634 61.085 ;
     RECT  42.732 60.859 81 61.115 ;
     RECT  100.656 60.961 100.674 61.115 ;
     RECT  99.576 60.989 99.897 61.259 ;
     RECT  40.215 61.085 41.058 61.661 ;
     RECT  43.092 61.115 81 62.011 ;
     RECT  83.232 61.079 83.697 62.011 ;
     RECT  82.656 62.011 83.697 62.041 ;
     RECT  98.028 60.539 98.046 62.041 ;
     RECT  96.444 60.539 97.254 62.155 ;
     RECT  98.028 62.041 98.37 62.155 ;
     RECT  96.444 62.155 98.37 62.159 ;
     RECT  43.056 62.011 81 62.195 ;
     RECT  82.656 62.041 84.258 62.237 ;
     RECT  102.564 62.167 102.582 62.237 ;
     RECT  99.615 61.259 99.897 62.311 ;
     RECT  41.436 62.203 41.454 62.392 ;
     RECT  96.444 62.159 98.19 62.429 ;
     RECT  99.615 62.311 100.35 62.465 ;
     RECT  96.444 62.429 97.578 62.537 ;
     RECT  96.444 62.537 97.398 62.669 ;
     RECT  43.092 62.195 81 62.735 ;
     RECT  41.436 62.392 42.174 62.779 ;
     RECT  82.656 62.237 84.114 62.813 ;
     RECT  41.4 62.779 42.174 62.879 ;
     RECT  40.215 61.661 40.497 63.049 ;
     RECT  41.58 62.879 42.174 63.049 ;
     RECT  6.516 49.775 6.534 63.239 ;
     RECT  2.415 17.117 2.697 63.247 ;
     RECT  96.444 62.669 97.254 63.247 ;
     RECT  40.215 63.049 40.734 63.275 ;
     RECT  9.036 49.775 9.054 63.347 ;
     RECT  3.636 63.259 3.654 63.355 ;
     RECT  2.268 63.247 2.697 63.389 ;
     RECT  41.58 63.049 42.21 63.389 ;
     RECT  96.3 63.247 97.254 63.391 ;
     RECT  3.636 63.355 4.374 63.545 ;
     RECT  101.988 63.451 102.006 63.545 ;
     RECT  95.94 63.391 97.254 63.589 ;
     RECT  43.2 62.735 81 63.595 ;
     RECT  83.232 62.813 84.114 63.595 ;
     RECT  95.76 63.589 97.254 63.629 ;
     RECT  83.232 63.595 84.402 63.661 ;
     RECT  99.615 62.465 99.897 63.661 ;
     RECT  43.2 63.595 81.09 63.739 ;
     RECT  83.232 63.661 84.798 63.779 ;
     RECT  98.1 63.391 98.118 63.779 ;
     RECT  4.356 63.545 4.374 63.815 ;
     RECT  41.58 63.389 42.174 63.815 ;
     RECT  99.615 63.661 99.918 63.815 ;
     RECT  40.215 63.275 40.497 64.021 ;
     RECT  43.092 63.739 81.09 64.109 ;
     RECT  43.092 64.109 81 64.121 ;
     RECT  40.215 64.021 41.058 64.349 ;
     RECT  83.376 63.779 84.654 64.349 ;
     RECT  83.415 64.349 84.654 64.625 ;
     RECT  83.415 64.625 84.366 64.733 ;
     RECT  41.328 64.699 41.346 64.741 ;
     RECT  42.12 63.815 42.174 64.741 ;
     RECT  41.328 64.741 42.174 64.895 ;
     RECT  102.564 64.699 102.582 64.895 ;
     RECT  83.415 64.733 83.79 64.925 ;
     RECT  41.328 64.895 41.598 64.967 ;
     RECT  96.444 63.629 97.254 65.011 ;
     RECT  82.656 64.507 82.674 65.083 ;
     RECT  83.415 64.925 83.697 65.083 ;
     RECT  96.408 65.011 97.254 65.137 ;
     RECT  100.908 65.011 100.926 65.165 ;
     RECT  96.156 65.137 97.254 65.209 ;
     RECT  95.436 65.209 97.254 65.261 ;
     RECT  43.2 64.121 81 65.275 ;
     RECT  41.58 64.967 41.598 65.435 ;
     RECT  95.616 65.261 97.254 65.435 ;
     RECT  43.092 65.275 81 65.467 ;
     RECT  95.616 65.435 95.634 65.507 ;
     RECT  98.388 65.281 98.406 65.507 ;
     RECT  99.615 63.815 99.897 65.749 ;
     RECT  41.724 65.659 41.742 65.813 ;
     RECT  99.576 65.749 99.897 65.821 ;
     RECT  82.656 65.083 83.697 65.939 ;
     RECT  96.444 65.435 97.254 65.939 ;
     RECT  42.732 65.467 81 65.975 ;
     RECT  102.564 65.947 102.582 65.984 ;
     RECT  98.568 65.983 98.586 66.055 ;
     RECT  99.576 65.821 100.314 66.055 ;
     RECT  98.568 66.055 100.314 66.091 ;
     RECT  98.568 66.091 100.566 66.245 ;
     RECT  98.568 66.245 99.897 66.389 ;
     RECT  82.728 65.939 83.697 66.479 ;
     RECT  43.092 65.975 81 66.515 ;
     RECT  43.2 66.515 81 66.984 ;
     RECT  98.568 66.389 98.586 67.289 ;
     RECT  96.444 65.939 97.182 67.291 ;
     RECT  96.444 67.291 97.398 67.333 ;
     RECT  98.136 67.297 98.154 67.333 ;
     RECT  103.572 67.147 103.59 67.361 ;
     RECT  99.615 66.389 99.897 67.441 ;
     RECT  96.444 67.333 98.154 67.595 ;
     RECT  99.615 67.441 99.918 67.595 ;
     RECT  96.444 67.595 97.578 67.667 ;
     RECT  96.444 67.667 97.506 67.801 ;
     RECT  96.336 67.801 97.506 68.251 ;
     RECT  95.94 68.251 97.506 68.369 ;
     RECT  95.94 68.369 96.534 68.377 ;
     RECT  94.215 60.035 94.497 68.395 ;
     RECT  95.76 68.377 96.534 68.395 ;
     RECT  102.6 68.377 102.618 68.429 ;
     RECT  94.215 68.395 96.534 68.675 ;
     RECT  94.215 68.675 96.102 68.747 ;
     RECT  97.488 68.369 97.506 68.819 ;
     RECT  2.415 63.389 2.697 68.867 ;
     RECT  7.815 49.541 8.097 68.867 ;
     RECT  13.215 38.705 13.497 68.867 ;
     RECT  18.615 40.361 18.897 68.867 ;
     RECT  24.015 46.409 24.297 68.867 ;
     RECT  29.415 47.453 29.697 68.867 ;
     RECT  34.815 48.569 35.097 68.867 ;
     RECT  40.215 64.349 40.497 68.867 ;
     RECT  83.415 66.479 83.697 68.867 ;
     RECT  88.815 36.797 89.097 68.867 ;
     RECT  99.615 67.595 99.897 68.867 ;
     RECT  94.215 68.747 95.85 68.909 ;
     RECT  100.944 68.719 100.962 68.909 ;
     RECT  98.604 68.521 98.622 68.945 ;
     RECT  94.215 68.909 95.022 68.981 ;
     RECT  95.832 68.909 95.85 68.981 ;
     RECT  2.415 68.867 2.505 69.137 ;
     RECT  7.815 68.867 7.905 69.137 ;
     RECT  13.215 68.867 13.305 69.137 ;
     RECT  18.615 68.867 18.705 69.137 ;
     RECT  24.015 68.867 24.105 69.137 ;
     RECT  29.415 68.867 29.505 69.137 ;
     RECT  34.815 68.867 34.905 69.137 ;
     RECT  40.215 68.867 40.305 69.137 ;
     RECT  83.415 68.867 83.505 69.137 ;
     RECT  88.815 68.867 88.905 69.137 ;
     RECT  94.215 68.981 94.305 69.137 ;
     RECT  99.615 68.867 99.705 69.137 ;
     RECT  100.728 68.953 100.746 69.677 ;
    LAYER M4 ;
     RECT  0.06 7.92 0.137 7.944 ;
     RECT  0.06 21.792 0.137 21.816 ;
     RECT  0.06 49.488 0.137 49.512 ;
     RECT  0.06 35.616 0.569 35.64 ;
     RECT  2.293 2.064 2.329 2.088 ;
     RECT  2.293 3.408 2.329 3.432 ;
     RECT  2.293 7.392 2.401 8.568 ;
     RECT  2.329 2.064 2.408 3.432 ;
     RECT  2.401 7.392 2.408 9.336 ;
     RECT  2.285 11.232 2.408 11.256 ;
     RECT  2.293 12.528 2.408 12.744 ;
     RECT  2.329 14.208 2.408 14.232 ;
     RECT  2.365 16.368 2.408 16.392 ;
     RECT  0.06 63.36 2.408 63.384 ;
     RECT  2.408 2.064 2.441 69.132 ;
     RECT  2.441 2.148 2.512 69.132 ;
     RECT  2.512 2.418 2.704 68.862 ;
     RECT  2.653 0.576 3.125 0.6 ;
     RECT  2.704 16.368 3.347 17.64 ;
     RECT  2.704 63.264 3.709 63.288 ;
     RECT  2.704 4.32 3.913 7.944 ;
     RECT  2.704 9.12 3.913 9.336 ;
     RECT  2.704 10.464 3.913 10.488 ;
     RECT  2.704 12.528 4.021 12.552 ;
     RECT  2.704 13.776 4.021 14.568 ;
     RECT  2.704 23.904 4.021 23.928 ;
     RECT  3.913 9.12 4.057 10.488 ;
     RECT  3.347 16.896 4.061 17.64 ;
     RECT  4.021 12.528 4.067 14.568 ;
     RECT  4.021 25.008 4.453 25.032 ;
     RECT  3.913 4.32 4.525 7.992 ;
     RECT  4.057 9.024 4.525 10.488 ;
     RECT  4.021 23.328 4.525 23.928 ;
     RECT  4.067 14.544 4.561 14.568 ;
     RECT  3.805 21.648 4.601 21.672 ;
     RECT  4.525 4.32 4.669 10.488 ;
     RECT  4.561 14.544 4.709 14.712 ;
     RECT  4.669 4.032 4.849 10.488 ;
     RECT  4.777 31.872 4.933 31.896 ;
     RECT  4.453 25.008 4.979 25.272 ;
     RECT  4.067 13.056 5.173 13.08 ;
     RECT  4.453 18.816 5.173 18.84 ;
     RECT  5.173 13.056 5.209 13.368 ;
     RECT  4.061 17.616 5.245 17.64 ;
     RECT  5.209 12.24 5.317 13.368 ;
     RECT  5.317 11.712 5.393 13.368 ;
     RECT  4.849 3.984 5.413 10.488 ;
     RECT  5.393 11.712 5.413 13.08 ;
     RECT  4.933 30.96 5.425 31.896 ;
     RECT  5.245 14.496 5.429 14.52 ;
     RECT  5.245 17.04 5.461 17.64 ;
     RECT  5.173 18.72 5.461 18.84 ;
     RECT  4.979 25.008 5.501 25.08 ;
     RECT  5.425 30.96 5.533 31.992 ;
     RECT  5.461 17.04 5.605 18.84 ;
     RECT  5.605 17.04 5.641 19.416 ;
     RECT  5.533 30.72 5.651 31.992 ;
     RECT  5.641 16.224 5.689 19.416 ;
     RECT  5.651 30.96 5.699 31.896 ;
     RECT  4.885 29.616 5.861 29.64 ;
     RECT  5.749 20.304 5.933 20.904 ;
     RECT  4.525 22.752 5.969 23.928 ;
     RECT  5.969 23.904 6.005 23.928 ;
     RECT  5.857 28.56 6.131 28.584 ;
     RECT  4.993 26.4 6.181 26.424 ;
     RECT  5.677 14.736 6.229 15.24 ;
     RECT  5.689 16.224 6.229 18.888 ;
     RECT  6.229 14.736 6.329 18.888 ;
     RECT  5.413 3.984 6.545 13.08 ;
     RECT  5.699 30.96 6.829 31.32 ;
     RECT  6.613 27.888 6.853 28.488 ;
     RECT  6.545 3.984 6.865 11.544 ;
     RECT  5.501 25.056 6.937 25.08 ;
     RECT  5.933 20.304 6.984 20.328 ;
     RECT  6.329 17.472 7.004 18.888 ;
     RECT  6.984 20.304 7.004 20.616 ;
     RECT  6.181 26.208 7.045 26.424 ;
     RECT  6.853 27.6 7.045 28.488 ;
     RECT  6.865 3.456 7.084 11.544 ;
     RECT  6.545 12.528 7.189 13.08 ;
     RECT  5.969 22.752 7.189 22.92 ;
     RECT  6.937 24.624 7.189 25.08 ;
     RECT  7.189 22.752 7.513 25.08 ;
     RECT  6.505 33.6 7.621 33.624 ;
     RECT  7.513 22.224 7.729 25.08 ;
     RECT  7.084 3.408 7.808 11.544 ;
     RECT  7.189 12.528 7.808 13.416 ;
     RECT  6.329 14.736 7.808 16.296 ;
     RECT  7.004 17.472 7.808 20.616 ;
     RECT  7.729 21.792 7.808 25.08 ;
     RECT  7.045 26.208 7.808 28.488 ;
     RECT  6.829 30.24 7.808 31.32 ;
     RECT  7.621 33.6 7.808 33.672 ;
     RECT  6.469 34.944 7.808 35.448 ;
     RECT  2.704 49.488 7.808 49.512 ;
     RECT  7.808 2.148 7.912 69.132 ;
     RECT  7.912 2.418 8.104 68.862 ;
     RECT  8.104 48.384 8.165 49.512 ;
     RECT  8.104 14.112 8.201 25.752 ;
     RECT  8.201 14.112 8.237 17.112 ;
     RECT  8.104 26.736 8.237 30.888 ;
     RECT  8.165 48.384 8.243 49.32 ;
     RECT  8.201 18.144 8.309 25.752 ;
     RECT  8.309 23.28 8.387 25.752 ;
     RECT  8.309 18.144 8.525 22.2 ;
     RECT  8.237 14.112 8.531 16.008 ;
     RECT  8.237 30.864 8.633 30.888 ;
     RECT  8.104 34.944 8.669 37.08 ;
     RECT  8.104 32.736 8.741 33.672 ;
     RECT  8.531 14.112 8.813 14.232 ;
     RECT  8.741 32.736 9.205 32.856 ;
     RECT  8.104 3.984 9.241 13.08 ;
     RECT  8.813 14.112 9.241 14.184 ;
     RECT  8.387 23.328 9.245 25.752 ;
     RECT  9.205 31.92 9.277 32.856 ;
     RECT  8.669 34.992 9.281 37.08 ;
     RECT  9.245 25.008 9.308 25.752 ;
     RECT  8.237 26.736 9.308 29.88 ;
     RECT  9.245 23.328 9.421 23.832 ;
     RECT  8.531 15.504 9.425 16.008 ;
     RECT  9.241 3.984 9.452 14.184 ;
     RECT  9.425 15.552 9.529 16.008 ;
     RECT  8.237 16.992 9.529 17.112 ;
     RECT  9.452 3.216 9.539 14.184 ;
     RECT  8.525 20.928 9.565 22.2 ;
     RECT  9.421 23.184 9.565 23.832 ;
     RECT  9.308 25.008 9.569 29.88 ;
     RECT  9.565 20.928 9.733 23.832 ;
     RECT  9.281 34.992 9.74 35.304 ;
     RECT  8.525 18.144 9.745 19.656 ;
     RECT  9.733 20.784 9.745 23.832 ;
     RECT  9.281 36.336 9.781 37.08 ;
     RECT  9.745 18.144 9.821 23.832 ;
     RECT  9.74 34.176 9.827 35.304 ;
     RECT  9.821 18.144 9.829 20.568 ;
     RECT  9.277 31.728 9.853 32.856 ;
     RECT  9.569 25.632 9.889 29.88 ;
     RECT  9.853 31.296 9.889 32.856 ;
     RECT  9.539 3.936 9.965 14.184 ;
     RECT  9.529 15.552 10.105 17.112 ;
     RECT  9.829 18.144 10.105 19.656 ;
     RECT  9.889 25.632 10.141 32.856 ;
     RECT  9.781 36.336 10.249 37.848 ;
     RECT  9.965 14.16 10.289 14.184 ;
     RECT  10.141 25.632 10.325 33 ;
     RECT  10.105 15.552 10.469 19.656 ;
     RECT  9.821 21.648 10.681 23.832 ;
     RECT  10.249 36.336 10.835 38.376 ;
     RECT  10.469 16.512 10.901 19.656 ;
     RECT  10.325 26.016 10.901 33 ;
     RECT  10.901 26.016 10.944 31.128 ;
     RECT  9.965 3.936 11.041 13.176 ;
     RECT  10.901 18.096 11.081 19.656 ;
     RECT  10.681 21.648 11.113 24.552 ;
     RECT  9.827 34.224 11.113 35.304 ;
     RECT  10.609 0.576 11.123 0.6 ;
     RECT  11.113 34.224 11.125 35.352 ;
     RECT  11.113 21.648 11.185 25.032 ;
     RECT  11.125 34.128 11.197 35.352 ;
     RECT  10.901 32.16 11.257 33 ;
     RECT  11.197 34.128 11.257 35.304 ;
     RECT  10.835 36.336 11.297 37.896 ;
     RECT  9.241 1.728 11.317 1.752 ;
     RECT  11.257 32.16 11.369 35.304 ;
     RECT  11.185 21.408 11.545 25.032 ;
     RECT  10.897 14.976 11.549 15 ;
     RECT  11.297 37.728 11.549 37.896 ;
     RECT  11.545 21.408 11.797 25.128 ;
     RECT  11.081 18.096 11.837 19.128 ;
     RECT  11.041 3.936 11.941 13.608 ;
     RECT  11.797 20.592 11.977 25.128 ;
     RECT  11.977 20.592 12.085 25.752 ;
     RECT  10.944 26.88 12.085 31.128 ;
     RECT  12.085 20.592 12.193 31.128 ;
     RECT  11.941 3.936 12.229 14.28 ;
     RECT  11.941 15.504 12.233 15.528 ;
     RECT  12.229 3.6 12.265 14.28 ;
     RECT  11.317 1.152 12.305 1.752 ;
     RECT  12.193 20.256 12.337 31.128 ;
     RECT  11.369 32.16 12.337 33.624 ;
     RECT  11.369 34.992 12.469 35.304 ;
     RECT  11.297 36.336 12.469 36.456 ;
     RECT  12.337 20.256 12.553 33.624 ;
     RECT  12.469 34.992 12.553 36.456 ;
     RECT  11.549 37.872 12.553 37.896 ;
     RECT  12.265 3.072 12.613 14.28 ;
     RECT  10.901 16.512 12.769 17.064 ;
     RECT  12.553 19.824 12.913 33.624 ;
     RECT  12.769 15.84 12.985 17.064 ;
     RECT  12.305 1.728 13.208 1.752 ;
     RECT  12.613 2.88 13.208 14.28 ;
     RECT  12.985 15.84 13.208 17.112 ;
     RECT  11.837 18.192 13.208 18.84 ;
     RECT  12.913 19.824 13.208 33.864 ;
     RECT  12.553 34.992 13.208 37.896 ;
     RECT  9.889 41.904 13.208 41.928 ;
     RECT  11.689 46.848 13.208 46.872 ;
     RECT  8.243 48.384 13.208 48.408 ;
     RECT  13.208 1.728 13.312 69.132 ;
     RECT  13.312 1.728 13.504 68.862 ;
     RECT  13.504 15.36 13.619 32.04 ;
     RECT  13.504 1.728 13.667 14.28 ;
     RECT  13.667 2.88 13.925 14.28 ;
     RECT  13.925 13.104 14.185 14.28 ;
     RECT  13.925 2.88 14.213 11.976 ;
     RECT  14.185 13.296 14.256 14.28 ;
     RECT  13.619 15.36 14.285 31.752 ;
     RECT  14.285 15.984 14.291 31.752 ;
     RECT  13.504 33.6 14.321 36.888 ;
     RECT  14.173 0.576 14.435 0.6 ;
     RECT  14.291 16.8 14.773 31.752 ;
     RECT  14.773 16.8 14.821 31.944 ;
     RECT  14.321 33.84 14.821 36.888 ;
     RECT  13.504 37.872 14.821 38.136 ;
     RECT  14.821 33.84 15.145 38.664 ;
     RECT  14.256 13.536 15.253 14.28 ;
     RECT  15.253 13.152 15.299 14.28 ;
     RECT  14.213 2.928 15.361 11.784 ;
     RECT  15.299 13.152 15.361 13.848 ;
     RECT  15.145 33.84 15.397 38.76 ;
     RECT  14.821 16.8 15.433 32.184 ;
     RECT  15.433 16.8 15.509 32.856 ;
     RECT  15.509 16.8 15.545 27.192 ;
     RECT  15.397 33.84 15.545 39.768 ;
     RECT  15.361 2.928 15.581 13.848 ;
     RECT  15.545 39.36 15.725 39.768 ;
     RECT  15.581 2.928 15.893 13.176 ;
     RECT  15.545 33.84 15.941 38.184 ;
     RECT  15.545 16.8 16.081 18.456 ;
     RECT  15.509 28.32 16.333 32.856 ;
     RECT  15.941 33.84 16.333 38.088 ;
     RECT  13.667 1.728 16.453 1.752 ;
     RECT  16.081 15.408 16.553 18.456 ;
     RECT  16.553 15.936 16.621 18.456 ;
     RECT  15.545 19.488 16.621 27.192 ;
     RECT  16.333 28.32 16.657 38.088 ;
     RECT  15.893 2.88 16.697 13.176 ;
     RECT  16.453 1.152 16.841 1.752 ;
     RECT  16.621 15.936 16.933 27.192 ;
     RECT  16.657 28.224 16.933 38.088 ;
     RECT  15.725 39.36 16.933 39.384 ;
     RECT  16.933 39.36 16.979 40.008 ;
     RECT  16.933 15.936 16.989 38.088 ;
     RECT  16.979 39.744 17.02 40.008 ;
     RECT  16.841 1.152 17.129 1.176 ;
     RECT  13.504 46.848 17.305 46.872 ;
     RECT  16.989 15.936 17.489 38.184 ;
     RECT  17.489 34.8 17.629 38.184 ;
     RECT  17.593 14.496 17.809 14.52 ;
     RECT  16.697 2.88 17.989 13.08 ;
     RECT  17.809 14.256 17.989 14.52 ;
     RECT  17.489 15.936 17.989 33.816 ;
     RECT  17.629 34.8 18.385 38.424 ;
     RECT  17.02 39.744 18.469 39.768 ;
     RECT  17.989 2.256 18.608 13.08 ;
     RECT  17.989 14.256 18.608 33.816 ;
     RECT  18.385 34.8 18.608 38.76 ;
     RECT  18.469 39.744 18.608 40.056 ;
     RECT  13.504 41.904 18.608 41.928 ;
     RECT  17.305 46.272 18.608 46.872 ;
     RECT  13.504 48.384 18.608 48.408 ;
     RECT  18.608 2.148 18.712 69.132 ;
     RECT  18.712 2.418 18.904 68.862 ;
     RECT  18.904 2.88 19.073 26.664 ;
     RECT  18.904 27.648 19.217 38.712 ;
     RECT  19.217 27.648 19.289 38.568 ;
     RECT  19.289 27.648 19.361 38.472 ;
     RECT  18.904 40.032 19.757 40.056 ;
     RECT  18.904 41.904 19.909 41.928 ;
     RECT  19.073 3.072 19.933 26.664 ;
     RECT  19.361 27.648 19.933 38.04 ;
     RECT  19.909 41.04 20.045 41.928 ;
     RECT  19.933 3.072 20.437 38.04 ;
     RECT  20.437 3.072 20.657 38.184 ;
     RECT  18.904 46.368 20.689 47.208 ;
     RECT  18.904 48.384 20.689 48.408 ;
     RECT  20.657 3.072 22.273 29.64 ;
     RECT  20.657 30.624 22.273 38.184 ;
     RECT  22.273 3.072 22.637 38.184 ;
     RECT  22.637 3.072 22.961 20.76 ;
     RECT  20.833 39.6 22.993 39.624 ;
     RECT  22.637 21.744 23.173 38.184 ;
     RECT  23.173 21.744 23.353 38.232 ;
     RECT  22.993 39.6 23.353 39.768 ;
     RECT  22.961 3.072 23.677 20.664 ;
     RECT  23.677 2.784 24.008 20.664 ;
     RECT  23.353 21.744 24.008 39.768 ;
     RECT  20.045 41.904 24.008 41.928 ;
     RECT  20.689 46.368 24.008 48.408 ;
     RECT  24.008 2.148 24.112 69.132 ;
     RECT  24.112 2.418 24.304 68.862 ;
     RECT  24.304 2.736 24.833 38.808 ;
     RECT  24.833 2.832 25.621 38.808 ;
     RECT  25.621 2.832 25.733 39.048 ;
     RECT  25.733 2.88 25.909 39.048 ;
     RECT  26.012 40.416 26.053 40.44 ;
     RECT  26.053 40.416 26.099 40.872 ;
     RECT  25.909 2.88 26.201 39.384 ;
     RECT  26.161 0.576 26.435 0.6 ;
     RECT  26.201 3.072 26.705 39.384 ;
     RECT  26.705 26.88 26.737 39.384 ;
     RECT  26.737 26.88 27.277 39.768 ;
     RECT  26.099 40.848 27.277 40.872 ;
     RECT  27.277 26.88 27.929 40.872 ;
     RECT  27.929 26.88 28.033 38.712 ;
     RECT  26.705 3.072 28.213 25.704 ;
     RECT  28.033 26.784 28.213 38.712 ;
     RECT  27.929 39.744 28.325 40.872 ;
     RECT  26.413 1.728 28.453 1.752 ;
     RECT  28.453 1.152 28.577 1.752 ;
     RECT  28.213 3.072 28.933 38.712 ;
     RECT  29.041 0.528 29.267 0.552 ;
     RECT  28.577 1.68 29.408 1.752 ;
     RECT  28.933 2.88 29.408 38.712 ;
     RECT  28.325 39.984 29.408 40.872 ;
     RECT  24.304 41.904 29.408 41.928 ;
     RECT  24.304 46.368 29.408 48.408 ;
     RECT  29.408 1.68 29.512 69.132 ;
     RECT  29.512 1.68 29.704 68.862 ;
     RECT  29.581 0.096 29.747 0.12 ;
     RECT  29.704 1.68 29.765 1.752 ;
     RECT  29.765 1.728 30.805 1.752 ;
     RECT  29.704 2.88 30.805 40.872 ;
     RECT  30.757 0.096 30.899 0.12 ;
     RECT  29.704 46.368 31.309 48.408 ;
     RECT  30.805 1.728 31.925 40.872 ;
     RECT  31.925 2.832 31.961 40.872 ;
     RECT  31.961 2.88 32.339 40.872 ;
     RECT  31.273 0.576 32.819 0.6 ;
     RECT  32.339 2.928 32.969 40.872 ;
     RECT  31.925 1.728 33.373 1.752 ;
     RECT  33.541 1.152 33.761 1.176 ;
     RECT  32.969 3.072 34.808 40.872 ;
     RECT  29.704 41.904 34.808 41.928 ;
     RECT  31.309 46.368 34.808 48.552 ;
     RECT  34.808 2.148 34.912 69.132 ;
     RECT  34.912 2.418 35.104 68.862 ;
     RECT  35.104 2.544 35.309 40.584 ;
     RECT  35.309 2.544 35.381 39.912 ;
     RECT  35.381 36.48 35.561 39.912 ;
     RECT  35.381 2.544 36.065 35.208 ;
     RECT  36.133 43.92 36.14 43.944 ;
     RECT  36.14 43.92 36.227 44.808 ;
     RECT  36.065 2.544 36.281 35.016 ;
     RECT  35.561 36.528 36.421 39.912 ;
     RECT  36.227 43.92 36.505 43.992 ;
     RECT  36.421 36.528 36.565 40.584 ;
     RECT  36.565 36.432 36.601 40.584 ;
     RECT  36.281 2.544 37.109 11.256 ;
     RECT  36.281 12.288 37.321 35.016 ;
     RECT  36.601 36.192 37.321 40.584 ;
     RECT  37.321 12.288 37.933 40.584 ;
     RECT  37.109 2.976 38.185 11.256 ;
     RECT  37.933 12.288 38.185 40.872 ;
     RECT  36.505 43.92 38.339 43.944 ;
     RECT  38.185 2.976 38.771 40.872 ;
     RECT  38.771 38.352 38.873 40.872 ;
     RECT  35.104 46.368 39.589 48.552 ;
     RECT  38.771 2.976 39.985 37.128 ;
     RECT  38.873 38.496 39.985 40.872 ;
     RECT  39.985 2.976 40.208 40.872 ;
     RECT  35.104 41.904 40.208 41.928 ;
     RECT  39.589 46.368 40.208 49.08 ;
     RECT  40.208 2.148 40.312 69.132 ;
     RECT  40.312 2.418 40.504 68.862 ;
     RECT  40.504 3.12 41.105 40.584 ;
     RECT  40.504 41.904 41.171 42.744 ;
     RECT  41.105 12.24 41.285 40.584 ;
     RECT  40.504 64.32 41.533 64.728 ;
     RECT  40.504 46.08 41.569 49.08 ;
     RECT  40.504 50.688 41.569 55.128 ;
     RECT  40.504 57.408 41.569 58.968 ;
     RECT  40.504 60.48 41.569 62.808 ;
     RECT  41.533 64.32 41.569 64.92 ;
     RECT  41.569 46.08 41.713 65.112 ;
     RECT  40.504 44.16 42.001 44.184 ;
     RECT  42.001 44.16 42.037 44.952 ;
     RECT  41.713 46.08 42.037 65.688 ;
     RECT  41.105 3.12 42.085 11.256 ;
     RECT  41.285 12.24 42.085 29.208 ;
     RECT  41.171 41.904 42.145 42.696 ;
     RECT  42.085 3.12 42.253 29.208 ;
     RECT  41.285 30.336 42.253 38.808 ;
     RECT  41.285 39.936 42.253 40.584 ;
     RECT  42.253 2.88 42.325 29.208 ;
     RECT  42.253 30.336 42.325 40.584 ;
     RECT  42.325 2.88 42.437 40.584 ;
     RECT  42.577 0.576 42.803 0.6 ;
     RECT  42.437 40.464 42.901 40.584 ;
     RECT  42.037 44.16 42.901 65.688 ;
     RECT  42.145 41.904 42.997 42.744 ;
     RECT  42.901 40.464 43.009 40.728 ;
     RECT  42.901 43.968 43.081 65.688 ;
     RECT  42.437 2.88 43.157 39.336 ;
     RECT  42.997 41.904 43.187 42.84 ;
     RECT  43.081 43.968 43.272 65.88 ;
     RECT  43.009 40.464 43.309 40.824 ;
     RECT  43.157 3.12 43.331 39.336 ;
     RECT  43.309 40.56 43.553 40.824 ;
     RECT  41.989 1.728 43.765 1.752 ;
     RECT  43.765 1.152 43.801 1.752 ;
     RECT  43.331 28.464 43.913 39.336 ;
     RECT  43.801 0.576 44.051 1.752 ;
     RECT  43.331 3.552 44.341 27.48 ;
     RECT  43.913 28.464 44.341 39.288 ;
     RECT  44.051 1.152 44.381 1.752 ;
     RECT  44.341 3.552 44.413 39.288 ;
     RECT  44.413 2.88 44.525 39.288 ;
     RECT  44.525 2.88 44.561 14.424 ;
     RECT  43.553 40.56 44.665 40.584 ;
     RECT  44.381 1.728 45.097 1.752 ;
     RECT  45.097 1.728 45.541 1.8 ;
     RECT  45.541 1.68 45.608 1.8 ;
     RECT  44.561 3.552 45.608 14.424 ;
     RECT  44.525 15.552 45.608 39.288 ;
     RECT  44.665 40.416 45.608 40.584 ;
     RECT  43.187 41.904 45.608 41.928 ;
     RECT  45.608 1.68 45.712 41.928 ;
     RECT  45.712 1.68 45.785 40.782 ;
     RECT  45.785 1.728 45.904 40.782 ;
     RECT  45.904 1.728 45.965 1.992 ;
     RECT  45.904 28.272 46.001 38.76 ;
     RECT  45.904 25.488 46.211 27.096 ;
     RECT  46.211 25.536 46.739 27.096 ;
     RECT  46.739 25.776 46.897 27.096 ;
     RECT  46.001 28.272 46.897 38.712 ;
     RECT  45.965 1.728 46.937 1.752 ;
     RECT  45.904 3.552 46.973 24.36 ;
     RECT  46.973 3.552 47.365 23.064 ;
     RECT  46.897 25.776 47.477 38.712 ;
     RECT  47.477 38.64 47.545 38.712 ;
     RECT  47.477 25.776 47.549 37.608 ;
     RECT  47.365 2.88 47.693 23.064 ;
     RECT  47.549 25.776 47.797 37.416 ;
     RECT  47.693 2.928 47.837 23.064 ;
     RECT  47.077 1.152 47.945 1.176 ;
     RECT  47.797 25.488 47.945 37.416 ;
     RECT  47.837 3.168 47.981 23.064 ;
     RECT  47.981 3.168 48.125 19.224 ;
     RECT  48.133 1.728 48.193 1.752 ;
     RECT  46.973 24.192 48.337 24.36 ;
     RECT  47.945 25.488 48.337 27.528 ;
     RECT  47.981 20.304 48.553 23.064 ;
     RECT  48.337 24.192 48.553 27.528 ;
     RECT  47.945 28.752 48.589 37.416 ;
     RECT  47.545 38.64 48.589 38.856 ;
     RECT  48.125 3.168 48.737 19.08 ;
     RECT  48.737 3.168 48.773 13.752 ;
     RECT  48.589 28.752 48.841 38.856 ;
     RECT  45.904 40.416 48.841 40.44 ;
     RECT  48.773 3.168 48.901 13.608 ;
     RECT  48.193 1.728 48.908 1.8 ;
     RECT  48.901 2.88 48.908 13.608 ;
     RECT  48.908 1.728 48.995 13.608 ;
     RECT  48.841 28.752 49.061 40.44 ;
     RECT  49.061 28.752 49.093 35.832 ;
     RECT  48.737 14.784 49.237 19.08 ;
     RECT  49.237 14.784 49.273 19.32 ;
     RECT  48.553 20.304 49.273 27.528 ;
     RECT  48.995 2.88 49.313 13.608 ;
     RECT  48.995 1.728 49.525 1.752 ;
     RECT  49.273 14.784 49.673 27.528 ;
     RECT  49.525 1.152 49.715 1.752 ;
     RECT  49.673 14.784 49.741 27.432 ;
     RECT  49.313 3.264 49.877 13.608 ;
     RECT  49.741 14.736 49.877 27.432 ;
     RECT  49.061 37.152 50.065 40.44 ;
     RECT  49.715 1.728 50.069 1.752 ;
     RECT  49.093 28.512 50.485 35.832 ;
     RECT  50.065 37.056 50.485 40.44 ;
     RECT  49.877 3.264 50.605 27.432 ;
     RECT  50.54 0.096 50.627 0.12 ;
     RECT  50.605 3.12 50.713 27.432 ;
     RECT  50.713 2.148 50.821 27.432 ;
     RECT  50.485 28.512 50.821 40.44 ;
     RECT  50.821 2.148 51.008 40.44 ;
     RECT  45.712 41.904 51.008 41.928 ;
     RECT  51.008 2.148 51.112 41.928 ;
     RECT  51.112 2.304 51.304 40.782 ;
     RECT  51.304 2.304 51.365 38.808 ;
     RECT  51.365 2.304 51.443 27.912 ;
     RECT  51.443 2.304 51.481 16.44 ;
     RECT  51.443 17.424 51.833 27.912 ;
     RECT  51.365 29.088 51.869 38.808 ;
     RECT  51.869 29.088 52.477 36.264 ;
     RECT  52.477 29.04 52.517 36.264 ;
     RECT  51.833 17.424 52.553 27.576 ;
     RECT  51.481 2.304 52.945 16.392 ;
     RECT  52.553 17.424 52.945 27.096 ;
     RECT  51.869 37.344 53.036 38.808 ;
     RECT  52.945 2.304 53.057 27.096 ;
     RECT  53.057 2.304 53.093 22.536 ;
     RECT  53.057 23.568 53.093 27.096 ;
     RECT  53.093 3.168 53.345 22.536 ;
     RECT  52.517 29.04 53.521 35.352 ;
     RECT  53.036 36.576 53.521 38.808 ;
     RECT  53.521 28.272 53.557 35.352 ;
     RECT  53.093 25.248 53.701 27.096 ;
     RECT  53.557 28.224 53.701 35.352 ;
     RECT  53.701 25.248 53.809 35.352 ;
     RECT  53.521 36.48 53.809 38.808 ;
     RECT  53.345 3.168 53.813 20.136 ;
     RECT  53.809 25.248 53.843 38.808 ;
     RECT  53.843 25.248 54.028 38.664 ;
     RECT  53.093 23.568 54.313 24.216 ;
     RECT  54.028 25.248 54.313 38.136 ;
     RECT  53.813 3.408 54.469 20.136 ;
     RECT  53.345 21.12 54.469 22.536 ;
     RECT  54.469 3.408 54.517 22.536 ;
     RECT  54.313 23.568 54.517 38.136 ;
     RECT  54.517 3.408 54.785 38.136 ;
     RECT  54.785 3.408 54.821 36.936 ;
     RECT  54.821 3.408 54.929 36.6 ;
     RECT  54.929 14.4 54.965 36.6 ;
     RECT  54.965 18.576 55.181 36.6 ;
     RECT  54.785 38.112 55.289 38.136 ;
     RECT  55.181 18.576 55.331 36.552 ;
     RECT  54.929 3.408 55.969 13.368 ;
     RECT  55.969 3.408 56.041 13.416 ;
     RECT  54.965 14.4 56.041 17.448 ;
     RECT  56.041 3.408 56.077 17.448 ;
     RECT  55.331 18.576 56.077 36.408 ;
     RECT  56.077 3.408 56.408 36.408 ;
     RECT  51.112 41.904 56.408 41.928 ;
     RECT  56.408 2.148 56.512 41.928 ;
     RECT  56.512 2.418 56.704 40.782 ;
     RECT  56.704 19.824 57.377 36.12 ;
     RECT  57.985 1.152 58.355 1.176 ;
     RECT  57.377 19.872 58.405 36.12 ;
     RECT  58.405 19.872 58.451 36.936 ;
     RECT  56.704 3.6 58.453 18.84 ;
     RECT  58.451 19.872 58.457 35.352 ;
     RECT  58.453 2.88 58.643 18.84 ;
     RECT  58.643 3.6 58.921 18.84 ;
     RECT  58.457 19.872 58.921 35.016 ;
     RECT  58.921 3.6 58.925 35.016 ;
     RECT  58.777 1.728 60.433 1.752 ;
     RECT  58.925 3.648 60.973 35.016 ;
     RECT  60.973 3.6 61.045 35.016 ;
     RECT  61.045 3.552 61.549 35.016 ;
     RECT  60.433 1.728 61.808 1.8 ;
     RECT  61.549 3.408 61.808 35.016 ;
     RECT  58.451 36.912 61.808 36.936 ;
     RECT  56.512 41.904 61.808 41.928 ;
     RECT  61.808 1.728 61.909 41.928 ;
     RECT  61.909 1.152 61.912 41.928 ;
     RECT  61.912 1.152 62.104 40.782 ;
     RECT  61.945 0.096 62.665 0.12 ;
     RECT  62.104 1.152 62.665 1.752 ;
     RECT  62.665 0.096 62.819 1.752 ;
     RECT  62.104 3.024 62.957 35.016 ;
     RECT  62.819 0.576 63.491 1.752 ;
     RECT  63.491 1.152 63.929 1.752 ;
     RECT  62.957 3.024 64.037 19.368 ;
     RECT  64.037 3.552 64.109 19.368 ;
     RECT  64.109 3.6 64.537 19.368 ;
     RECT  62.957 20.352 64.537 35.016 ;
     RECT  63.929 1.728 65.509 1.752 ;
     RECT  64.537 3.6 65.653 35.016 ;
     RECT  65.509 1.152 65.657 1.752 ;
     RECT  62.104 36.912 65.833 36.936 ;
     RECT  65.833 36.48 65.873 36.936 ;
     RECT  65.873 36.48 65.917 36.888 ;
     RECT  65.657 1.728 65.945 1.752 ;
     RECT  65.653 3.552 66.229 35.016 ;
     RECT  65.989 1.776 66.917 1.8 ;
     RECT  66.229 2.88 67.208 35.016 ;
     RECT  65.917 36.864 67.208 36.888 ;
     RECT  61.912 41.904 67.208 41.928 ;
     RECT  67.208 2.148 67.312 41.928 ;
     RECT  67.312 2.418 67.504 40.782 ;
     RECT  67.504 3.6 68.929 35.016 ;
     RECT  68.929 3.408 69.077 35.016 ;
     RECT  69.077 3.84 70.049 35.016 ;
     RECT  70.049 3.84 70.163 29.4 ;
     RECT  70.163 3.84 71.197 22.824 ;
     RECT  70.163 23.856 71.197 29.4 ;
     RECT  71.197 3.84 71.485 29.4 ;
     RECT  70.049 30.384 71.485 35.016 ;
     RECT  71.485 3.84 72.385 35.016 ;
     RECT  72.385 3.6 72.608 35.016 ;
     RECT  67.504 36.768 72.608 36.792 ;
     RECT  67.312 41.904 72.608 41.928 ;
     RECT  72.608 2.148 72.712 41.928 ;
     RECT  72.712 2.418 72.904 40.782 ;
     RECT  74.437 0.096 74.723 0.12 ;
     RECT  72.904 3.6 75.629 35.016 ;
     RECT  75.629 3.6 75.769 19.08 ;
     RECT  74.905 1.728 76.025 1.752 ;
     RECT  76.213 1.152 76.273 1.176 ;
     RECT  76.273 0.576 76.457 1.176 ;
     RECT  75.769 3.312 76.741 19.08 ;
     RECT  75.629 20.112 76.741 35.016 ;
     RECT  76.741 2.88 76.745 35.016 ;
     RECT  76.745 2.88 76.889 33.96 ;
     RECT  76.889 3.6 76.997 33.96 ;
     RECT  76.457 0.576 77.581 0.6 ;
     RECT  77.201 1.728 77.785 1.752 ;
     RECT  77.785 1.728 78.008 1.8 ;
     RECT  76.997 3.6 78.008 17.496 ;
     RECT  76.997 18.528 78.008 33.96 ;
     RECT  76.745 34.992 78.008 35.016 ;
     RECT  72.904 36.768 78.008 36.792 ;
     RECT  72.712 41.904 78.008 41.928 ;
     RECT  78.008 1.728 78.112 41.928 ;
     RECT  78.112 1.728 78.304 40.782 ;
     RECT  78.304 2.88 78.437 33.96 ;
     RECT  78.304 1.728 78.517 1.752 ;
     RECT  78.517 1.152 78.689 1.752 ;
     RECT  78.437 3.12 80.341 33.96 ;
     RECT  80.341 3.072 80.701 33.96 ;
     RECT  80.701 2.88 80.867 33.96 ;
     RECT  43.272 43.2 80.928 66.984 ;
     RECT  80.928 43.968 81 65.88 ;
     RECT  81.053 0.096 81.137 0.12 ;
     RECT  81 43.968 81.137 51.288 ;
     RECT  80.867 3.072 81.533 33.96 ;
     RECT  81.997 0.576 82.115 0.6 ;
     RECT  78.689 1.728 82.505 1.752 ;
     RECT  81.533 3.12 82.681 33.96 ;
     RECT  82.597 1.152 82.829 1.176 ;
     RECT  82.681 2.88 83.408 33.96 ;
     RECT  78.304 34.992 83.408 35.016 ;
     RECT  78.304 36.768 83.408 36.792 ;
     RECT  78.112 41.904 83.408 41.928 ;
     RECT  81.137 43.968 83.408 51.096 ;
     RECT  81 60.672 83.408 65.88 ;
     RECT  83.408 2.148 83.512 69.132 ;
     RECT  83.512 2.418 83.704 68.862 ;
     RECT  83.704 41.904 83.801 44.472 ;
     RECT  83.704 45.696 83.801 50.952 ;
     RECT  83.704 62.208 83.801 64.92 ;
     RECT  83.704 2.832 83.873 33.96 ;
     RECT  83.801 47.328 83.873 50.952 ;
     RECT  83.873 2.88 84.017 33.96 ;
     RECT  83.873 47.328 84.017 49.08 ;
     RECT  83.801 41.904 84.035 43.416 ;
     RECT  83.801 62.208 84.125 64.728 ;
     RECT  83.873 50.112 84.269 50.952 ;
     RECT  84.125 62.208 84.269 62.232 ;
     RECT  84.035 42.768 84.305 43.416 ;
     RECT  84.017 47.712 84.341 49.08 ;
     RECT  84.269 50.304 84.341 50.952 ;
     RECT  84.125 63.6 84.377 64.728 ;
     RECT  84.377 63.6 84.413 64.104 ;
     RECT  83.801 45.696 84.449 46.104 ;
     RECT  84.017 2.928 84.557 33.96 ;
     RECT  84.305 42.768 84.601 42.792 ;
     RECT  83.801 44.448 84.611 44.472 ;
     RECT  84.413 64.08 84.665 64.104 ;
     RECT  84.341 48.768 84.701 49.08 ;
     RECT  84.449 45.696 84.757 46.008 ;
     RECT  84.757 44.928 84.845 46.008 ;
     RECT  84.341 47.712 84.917 47.736 ;
     RECT  84.341 50.304 85.061 50.424 ;
     RECT  84.701 48.96 85.241 49.08 ;
     RECT  84.845 45.744 85.457 46.008 ;
     RECT  85.457 45.744 85.493 45.768 ;
     RECT  85.061 50.4 85.565 50.424 ;
     RECT  84.557 3.648 85.921 33.96 ;
     RECT  85.921 3.456 86.141 33.96 ;
     RECT  85.241 49.056 86.177 49.08 ;
     RECT  86.141 3.456 86.285 9 ;
     RECT  86.285 3.456 86.357 8.904 ;
     RECT  86.141 10.128 86.929 33.96 ;
     RECT  83.704 34.992 86.929 35.016 ;
     RECT  86.929 10.128 87.149 35.016 ;
     RECT  87.721 35.328 87.805 35.496 ;
     RECT  87.721 0.576 88.225 0.6 ;
     RECT  87.149 10.128 88.225 33.96 ;
     RECT  86.357 3.456 88.357 8.856 ;
     RECT  88.357 3.456 88.369 9.048 ;
     RECT  88.369 3.312 88.549 9.048 ;
     RECT  88.225 0.576 88.553 0.696 ;
     RECT  88.549 3.024 88.808 9.048 ;
     RECT  88.225 10.08 88.808 33.96 ;
     RECT  87.805 35.472 88.808 35.496 ;
     RECT  83.704 36.768 88.808 36.792 ;
     RECT  88.808 2.148 88.912 69.132 ;
     RECT  88.912 2.418 89.104 68.862 ;
     RECT  89.104 35.472 89.315 35.496 ;
     RECT  89.104 3.648 89.699 33.96 ;
     RECT  89.699 3.648 90.035 33.288 ;
     RECT  90.035 3.648 90.169 21.816 ;
     RECT  88.553 0.576 91.091 0.6 ;
     RECT  90.035 22.896 91.109 33.288 ;
     RECT  91.109 22.896 91.181 33.144 ;
     RECT  90.169 2.88 91.325 21.816 ;
     RECT  91.325 3.312 91.541 21.816 ;
     RECT  91.244 0.528 91.571 0.552 ;
     RECT  91.541 3.312 91.649 13.128 ;
     RECT  91.649 3.312 91.901 12.888 ;
     RECT  91.541 14.496 91.901 21.816 ;
     RECT  91.813 1.728 91.973 1.752 ;
     RECT  91.901 14.496 92.333 16.008 ;
     RECT  91.181 27.744 92.473 33.144 ;
     RECT  92.473 27.744 92.477 33.192 ;
     RECT  91.901 17.184 92.509 21.816 ;
     RECT  91.181 22.896 92.509 26.664 ;
     RECT  91.901 3.312 92.545 5.64 ;
     RECT  92.333 14.592 92.657 16.008 ;
     RECT  92.545 3.168 92.869 5.64 ;
     RECT  91.901 6.96 92.869 12.888 ;
     RECT  92.509 17.184 92.869 26.664 ;
     RECT  92.657 14.976 92.941 16.008 ;
     RECT  92.053 0.576 92.963 1.224 ;
     RECT  92.869 3.168 93.049 13.032 ;
     RECT  92.963 0.576 93.125 0.648 ;
     RECT  92.477 27.84 93.203 33.192 ;
     RECT  92.941 14.976 93.205 16.104 ;
     RECT  92.869 17.088 93.205 26.664 ;
     RECT  93.049 2.88 93.265 13.032 ;
     RECT  93.205 14.976 93.733 26.664 ;
     RECT  93.203 27.84 93.733 30.6 ;
     RECT  93.733 14.976 93.769 30.6 ;
     RECT  93.203 31.728 93.781 33.192 ;
     RECT  93.769 14.208 93.884 30.6 ;
     RECT  93.265 2.256 94.028 13.032 ;
     RECT  93.884 14.16 94.028 30.6 ;
     RECT  94.028 2.256 94.208 30.6 ;
     RECT  93.781 31.728 94.208 33.288 ;
     RECT  89.104 36.768 94.208 36.792 ;
     RECT  94.201 59.76 94.208 59.784 ;
     RECT  94.208 2.148 94.312 69.132 ;
     RECT  94.312 2.148 94.357 68.862 ;
     RECT  94.357 1.68 94.504 68.862 ;
     RECT  94.504 13.632 94.601 21.768 ;
     RECT  94.504 22.752 94.643 30.6 ;
     RECT  94.504 1.68 94.673 12.552 ;
     RECT  94.601 13.776 94.739 21.768 ;
     RECT  93.329 0.096 94.745 0.12 ;
     RECT  94.643 22.752 94.828 23.352 ;
     RECT  94.739 13.776 94.925 20.664 ;
     RECT  94.643 24.672 94.925 30.6 ;
     RECT  94.828 22.8 95.069 23.352 ;
     RECT  94.673 1.68 95.171 5.544 ;
     RECT  95.171 1.68 95.357 1.704 ;
     RECT  94.885 0.576 95.365 0.6 ;
     RECT  94.504 32.736 95.497 33.288 ;
     RECT  95.171 2.928 95.501 5.544 ;
     RECT  94.673 6.576 95.677 12.552 ;
     RECT  94.925 13.776 95.677 16.392 ;
     RECT  94.925 24.672 95.701 30.312 ;
     RECT  95.497 31.872 95.708 33.288 ;
     RECT  95.533 34.8 95.708 34.824 ;
     RECT  94.504 54.144 95.708 54.168 ;
     RECT  95.708 31.872 95.713 34.824 ;
     RECT  95.713 31.872 95.795 35.352 ;
     RECT  95.708 53.568 95.795 54.168 ;
     RECT  95.501 3.216 95.825 5.544 ;
     RECT  94.504 65.232 95.843 65.256 ;
     RECT  94.504 68.4 95.853 68.424 ;
     RECT  95.365 0.576 95.893 1.176 ;
     RECT  95.677 6.576 95.969 16.392 ;
     RECT  95.069 22.8 95.969 22.824 ;
     RECT  95.893 0.096 96.113 1.176 ;
     RECT  95.969 10.32 96.217 16.392 ;
     RECT  94.925 17.808 96.217 20.664 ;
     RECT  96.217 10.32 96.257 20.664 ;
     RECT  95.497 50.4 96.277 50.424 ;
     RECT  96.257 10.704 96.293 20.664 ;
     RECT  96.277 50.4 96.323 51.24 ;
     RECT  96.293 10.704 96.329 18.984 ;
     RECT  95.749 63.6 96.329 63.624 ;
     RECT  96.293 20.544 96.361 20.664 ;
     RECT  94.739 21.648 96.361 21.768 ;
     RECT  95.701 23.904 96.361 30.312 ;
     RECT  96.329 10.704 96.509 17.832 ;
     RECT  96.113 0.096 96.545 0.6 ;
     RECT  95.795 31.872 96.577 34.008 ;
     RECT  95.825 3.216 96.649 5.496 ;
     RECT  96.361 23.808 96.716 30.312 ;
     RECT  96.577 31.296 96.716 34.008 ;
     RECT  96.545 0.48 96.725 0.6 ;
     RECT  96.716 23.808 96.803 34.008 ;
     RECT  96.649 2.832 96.829 5.496 ;
     RECT  96.361 20.544 96.86 21.768 ;
     RECT  96.803 31.296 96.899 34.008 ;
     RECT  96.812 47.28 96.899 47.304 ;
     RECT  95.756 48.816 96.901 48.84 ;
     RECT  95.969 6.576 96.905 9.24 ;
     RECT  96.829 2.736 96.941 5.496 ;
     RECT  96.509 12.528 96.941 17.832 ;
     RECT  96.899 31.872 96.947 31.896 ;
     RECT  96.901 48 96.947 48.84 ;
     RECT  96.947 48 96.988 48.024 ;
     RECT  94.504 44.64 97.009 44.664 ;
     RECT  96.803 23.808 97.081 30.312 ;
     RECT  96.941 12.528 97.085 17.16 ;
     RECT  97.109 46.752 97.141 46.776 ;
     RECT  97.009 44.112 97.187 44.664 ;
     RECT  96.253 58.512 97.187 58.536 ;
     RECT  94.504 59.76 97.187 59.784 ;
     RECT  97.081 23.664 97.193 30.312 ;
     RECT  97.141 46.272 97.193 46.776 ;
     RECT  96.905 6.672 97.261 9.24 ;
     RECT  97.193 23.664 97.301 29.208 ;
     RECT  94.504 36.768 97.333 36.792 ;
     RECT  94.504 40.416 97.333 40.44 ;
     RECT  96.829 62.736 97.34 62.76 ;
     RECT  96.86 20.544 97.369 22.344 ;
     RECT  97.301 23.664 97.369 25.272 ;
     RECT  96.899 33.024 97.373 34.008 ;
     RECT  97.333 36.432 97.379 37.608 ;
     RECT  97.333 40.416 97.379 41.4 ;
     RECT  97.141 57.312 97.381 57.336 ;
     RECT  95.749 52.56 97.409 52.584 ;
     RECT  97.381 56.4 97.427 57.336 ;
     RECT  97.34 62.16 97.427 62.76 ;
     RECT  97.193 30.288 97.445 30.312 ;
     RECT  97.379 37.584 97.475 37.608 ;
     RECT  96.757 38.784 97.475 38.808 ;
     RECT  97.333 42.432 97.475 42.456 ;
     RECT  97.187 44.112 97.475 44.136 ;
     RECT  97.427 62.64 97.475 62.76 ;
     RECT  95.797 67.296 97.475 67.32 ;
     RECT  97.369 20.544 97.549 25.272 ;
     RECT  97.549 20.16 97.585 25.272 ;
     RECT  97.585 20.064 97.619 25.272 ;
     RECT  96.941 3.408 97.625 5.496 ;
     RECT  96.725 0.48 97.649 0.552 ;
     RECT  96.329 18.96 97.729 18.984 ;
     RECT  97.619 20.064 97.729 21.672 ;
     RECT  96.509 10.704 97.733 11.064 ;
     RECT  97.373 33.072 97.981 34.008 ;
     RECT  97.085 15.216 98.017 17.16 ;
     RECT  97.729 18.96 98.017 21.672 ;
     RECT  97.625 3.984 98.093 5.496 ;
     RECT  97.085 12.528 98.097 13.656 ;
     RECT  98.017 15.216 98.097 21.672 ;
     RECT  95.795 35.328 98.125 35.352 ;
     RECT  97.261 6.672 98.129 9.72 ;
     RECT  98.097 12.528 98.129 21.672 ;
     RECT  97.981 33.072 98.129 34.152 ;
     RECT  97.733 10.704 98.165 10.728 ;
     RECT  97.301 26.304 98.195 29.208 ;
     RECT  98.129 7.392 98.197 9.72 ;
     RECT  98.195 29.04 98.233 29.208 ;
     RECT  98.125 35.136 98.237 35.352 ;
     RECT  97.619 22.656 98.413 25.272 ;
     RECT  98.195 26.304 98.413 27.672 ;
     RECT  98.413 22.656 98.417 27.672 ;
     RECT  98.341 47.616 98.425 47.64 ;
     RECT  98.093 4.368 98.449 5.496 ;
     RECT  98.197 7.392 98.483 10.44 ;
     RECT  98.449 4.368 98.489 5.544 ;
     RECT  98.417 22.656 98.489 26.232 ;
     RECT  98.489 4.512 98.521 5.544 ;
     RECT  98.129 16.368 98.531 21.672 ;
     RECT  98.129 12.528 98.629 15.288 ;
     RECT  98.531 16.368 98.633 20.568 ;
     RECT  98.531 21.648 98.633 21.672 ;
     RECT  98.237 35.136 98.633 35.256 ;
     RECT  97.649 0.096 98.813 0.552 ;
     RECT  98.489 22.656 98.917 22.776 ;
     RECT  98.129 33.072 98.989 33.144 ;
     RECT  98.813 0.528 99.011 0.552 ;
     RECT  97.141 1.728 99.209 1.752 ;
     RECT  98.489 23.808 99.385 26.232 ;
     RECT  98.417 27.6 99.385 27.672 ;
     RECT  98.483 7.488 99.452 10.44 ;
     RECT  98.629 11.712 99.452 15.288 ;
     RECT  98.521 4.512 99.565 5.784 ;
     RECT  99.565 3.936 99.608 5.88 ;
     RECT  99.452 7.488 99.608 15.288 ;
     RECT  98.633 16.368 99.608 18.456 ;
     RECT  98.633 19.728 99.608 20.568 ;
     RECT  98.917 22.272 99.608 22.776 ;
     RECT  99.385 23.808 99.608 27.672 ;
     RECT  98.233 29.04 99.608 29.256 ;
     RECT  98.989 33.024 99.608 33.144 ;
     RECT  98.129 34.128 99.608 34.152 ;
     RECT  98.633 35.232 99.608 35.256 ;
     RECT  97.379 36.432 99.608 36.456 ;
     RECT  97.379 41.376 99.608 41.4 ;
     RECT  97.193 46.272 99.608 46.296 ;
     RECT  96.323 51.216 99.608 51.24 ;
     RECT  97.427 56.4 99.608 56.424 ;
     RECT  97.141 60.96 99.608 60.984 ;
     RECT  97.429 66.096 99.608 66.12 ;
     RECT  99.608 2.148 99.712 69.132 ;
     RECT  99.712 2.418 99.904 68.862 ;
     RECT  99.904 34.128 99.929 34.152 ;
     RECT  99.904 29.04 99.965 29.256 ;
     RECT  99.904 8.448 100.001 8.472 ;
     RECT  99.904 3.936 100.067 6.84 ;
     RECT  100.067 4.512 100.109 6.84 ;
     RECT  99.965 29.232 100.109 29.256 ;
     RECT  99.904 12.528 100.217 12.552 ;
     RECT  99.904 22.752 100.217 22.776 ;
     RECT  100.109 5.472 100.253 6.84 ;
     RECT  100.253 5.52 100.361 6.84 ;
     RECT  99.904 33.024 100.361 33.048 ;
     RECT  99.904 19.872 100.397 19.896 ;
     RECT  99.904 35.232 100.397 35.256 ;
     RECT  100.361 5.568 100.433 6.84 ;
     RECT  99.904 25.824 100.433 25.848 ;
     RECT  100.433 5.76 100.933 6.84 ;
     RECT  100.933 5.76 100.937 7.8 ;
     RECT  99.904 27.168 101.153 27.192 ;
     RECT  100.937 6.864 101.225 7.8 ;
     RECT  100.937 5.76 101.297 5.784 ;
     RECT  101.149 1.584 103.644 1.608 ;
     RECT  102.049 2.832 103.644 2.856 ;
     RECT  102.481 4.08 103.644 4.104 ;
     RECT  102.013 5.328 103.644 5.352 ;
     RECT  102.553 6.576 103.644 6.6 ;
     RECT  101.225 7.776 103.644 7.8 ;
     RECT  101.977 9.024 103.644 9.048 ;
     RECT  102.013 10.272 103.644 10.296 ;
     RECT  102.013 11.52 103.644 11.544 ;
     RECT  102.481 12.72 103.644 12.744 ;
     RECT  102.013 13.968 103.644 13.992 ;
     RECT  101.977 15.216 103.644 15.24 ;
     RECT  102.013 16.464 103.644 16.488 ;
     RECT  102.553 17.712 103.644 17.736 ;
     RECT  102.553 18.912 103.644 18.936 ;
     RECT  103.561 20.16 103.644 20.184 ;
     RECT  102.553 21.408 103.644 21.432 ;
     RECT  101.437 22.656 103.644 22.68 ;
     RECT  102.553 23.856 103.644 23.88 ;
     RECT  102.553 25.104 103.644 25.128 ;
     RECT  102.553 26.352 103.644 26.376 ;
     RECT  102.013 27.6 103.644 27.624 ;
     RECT  101.977 28.848 103.644 28.872 ;
     RECT  101.977 30.048 103.644 30.072 ;
     RECT  103.561 31.296 103.644 31.32 ;
     RECT  101.977 32.544 103.644 32.568 ;
     RECT  101.437 33.792 103.644 33.816 ;
     RECT  102.553 34.992 103.644 35.016 ;
     RECT  102.553 36.24 103.644 36.264 ;
     RECT  101.977 37.488 103.644 37.512 ;
     RECT  101.437 38.736 103.644 38.76 ;
     RECT  101.977 39.936 103.644 39.96 ;
     RECT  102.553 41.184 103.644 41.208 ;
     RECT  102.553 42.432 103.644 42.456 ;
     RECT  102.481 43.68 103.644 43.704 ;
     RECT  101.977 44.928 103.644 44.952 ;
     RECT  102.553 46.128 103.644 46.152 ;
     RECT  101.977 47.376 103.644 47.4 ;
     RECT  102.553 48.624 103.644 48.648 ;
     RECT  101.437 49.872 103.644 49.896 ;
     RECT  102.553 51.072 103.644 51.096 ;
     RECT  103.561 52.32 103.644 52.344 ;
     RECT  102.553 53.568 103.644 53.592 ;
     RECT  101.905 54.816 103.644 54.84 ;
     RECT  102.553 56.064 103.644 56.088 ;
     RECT  101.977 57.264 103.644 57.288 ;
     RECT  102.553 58.512 103.644 58.536 ;
     RECT  101.977 59.76 103.644 59.784 ;
     RECT  102.589 61.008 103.644 61.032 ;
     RECT  102.553 62.208 103.644 62.232 ;
     RECT  101.977 63.456 103.644 63.48 ;
     RECT  102.553 64.704 103.644 64.728 ;
     RECT  102.553 65.952 103.644 65.976 ;
     RECT  103.561 67.152 103.644 67.176 ;
     RECT  102.589 68.4 103.644 68.424 ;
     RECT  100.717 69.648 103.644 69.672 ;
    LAYER M5 ;
     RECT  42 0.016 49.944 0.085 ;
     RECT  74.688 0.016 82.632 0.131 ;
     RECT  91.056 0.016 99 0.563 ;
     RECT  91.056 0.563 97.944 0.611 ;
     RECT  25.632 0.016 33.576 1.187 ;
     RECT  58.32 0.016 66.264 1.187 ;
     RECT  74.928 0.131 82.632 1.187 ;
     RECT  91.824 0.611 95.4 1.187 ;
     RECT  91.824 1.187 95.16 1.235 ;
     RECT  9.312 0.016 17.256 1.763 ;
     RECT  25.632 1.187 33.336 1.763 ;
     RECT  42 0.085 50.616 1.763 ;
     RECT  58.608 1.187 62.952 1.763 ;
     RECT  63.984 1.187 66.264 1.763 ;
     RECT  74.928 1.187 82.392 1.763 ;
     RECT  91.824 1.235 91.848 1.763 ;
     RECT  97.152 0.611 97.944 1.763 ;
     RECT  45.312 1.763 45.912 1.811 ;
     RECT  47.376 1.763 49.176 1.811 ;
     RECT  60.624 1.763 62.112 1.811 ;
     RECT  66 1.763 66.264 1.811 ;
     RECT  2.304 2.053 2.328 2.137 ;
     RECT  50.592 1.763 50.616 2.137 ;
     RECT  66.24 1.811 66.264 2.137 ;
     RECT  88.416 0.565 88.44 2.137 ;
     RECT  2.304 2.137 2.52 2.151 ;
     RECT  7.8 2.137 7.92 2.151 ;
     RECT  18.6 2.137 18.72 2.151 ;
     RECT  24 2.137 24.12 2.151 ;
     RECT  34.8 2.137 34.92 2.151 ;
     RECT  40.2 2.137 40.32 2.151 ;
     RECT  50.592 2.137 51.12 2.151 ;
     RECT  56.4 2.137 56.52 2.151 ;
     RECT  66.24 2.137 67.32 2.151 ;
     RECT  72.6 2.137 72.72 2.151 ;
     RECT  83.4 2.137 83.52 2.151 ;
     RECT  88.416 2.137 88.92 2.151 ;
     RECT  99.6 2.137 99.72 2.151 ;
     RECT  17.232 1.763 17.256 2.245 ;
     RECT  18.6 2.151 18.912 2.245 ;
     RECT  92.928 1.235 95.16 2.291 ;
     RECT  28.944 1.763 30.84 2.821 ;
     RECT  12.624 1.763 14.184 2.915 ;
     RECT  15.936 1.763 15.96 2.915 ;
     RECT  17.232 2.245 18.912 2.915 ;
     RECT  25.632 1.763 26.184 2.915 ;
     RECT  28.944 2.821 31.32 2.915 ;
     RECT  32.304 1.763 32.328 2.915 ;
     RECT  43.008 1.763 43.032 2.915 ;
     RECT  47.376 1.811 47.64 2.915 ;
     RECT  48.912 1.811 49.176 2.915 ;
     RECT  58.608 1.763 58.632 2.915 ;
     RECT  66.24 2.151 67.512 2.915 ;
     RECT  76.752 1.763 76.776 2.915 ;
     RECT  80.832 1.763 80.856 2.915 ;
     RECT  47.616 2.915 47.64 2.963 ;
     RECT  40.2 2.151 40.512 3.301 ;
     RECT  24 2.151 24.312 3.397 ;
     RECT  2.304 2.151 2.712 3.443 ;
     RECT  48.96 2.915 48.984 3.443 ;
     RECT  96.288 3.349 96.312 3.539 ;
     RECT  18 2.915 18.912 3.587 ;
     RECT  72.6 2.151 72.912 3.829 ;
     RECT  34.8 2.151 35.112 3.877 ;
     RECT  99.6 2.151 99.912 3.925 ;
     RECT  9.504 3.205 9.528 3.971 ;
     RECT  13.104 2.915 13.656 3.971 ;
     RECT  67.2 2.915 67.512 3.973 ;
     RECT  83.4 2.151 83.712 3.973 ;
     RECT  45.6 1.811 45.912 4.021 ;
     RECT  24 3.397 25.032 4.115 ;
     RECT  34.704 3.877 35.208 4.115 ;
     RECT  43.296 3.109 43.32 4.165 ;
     RECT  37.44 3.733 37.464 4.213 ;
     RECT  38.64 4.069 38.664 4.213 ;
     RECT  40.08 3.301 40.512 4.213 ;
     RECT  15.024 3.925 15.048 4.259 ;
     RECT  56.4 2.151 56.712 4.261 ;
     RECT  34.704 4.115 35.112 4.307 ;
     RECT  37.44 4.213 38.664 4.355 ;
     RECT  40.08 4.213 40.968 4.357 ;
     RECT  36.288 3.973 36.312 4.403 ;
     RECT  37.44 4.355 37.56 4.403 ;
     RECT  39.936 4.357 40.968 4.451 ;
     RECT  43.296 4.165 43.992 4.499 ;
     RECT  29.4 2.915 29.712 4.501 ;
     RECT  30.816 2.915 31.32 4.501 ;
     RECT  29.4 4.501 31.32 4.549 ;
     RECT  45.504 4.021 45.912 4.595 ;
     RECT  67.104 3.973 67.512 4.643 ;
     RECT  71.808 3.829 72.912 4.643 ;
     RECT  83.4 3.973 84.504 4.643 ;
     RECT  38.64 4.355 38.664 4.691 ;
     RECT  61.8 1.811 62.112 4.789 ;
     RECT  67.2 4.643 67.512 4.789 ;
     RECT  39.936 4.451 40.824 4.837 ;
     RECT  98.448 4.501 98.472 4.837 ;
     RECT  99.6 3.925 100.056 4.837 ;
     RECT  5.52 4.021 5.544 4.883 ;
     RECT  47.328 4.549 47.448 4.883 ;
     RECT  53.04 4.357 53.064 4.883 ;
     RECT  29.28 4.549 31.32 4.885 ;
     RECT  59.616 3.829 59.64 4.931 ;
     RECT  24 4.115 24.648 5.027 ;
     RECT  13.104 3.971 13.512 5.029 ;
     RECT  98.448 4.837 100.056 5.075 ;
     RECT  2.4 3.443 2.712 5.077 ;
     RECT  18.336 3.587 18.912 5.077 ;
     RECT  20.592 4.885 20.616 5.077 ;
     RECT  47.424 4.883 47.448 5.077 ;
     RECT  61.8 4.789 62.28 5.077 ;
     RECT  98.448 5.075 98.472 5.077 ;
     RECT  34.8 4.307 35.112 5.125 ;
     RECT  37.44 4.403 37.512 5.125 ;
     RECT  61.68 5.077 62.28 5.171 ;
     RECT  61.68 5.171 62.112 5.173 ;
     RECT  13.056 5.029 13.512 5.221 ;
     RECT  22.032 4.357 22.056 5.267 ;
     RECT  37.344 5.125 37.512 5.267 ;
     RECT  54.096 4.789 54.12 5.269 ;
     RECT  34.8 5.125 36.072 5.315 ;
     RECT  39.696 4.837 40.824 5.365 ;
     RECT  39.264 5.365 40.824 5.413 ;
     RECT  13.056 5.221 13.608 5.461 ;
     RECT  56.4 4.261 56.808 5.461 ;
     RECT  18.336 5.077 20.616 5.507 ;
     RECT  39.264 5.413 40.968 5.603 ;
     RECT  37.344 5.267 37.464 5.605 ;
     RECT  50.592 2.151 51.312 5.605 ;
     RECT  56.4 5.461 56.904 5.605 ;
     RECT  53.136 5.269 54.12 5.651 ;
     RECT  43.296 4.499 43.896 5.653 ;
     RECT  47.424 5.077 47.784 5.699 ;
     RECT  54.096 5.651 54.12 5.701 ;
     RECT  61.488 5.173 62.112 5.701 ;
     RECT  18.336 5.507 19.704 5.747 ;
     RECT  70.416 4.261 70.44 5.747 ;
     RECT  88.416 2.151 89.112 5.747 ;
     RECT  64.944 5.029 64.968 5.749 ;
     RECT  67.2 4.789 68.088 5.795 ;
     RECT  45.6 4.595 45.912 5.797 ;
     RECT  78 1.763 78.312 5.797 ;
     RECT  13.056 5.461 14.472 5.845 ;
     RECT  43.296 5.653 43.992 5.893 ;
     RECT  45.504 5.797 45.912 5.893 ;
     RECT  99.6 5.075 100.056 5.893 ;
     RECT  37.056 5.605 37.464 5.987 ;
     RECT  54.096 5.701 54.744 5.987 ;
     RECT  43.296 5.893 45.912 6.035 ;
     RECT  43.296 6.035 43.896 6.037 ;
     RECT  17.136 5.845 17.16 6.083 ;
     RECT  64.944 5.749 65.304 6.181 ;
     RECT  5.664 5.173 5.688 6.229 ;
     RECT  47.76 5.699 47.784 6.229 ;
     RECT  75.6 3.781 75.624 6.323 ;
     RECT  77.808 5.797 78.312 6.323 ;
     RECT  81.888 5.029 81.912 6.323 ;
     RECT  45.6 6.035 45.912 6.373 ;
     RECT  87.312 5.461 87.336 6.373 ;
     RECT  47.76 6.229 48.12 6.419 ;
     RECT  12.288 5.845 14.472 6.515 ;
     RECT  87.072 6.373 87.336 6.515 ;
     RECT  99.6 5.893 100.2 6.563 ;
     RECT  5.616 6.229 5.688 6.613 ;
     RECT  72.48 4.643 72.912 6.709 ;
     RECT  11.04 5.125 11.064 6.803 ;
     RECT  28.8 4.885 31.32 6.805 ;
     RECT  43.152 6.037 43.896 6.805 ;
     RECT  56.4 5.605 57.336 6.805 ;
     RECT  64.944 6.181 65.448 6.805 ;
     RECT  37.44 5.987 37.464 6.899 ;
     RECT  52.992 6.757 53.016 6.899 ;
     RECT  42.912 6.805 43.896 7.043 ;
     RECT  50.112 5.605 51.312 7.141 ;
     RECT  5.616 6.613 6.024 7.189 ;
     RECT  28.8 6.805 31.368 7.189 ;
     RECT  12.288 6.515 13.896 7.235 ;
     RECT  39.936 5.603 40.968 7.235 ;
     RECT  24 5.027 24.456 7.283 ;
     RECT  39.984 7.235 40.968 7.283 ;
     RECT  5.472 7.189 6.024 7.285 ;
     RECT  28.8 7.189 31.608 7.285 ;
     RECT  28.8 7.285 31.8 7.333 ;
     RECT  49.488 7.141 51.312 7.333 ;
     RECT  2.4 5.077 3.48 7.381 ;
     RECT  25.632 7.333 25.656 7.381 ;
     RECT  28.704 7.333 31.8 7.381 ;
     RECT  83.4 4.643 83.712 7.381 ;
     RECT  90.912 7.333 90.936 7.381 ;
     RECT  72.432 6.709 72.912 7.427 ;
     RECT  74.112 6.133 74.136 7.427 ;
     RECT  98.064 5.077 98.472 7.427 ;
     RECT  88.8 5.747 89.112 7.429 ;
     RECT  5.424 7.285 6.024 7.475 ;
     RECT  42.912 7.043 43.8 7.475 ;
     RECT  64.704 6.805 65.448 7.619 ;
     RECT  13.056 7.235 13.896 7.669 ;
     RECT  5.424 7.475 5.64 7.715 ;
     RECT  25.44 7.381 25.656 7.715 ;
     RECT  72.48 7.427 72.912 7.715 ;
     RECT  81.792 7.141 81.816 7.717 ;
     RECT  83.4 7.381 84.024 7.717 ;
     RECT  87.312 6.515 87.336 7.717 ;
     RECT  90.768 7.381 90.936 7.717 ;
     RECT  79.344 4.837 79.368 7.763 ;
     RECT  56.208 6.805 57.336 7.811 ;
     RECT  38.832 6.229 38.856 7.813 ;
     RECT  48.096 6.419 48.12 7.813 ;
     RECT  87.312 7.717 87.72 7.813 ;
     RECT  24 7.283 24.312 7.861 ;
     RECT  28.704 7.381 31.848 7.861 ;
     RECT  49.488 7.333 52.056 7.861 ;
     RECT  67.2 5.795 67.848 7.861 ;
     RECT  92.928 2.291 94.512 7.909 ;
     RECT  25.44 7.715 25.464 7.955 ;
     RECT  83.4 7.717 84.648 7.955 ;
     RECT  87.168 7.813 87.72 7.955 ;
     RECT  56.4 7.811 57.336 7.957 ;
     RECT  49.392 7.861 52.056 8.003 ;
     RECT  87.168 7.955 87.336 8.003 ;
     RECT  92.928 7.909 94.92 8.003 ;
     RECT  96.288 6.613 96.312 8.003 ;
     RECT  92.976 8.003 94.92 8.051 ;
     RECT  50.592 8.003 52.056 8.147 ;
     RECT  79.44 8.149 79.464 8.291 ;
     RECT  6.72 8.197 6.744 8.293 ;
     RECT  7.8 2.151 8.112 8.293 ;
     RECT  45.6 6.373 46.248 8.435 ;
     RECT  54.336 5.987 54.744 8.435 ;
     RECT  39.984 7.283 40.776 8.437 ;
     RECT  72.6 7.715 72.912 8.437 ;
     RECT  78 6.323 78.312 8.485 ;
     RECT  99.6 6.563 99.912 8.485 ;
     RECT  6.72 8.293 8.112 8.531 ;
     RECT  13.056 7.669 14.136 8.533 ;
     RECT  2.304 7.381 3.48 8.579 ;
     RECT  43.776 7.475 43.8 8.579 ;
     RECT  53.184 7.909 53.208 8.579 ;
     RECT  77.904 8.485 78.312 8.627 ;
     RECT  87.312 8.003 87.336 8.675 ;
     RECT  47.616 7.813 48.12 8.725 ;
     RECT  64.128 8.437 64.152 8.725 ;
     RECT  72.6 8.437 73.032 8.725 ;
     RECT  74.64 8.293 74.664 8.725 ;
     RECT  23.856 7.861 24.312 8.819 ;
     RECT  72.6 8.725 74.664 8.819 ;
     RECT  47.28 8.725 48.12 8.821 ;
     RECT  65.28 7.619 65.448 8.821 ;
     RECT  64.128 8.725 64.296 8.867 ;
     RECT  72.6 8.819 73.704 8.867 ;
     RECT  85.056 8.725 85.08 8.867 ;
     RECT  13.008 8.533 14.136 8.869 ;
     RECT  90.768 7.717 91.176 8.869 ;
     RECT  56.4 7.957 58.152 8.917 ;
     RECT  12 7.957 12.024 8.963 ;
     RECT  88.8 7.429 89.496 9.013 ;
     RECT  13.008 8.869 14.664 9.059 ;
     RECT  39.984 8.437 41.256 9.061 ;
     RECT  56.4 8.917 58.248 9.061 ;
     RECT  83.4 7.955 84.024 9.061 ;
     RECT  47.184 8.821 48.12 9.107 ;
     RECT  55.824 9.061 58.248 9.107 ;
     RECT  72.6 8.867 73.032 9.107 ;
     RECT  94.2 8.051 94.92 9.107 ;
     RECT  70.656 8.821 70.68 9.109 ;
     RECT  38.592 7.813 38.856 9.155 ;
     RECT  28.704 7.861 31.896 9.203 ;
     RECT  70.416 9.109 70.68 9.203 ;
     RECT  23.904 8.819 24.312 9.253 ;
     RECT  2.4 8.579 3.48 9.299 ;
     RECT  28.8 9.203 31.896 9.299 ;
     RECT  18.336 5.747 18.912 9.301 ;
     RECT  88.368 9.013 89.496 9.349 ;
     RECT  90.576 8.869 91.176 9.349 ;
     RECT  47.28 9.107 48.12 9.395 ;
     RECT  23.904 9.253 24.456 9.443 ;
     RECT  45.6 8.435 46.056 9.443 ;
     RECT  34.8 5.315 35.88 9.493 ;
     RECT  37.056 8.821 37.08 9.493 ;
     RECT  70.416 9.203 70.44 9.539 ;
     RECT  7.296 8.531 8.112 9.541 ;
     RECT  67.2 7.861 68.424 9.541 ;
     RECT  7.296 9.541 8.568 9.587 ;
     RECT  67.2 9.541 68.856 9.587 ;
     RECT  34.8 9.493 37.08 9.635 ;
     RECT  97.488 8.005 97.512 9.637 ;
     RECT  88.368 9.349 91.176 9.685 ;
     RECT  13.104 9.059 14.664 9.731 ;
     RECT  29.4 9.299 31.896 9.731 ;
     RECT  64.128 8.867 64.152 9.731 ;
     RECT  67.2 9.587 67.848 9.731 ;
     RECT  97.488 9.637 98.376 9.731 ;
     RECT  29.4 9.731 30.36 9.779 ;
     RECT  92.976 8.051 93 9.781 ;
     RECT  94.2 9.107 94.512 9.781 ;
     RECT  81.744 7.717 81.816 9.877 ;
     RECT  83.184 9.061 84.024 9.877 ;
     RECT  23.904 9.443 24.408 9.923 ;
     RECT  54.336 8.435 54.36 9.925 ;
     RECT  65.28 8.821 66.168 9.925 ;
     RECT  98.352 9.731 98.376 9.925 ;
     RECT  99.456 8.485 99.912 9.925 ;
     RECT  65.184 9.925 66.168 9.973 ;
     RECT  67.2 9.731 67.8 9.973 ;
     RECT  88.368 9.685 91.224 10.021 ;
     RECT  80.4 9.877 80.424 10.115 ;
     RECT  58.704 9.877 58.728 10.163 ;
     RECT  88.368 10.021 91.32 10.163 ;
     RECT  43.296 8.677 43.464 10.165 ;
     RECT  31.536 9.731 31.896 10.307 ;
     RECT  37.056 9.635 37.08 10.307 ;
     RECT  60.96 5.701 62.112 10.307 ;
     RECT  68.832 9.587 68.856 10.307 ;
     RECT  92.976 9.781 94.512 10.307 ;
     RECT  47.28 9.395 47.496 10.357 ;
     RECT  24 9.923 24.408 10.403 ;
     RECT  5.472 7.715 5.64 10.453 ;
     RECT  65.184 9.973 67.8 10.453 ;
     RECT  34.8 9.635 35.88 10.499 ;
     RECT  39.888 9.061 41.256 10.549 ;
     RECT  7.8 9.587 8.568 10.643 ;
     RECT  55.824 9.107 57.336 10.693 ;
     RECT  53.904 9.925 54.36 10.835 ;
     RECT  81.744 9.877 84.648 10.837 ;
     RECT  85.872 10.453 85.896 10.837 ;
     RECT  47.28 10.357 47.688 10.883 ;
     RECT  65.04 10.453 67.8 10.931 ;
     RECT  72.6 9.107 72.912 10.933 ;
     RECT  88.368 10.163 91.224 10.979 ;
     RECT  88.368 10.979 90.888 11.075 ;
     RECT  78 8.627 78.312 11.125 ;
     RECT  5.424 10.453 5.64 11.171 ;
     RECT  63.264 10.981 63.288 11.171 ;
     RECT  13.104 9.731 14.136 11.173 ;
     RECT  79.728 10.981 79.752 11.173 ;
     RECT  26.304 10.165 26.328 11.219 ;
     RECT  2.4 9.299 2.712 11.221 ;
     RECT  47.376 10.883 47.688 11.267 ;
     RECT  42.96 10.165 43.464 11.317 ;
     RECT  42.336 11.317 43.464 11.363 ;
     RECT  39.792 10.549 41.256 11.365 ;
     RECT  42.336 11.363 43.176 11.365 ;
     RECT  55.824 10.693 58.104 11.365 ;
     RECT  31.536 10.307 31.56 11.459 ;
     RECT  50.592 8.147 51.312 11.461 ;
     RECT  93.936 10.307 94.512 11.509 ;
     RECT  88.368 11.075 90.6 11.555 ;
     RECT  49.392 8.003 49.416 11.557 ;
     RECT  18.192 9.301 18.912 11.605 ;
     RECT  45.6 9.443 45.912 11.653 ;
     RECT  17.376 11.605 18.912 11.747 ;
     RECT  54.144 10.835 54.36 11.749 ;
     RECT  55.488 11.365 58.104 11.749 ;
     RECT  65.04 10.931 67.512 11.749 ;
     RECT  39.792 11.365 43.176 11.891 ;
     RECT  61.008 10.307 62.112 11.939 ;
     RECT  12.288 11.173 14.136 11.941 ;
     RECT  96.288 11.173 96.312 11.941 ;
     RECT  18.192 11.747 18.912 12.037 ;
     RECT  9.504 10.645 9.528 12.085 ;
     RECT  59.568 10.165 59.592 12.085 ;
     RECT  12.288 11.941 14.184 12.131 ;
     RECT  93.12 11.509 94.512 12.133 ;
     RECT  79.728 11.173 80.664 12.181 ;
     RECT  81.744 10.837 85.896 12.181 ;
     RECT  20.64 10.981 20.664 12.227 ;
     RECT  79.728 12.181 85.896 12.227 ;
     RECT  38.592 9.155 38.616 12.229 ;
     RECT  49.008 11.557 49.416 12.229 ;
     RECT  50.496 11.461 51.312 12.229 ;
     RECT  54.144 11.749 58.104 12.229 ;
     RECT  59.568 12.085 60.216 12.229 ;
     RECT  93.12 12.133 94.68 12.275 ;
     RECT  63.6 12.037 63.624 12.277 ;
     RECT  78 11.125 78.648 12.325 ;
     RECT  64.992 11.749 67.512 12.373 ;
     RECT  44.352 12.277 44.376 12.419 ;
     RECT  76.944 12.325 78.648 12.467 ;
     RECT  33.456 10.789 33.48 12.517 ;
     RECT  34.8 10.499 35.352 12.517 ;
     RECT  49.008 12.229 51.312 12.517 ;
     RECT  88.8 11.555 90.6 12.517 ;
     RECT  96.144 11.941 96.312 12.517 ;
     RECT  5.472 11.171 5.64 12.563 ;
     RECT  33.456 12.517 35.352 12.563 ;
     RECT  54.144 12.229 60.216 12.563 ;
     RECT  75.456 12.229 75.48 12.563 ;
     RECT  96.144 12.517 96.504 12.563 ;
     RECT  2.304 11.221 2.712 12.755 ;
     RECT  70.896 12.517 70.92 12.805 ;
     RECT  64.992 12.373 68.376 12.851 ;
     RECT  83.184 12.227 85.896 13.043 ;
     RECT  38.592 12.229 39.048 13.045 ;
     RECT  40.032 11.891 43.176 13.045 ;
     RECT  85.872 13.043 85.896 13.045 ;
     RECT  9.504 12.085 9.576 13.139 ;
     RECT  38.592 13.045 43.176 13.139 ;
     RECT  48.768 12.517 51.312 13.139 ;
     RECT  66.384 12.851 68.376 13.139 ;
     RECT  79.728 12.227 81.528 13.331 ;
     RECT  98.352 9.925 99.912 13.333 ;
     RECT  70.656 12.805 70.92 13.379 ;
     RECT  13.2 12.131 14.184 13.525 ;
     RECT  22.464 7.669 22.488 13.715 ;
     RECT  4.032 12.517 4.056 13.811 ;
     RECT  13.2 13.525 14.52 13.813 ;
     RECT  18.192 12.037 19.224 13.859 ;
     RECT  70.656 13.379 70.68 13.859 ;
     RECT  93.12 12.275 94.512 13.861 ;
     RECT  76.944 12.467 78.312 13.907 ;
     RECT  83.184 13.043 84.792 13.909 ;
     RECT  63.504 12.277 63.624 14.101 ;
     RECT  64.992 12.851 65.304 14.101 ;
     RECT  96.288 12.563 96.504 14.101 ;
     RECT  7.8 10.643 8.112 14.197 ;
     RECT  24 10.403 24.312 14.197 ;
     RECT  33.456 12.563 35.112 14.197 ;
     RECT  49.968 13.139 51.312 14.197 ;
     RECT  78 13.907 78.312 14.197 ;
     RECT  79.728 13.331 80.568 14.197 ;
     RECT  33.456 14.197 35.304 14.243 ;
     RECT  85.872 13.045 86.04 14.243 ;
     RECT  13.2 13.813 15.288 14.291 ;
     RECT  45.6 11.653 46.008 14.291 ;
     RECT  24 14.197 25.08 14.339 ;
     RECT  98.112 13.333 99.912 14.387 ;
     RECT  2.4 12.755 2.712 14.389 ;
     RECT  24 14.339 24.312 14.677 ;
     RECT  47.664 11.267 47.688 14.725 ;
     RECT  48.768 13.139 48.792 14.725 ;
     RECT  71.184 14.629 71.208 14.725 ;
     RECT  5.616 12.563 5.64 14.773 ;
     RECT  39.024 13.139 43.176 14.773 ;
     RECT  49.92 14.197 51.312 14.773 ;
     RECT  87.12 14.437 87.144 14.821 ;
     RECT  7.8 14.197 8.52 14.867 ;
     RECT  20.736 14.245 20.76 14.867 ;
     RECT  27.936 14.341 27.96 14.915 ;
     RECT  32.016 14.197 32.04 14.915 ;
     RECT  63.504 14.101 65.304 14.965 ;
     RECT  76.944 13.907 76.968 15.059 ;
     RECT  49.92 14.773 51.432 15.107 ;
     RECT  72.6 10.933 73.32 15.109 ;
     RECT  75.216 14.965 75.24 15.205 ;
     RECT  66.384 13.139 68.328 15.251 ;
     RECT  72.6 15.109 73.56 15.251 ;
     RECT  75.072 15.205 75.24 15.251 ;
     RECT  63.264 14.965 65.304 15.301 ;
     RECT  66.384 15.251 68.04 15.301 ;
     RECT  71.184 14.725 71.352 15.301 ;
     RECT  93.12 13.861 94.728 15.347 ;
     RECT  47.664 14.725 48.792 15.443 ;
     RECT  87.12 14.821 87.24 15.443 ;
     RECT  33.456 14.243 33.48 15.445 ;
     RECT  34.512 14.243 35.304 15.445 ;
     RECT  61.296 11.939 62.112 15.445 ;
     RECT  63.264 15.301 68.04 15.445 ;
     RECT  18.192 13.859 18.912 15.491 ;
     RECT  39.024 14.773 43.944 15.491 ;
     RECT  29.4 9.779 30.024 15.493 ;
     RECT  48.768 15.443 48.792 15.493 ;
     RECT  78 14.197 80.568 15.493 ;
     RECT  75.072 15.251 75.192 15.587 ;
     RECT  61.296 15.445 68.04 15.683 ;
     RECT  78 15.493 80.76 15.683 ;
     RECT  13.2 14.291 14.52 15.829 ;
     RECT  70.944 15.301 71.352 15.829 ;
     RECT  64.992 15.683 68.04 15.875 ;
     RECT  88.8 12.517 91.224 15.973 ;
     RECT  13.104 15.829 14.52 16.019 ;
     RECT  28.56 15.493 30.024 16.019 ;
     RECT  96 14.101 96.504 16.019 ;
     RECT  33.456 15.445 35.304 16.261 ;
     RECT  2.4 14.389 3.336 16.403 ;
     RECT  33.456 16.261 36.12 16.403 ;
     RECT  13.104 16.019 13.512 16.547 ;
     RECT  78 15.683 80.568 16.645 ;
     RECT  85.872 14.243 85.896 16.739 ;
     RECT  70.368 15.829 71.352 16.789 ;
     RECT  5.616 14.773 6.264 16.835 ;
     RECT  14.496 16.019 14.52 16.835 ;
     RECT  18.24 15.491 18.912 16.883 ;
     RECT  25.296 16.645 25.32 16.883 ;
     RECT  19.92 15.637 19.944 16.885 ;
     RECT  33.456 16.403 35.304 16.885 ;
     RECT  69.408 16.789 71.352 16.931 ;
     RECT  48.768 15.493 48.984 17.027 ;
     RECT  9.504 13.139 9.528 17.029 ;
     RECT  98.352 14.387 99.912 17.029 ;
     RECT  9.504 17.029 9.816 17.075 ;
     RECT  50.592 15.107 51.432 17.077 ;
     RECT  52.8 12.901 52.824 17.077 ;
     RECT  54.336 12.563 60.216 17.077 ;
     RECT  61.296 15.683 63.672 17.077 ;
     RECT  93.216 15.347 94.728 17.077 ;
     RECT  33.072 16.885 35.304 17.123 ;
     RECT  76.944 16.981 76.968 17.123 ;
     RECT  50.16 17.077 51.432 17.171 ;
     RECT  78 16.645 80.952 17.171 ;
     RECT  52.8 17.077 53.064 17.219 ;
     RECT  54.336 17.077 63.672 17.267 ;
     RECT  92.88 17.077 94.728 17.267 ;
     RECT  48.768 17.027 48.792 17.413 ;
     RECT  9.792 17.075 9.816 17.605 ;
     RECT  13.2 16.547 13.512 17.605 ;
     RECT  16.992 15.925 17.016 17.605 ;
     RECT  23.904 14.677 24.312 17.605 ;
     RECT  29.4 16.019 30.024 17.605 ;
     RECT  88.8 15.973 91.56 17.605 ;
     RECT  65.184 15.875 68.04 17.651 ;
     RECT  87.12 15.443 87.144 17.653 ;
     RECT  5.616 16.835 5.64 17.699 ;
     RECT  47.664 15.443 47.688 17.699 ;
     RECT  96 16.019 96.024 17.797 ;
     RECT  54.336 17.267 60.216 17.843 ;
     RECT  45.6 14.291 45.912 17.845 ;
     RECT  78 17.171 80.568 17.891 ;
     RECT  82.464 13.909 84.792 17.893 ;
     RECT  87.12 17.653 87.24 17.939 ;
     RECT  33.456 17.123 35.304 17.941 ;
     RECT  16.992 17.605 17.496 17.989 ;
     RECT  48.672 17.413 48.792 17.989 ;
     RECT  50.16 17.171 51.312 17.989 ;
     RECT  75.168 15.587 75.192 17.989 ;
     RECT  61.248 17.267 63.672 18.133 ;
     RECT  16.176 17.989 17.496 18.181 ;
     RECT  23.52 17.605 24.312 18.181 ;
     RECT  25.44 18.133 25.464 18.181 ;
     RECT  31.2 17.077 31.224 18.181 ;
     RECT  52.8 17.219 52.824 18.181 ;
     RECT  72.6 15.251 73.32 18.181 ;
     RECT  16.176 18.181 17.592 18.227 ;
     RECT  23.52 18.181 25.464 18.227 ;
     RECT  33.456 17.941 35.496 18.227 ;
     RECT  45.6 17.845 46.248 18.229 ;
     RECT  82.272 17.893 84.792 18.229 ;
     RECT  13.2 17.605 13.752 18.275 ;
     RECT  48.672 17.989 51.312 18.323 ;
     RECT  61.248 18.133 63.768 18.323 ;
     RECT  21.792 16.501 21.816 18.419 ;
     RECT  29.28 17.605 30.024 18.419 ;
     RECT  47.328 18.421 47.352 18.563 ;
     RECT  44.976 18.229 46.248 18.565 ;
     RECT  66.384 17.651 68.04 18.565 ;
     RECT  54.336 17.843 58.104 18.611 ;
     RECT  88.8 17.605 92.088 18.659 ;
     RECT  6.096 18.181 6.12 18.709 ;
     RECT  13.2 18.275 13.656 18.709 ;
     RECT  65.184 17.651 65.4 18.709 ;
     RECT  9.792 17.605 10.68 18.755 ;
     RECT  31.2 18.181 31.416 18.757 ;
     RECT  59.568 17.843 60.216 18.757 ;
     RECT  61.248 18.323 62.112 18.757 ;
     RECT  78 17.891 79.752 18.805 ;
     RECT  12.432 18.709 13.656 18.851 ;
     RECT  16.992 18.227 17.592 18.851 ;
     RECT  24 18.227 25.464 18.851 ;
     RECT  75.168 17.989 75.864 18.851 ;
     RECT  52.56 18.181 52.824 18.899 ;
     RECT  95.76 17.797 96.024 18.947 ;
     RECT  29.4 18.419 30.024 18.949 ;
     RECT  31.2 18.757 31.944 18.949 ;
     RECT  29.4 18.949 31.944 18.995 ;
     RECT  50.16 18.323 51.312 19.187 ;
     RECT  54.336 18.611 54.6 19.187 ;
     RECT  82.224 18.229 84.792 19.235 ;
     RECT  93.408 17.267 94.728 19.235 ;
     RECT  18.6 16.883 18.912 19.285 ;
     RECT  19.92 16.885 20.52 19.285 ;
     RECT  5.616 18.709 6.12 19.427 ;
     RECT  25.44 18.851 25.464 19.571 ;
     RECT  6.096 19.427 6.12 19.621 ;
     RECT  7.8 14.867 8.112 19.621 ;
     RECT  9.792 18.755 9.816 19.621 ;
     RECT  44.976 18.565 46.392 19.669 ;
     RECT  13.2 18.851 13.656 19.765 ;
     RECT  72.6 18.181 73.848 19.811 ;
     RECT  77.904 18.805 79.752 19.811 ;
     RECT  82.272 19.235 84.792 19.811 ;
     RECT  93.648 19.235 94.728 19.811 ;
     RECT  13.2 19.765 14.472 19.813 ;
     RECT  87.12 17.939 87.144 19.909 ;
     RECT  92.064 18.659 92.088 19.909 ;
     RECT  15.696 19.477 15.72 20.051 ;
     RECT  36.864 19.573 36.888 20.053 ;
     RECT  93.648 19.811 94.632 20.099 ;
     RECT  75.168 18.851 75.768 20.101 ;
     RECT  88.8 18.659 90.6 20.101 ;
     RECT  44.688 19.669 46.392 20.149 ;
     RECT  87.072 19.909 87.144 20.149 ;
     RECT  29.4 18.995 31.416 20.195 ;
     RECT  88.8 20.101 90.792 20.243 ;
     RECT  77.904 19.811 78.936 20.291 ;
     RECT  21.648 18.805 21.672 20.339 ;
     RECT  31.2 20.195 31.416 20.341 ;
     RECT  52.8 18.899 52.824 20.341 ;
     RECT  72.6 19.811 72.912 20.389 ;
     RECT  44.688 20.149 46.68 20.435 ;
     RECT  86.544 20.149 87.144 20.485 ;
     RECT  22.656 19.861 22.68 20.533 ;
     RECT  9.744 19.621 9.816 20.579 ;
     RECT  16.992 18.851 17.496 20.579 ;
     RECT  91.776 19.909 92.088 20.579 ;
     RECT  6.096 19.621 8.112 20.627 ;
     RECT  22.656 20.533 22.728 20.675 ;
     RECT  63.504 18.323 63.768 20.725 ;
     RECT  65.088 18.709 65.4 20.725 ;
     RECT  66.384 18.565 68.568 20.725 ;
     RECT  70.368 16.931 71.352 20.725 ;
     RECT  9.744 20.579 9.768 20.819 ;
     RECT  24 18.851 24.312 20.869 ;
     RECT  86.544 20.485 87.24 20.869 ;
     RECT  47.664 20.149 47.688 20.965 ;
     RECT  48.672 18.323 48.696 20.965 ;
     RECT  88.8 20.243 90.6 20.965 ;
     RECT  97.584 17.029 99.912 20.965 ;
     RECT  33.456 18.227 35.304 21.061 ;
     RECT  36.48 20.053 36.888 21.061 ;
     RECT  94.08 20.099 94.632 21.061 ;
     RECT  96 18.947 96.024 21.061 ;
     RECT  97.2 20.965 99.912 21.061 ;
     RECT  52.8 20.341 53.112 21.107 ;
     RECT  54.48 19.187 54.6 21.107 ;
     RECT  47.664 20.965 48.696 21.155 ;
     RECT  66.384 20.725 71.352 21.155 ;
     RECT  83.28 19.811 84.792 21.155 ;
     RECT  94.08 21.061 94.728 21.155 ;
     RECT  59.568 18.757 62.112 21.157 ;
     RECT  63.504 20.725 65.4 21.157 ;
     RECT  94.2 21.155 94.728 21.203 ;
     RECT  66.384 21.155 71.16 21.251 ;
     RECT  69.456 21.251 71.16 21.299 ;
     RECT  72.48 20.389 72.912 21.299 ;
     RECT  88.656 20.965 90.6 21.491 ;
     RECT  13.056 19.813 14.472 21.637 ;
     RECT  70.848 21.299 71.16 21.683 ;
     RECT  59.568 21.157 65.4 21.779 ;
     RECT  70.848 21.683 70.92 21.779 ;
     RECT  72.6 21.299 72.912 21.781 ;
     RECT  26.112 21.109 26.136 21.827 ;
     RECT  18.6 19.285 20.52 21.925 ;
     RECT  21.648 21.733 21.672 21.925 ;
     RECT  86.544 20.869 87.336 21.925 ;
     RECT  88.656 21.491 90.024 21.925 ;
     RECT  31.2 20.341 31.56 21.973 ;
     RECT  86.544 21.925 90.024 22.019 ;
     RECT  33.456 21.061 36.888 22.021 ;
     RECT  18 21.925 21.672 22.069 ;
     RECT  22.656 20.675 22.68 22.069 ;
     RECT  39.024 15.491 43.176 22.069 ;
     RECT  44.16 21.013 44.184 22.069 ;
     RECT  29.4 20.195 30.024 22.165 ;
     RECT  74.64 20.101 75.768 22.165 ;
     RECT  83.4 21.155 84.792 22.165 ;
     RECT  24 20.869 24.984 22.211 ;
     RECT  18 22.069 22.68 22.259 ;
     RECT  31.2 21.973 31.608 22.259 ;
     RECT  48.192 21.155 48.696 22.259 ;
     RECT  96 21.061 99.912 22.355 ;
     RECT  87.072 22.019 89.688 22.451 ;
     RECT  16.992 20.579 17.016 22.453 ;
     RECT  18.6 22.259 20.712 22.499 ;
     RECT  94.2 21.203 94.632 22.501 ;
     RECT  27.36 19.765 27.96 22.739 ;
     RECT  72.6 21.781 73.512 22.741 ;
     RECT  92.064 20.579 92.088 22.741 ;
     RECT  94.08 22.501 94.632 22.741 ;
     RECT  72.48 22.741 73.512 22.787 ;
     RECT  6.096 20.627 6.12 22.789 ;
     RECT  22.32 22.259 22.68 22.789 ;
     RECT  27.408 22.739 27.96 22.837 ;
     RECT  13.056 21.637 15.336 22.883 ;
     RECT  33.36 22.021 36.888 22.883 ;
     RECT  59.568 21.779 62.112 22.883 ;
     RECT  7.8 20.627 8.112 22.885 ;
     RECT  6.096 22.789 6.6 22.931 ;
     RECT  18.6 22.499 20.52 22.979 ;
     RECT  69.456 21.299 69.48 22.981 ;
     RECT  7.584 22.885 8.112 23.075 ;
     RECT  10.224 22.741 10.248 23.077 ;
     RECT  54.576 21.107 54.6 23.125 ;
     RECT  68.928 22.981 69.48 23.173 ;
     RECT  70.848 21.779 70.872 23.173 ;
     RECT  74.64 22.165 76.344 23.173 ;
     RECT  78 20.291 78.936 23.173 ;
     RECT  72.48 22.787 73.032 23.219 ;
     RECT  7.68 23.075 8.112 23.269 ;
     RECT  31.2 22.259 31.56 23.269 ;
     RECT  83.4 22.165 84.984 23.315 ;
     RECT  27.408 22.837 28.056 23.317 ;
     RECT  29.088 22.165 30.024 23.317 ;
     RECT  72.48 23.219 72.912 23.317 ;
     RECT  7.68 23.269 8.376 23.363 ;
     RECT  94.08 22.741 94.776 23.365 ;
     RECT  24 22.211 24.312 23.557 ;
     RECT  25.92 23.173 25.944 23.557 ;
     RECT  92.064 22.741 92.616 23.603 ;
     RECT  24 23.557 25.944 23.605 ;
     RECT  88.176 22.451 89.688 23.701 ;
     RECT  90.864 23.365 90.888 23.701 ;
     RECT  48.672 22.259 48.696 23.845 ;
     RECT  13.056 22.883 14.472 23.891 ;
     RECT  55.584 18.611 58.104 23.893 ;
     RECT  59.568 22.883 60.216 23.893 ;
     RECT  61.44 22.883 62.112 23.893 ;
     RECT  63.12 21.779 65.4 23.893 ;
     RECT  83.4 23.315 84.792 23.893 ;
     RECT  93.744 23.365 94.776 23.893 ;
     RECT  96 22.355 96.408 23.893 ;
     RECT  54.528 23.125 54.6 23.939 ;
     RECT  66.384 21.251 67.944 23.987 ;
     RECT  68.928 23.173 70.872 23.987 ;
     RECT  72.384 23.317 72.912 23.987 ;
     RECT  7.8 23.363 8.376 24.035 ;
     RECT  23.904 23.605 25.944 24.083 ;
     RECT  66.624 23.987 67.944 24.131 ;
     RECT  39.024 22.069 44.184 24.179 ;
     RECT  87.072 22.451 87.192 24.229 ;
     RECT  48.672 23.845 49.032 24.325 ;
     RECT  88.176 23.701 90.888 24.421 ;
     RECT  92.064 23.603 92.28 24.421 ;
     RECT  54.528 23.939 54.552 24.467 ;
     RECT  31.2 23.269 32.472 24.469 ;
     RECT  33.456 22.883 36.888 24.469 ;
     RECT  27.408 23.317 30.024 24.515 ;
     RECT  16.944 22.453 17.016 24.613 ;
     RECT  22.32 22.789 22.776 24.659 ;
     RECT  66.624 24.131 67.704 24.659 ;
     RECT  86.832 24.229 87.192 24.853 ;
     RECT  23.904 24.083 25.08 24.949 ;
     RECT  45.6 20.435 46.68 24.949 ;
     RECT  6.096 22.931 6.12 25.045 ;
     RECT  7.8 24.035 8.112 25.045 ;
     RECT  74.64 23.173 78.936 25.045 ;
     RECT  88.176 24.421 92.28 25.045 ;
     RECT  93.744 23.893 96.408 25.045 ;
     RECT  88.176 25.045 96.408 25.091 ;
     RECT  23.856 24.949 25.08 25.093 ;
     RECT  11.952 20.965 11.976 25.139 ;
     RECT  16.8 24.613 17.016 25.141 ;
     RECT  86.64 24.853 87.192 25.187 ;
     RECT  86.832 25.187 87.192 25.235 ;
     RECT  87.072 25.235 87.192 25.333 ;
     RECT  88.176 25.091 90.072 25.333 ;
     RECT  31.2 24.469 36.888 25.427 ;
     RECT  16.8 25.141 17.064 25.475 ;
     RECT  82.272 19.811 82.296 25.475 ;
     RECT  44.976 24.949 46.68 25.525 ;
     RECT  83.28 23.893 84.792 25.573 ;
     RECT  37.872 25.525 37.896 25.621 ;
     RECT  39.024 24.179 43.464 25.621 ;
     RECT  55.584 23.893 60.216 25.621 ;
     RECT  83.28 25.573 85.128 25.621 ;
     RECT  54.912 25.621 60.216 25.669 ;
     RECT  61.44 23.893 65.4 25.669 ;
     RECT  54.912 25.669 65.4 25.715 ;
     RECT  91.584 25.091 96.408 25.715 ;
     RECT  66.624 24.659 67.608 25.717 ;
     RECT  68.928 23.987 70.152 25.717 ;
     RECT  50.592 19.187 51.312 25.765 ;
     RECT  52.8 21.107 52.824 25.765 ;
     RECT  31.2 25.427 35.304 25.811 ;
     RECT  93.744 25.715 96.408 25.813 ;
     RECT  97.44 22.355 99.912 25.813 ;
     RECT  18.6 22.979 18.912 25.861 ;
     RECT  54.912 25.715 58.392 25.955 ;
     RECT  59.568 25.715 65.4 25.955 ;
     RECT  44.976 25.525 46.728 26.005 ;
     RECT  10.224 23.077 10.872 26.051 ;
     RECT  33.456 25.811 35.304 26.051 ;
     RECT  10.224 26.051 10.248 26.101 ;
     RECT  74.592 25.045 78.936 26.101 ;
     RECT  74.544 26.101 78.936 26.147 ;
     RECT  50.592 25.765 52.824 26.243 ;
     RECT  36.576 25.427 36.888 26.291 ;
     RECT  91.584 25.715 92.616 26.291 ;
     RECT  18.288 25.861 18.912 26.627 ;
     RECT  66.624 25.717 70.152 26.627 ;
     RECT  87.072 25.333 90.072 26.627 ;
     RECT  13.2 23.891 14.472 26.629 ;
     RECT  22.32 24.659 22.68 26.629 ;
     RECT  23.856 25.093 25.656 26.629 ;
     RECT  63.12 25.955 65.4 26.677 ;
     RECT  66.624 26.627 69.192 26.677 ;
     RECT  9.36 26.101 10.248 26.771 ;
     RECT  22.32 26.629 25.656 26.771 ;
     RECT  48.672 24.325 49.32 26.771 ;
     RECT  13.104 26.629 14.472 26.773 ;
     RECT  22.32 26.771 25.08 26.819 ;
     RECT  82.8 25.621 85.128 26.819 ;
     RECT  93.744 25.813 99.912 26.819 ;
     RECT  27.408 24.515 28.056 26.869 ;
     RECT  23.616 26.819 25.08 26.915 ;
     RECT  63.12 26.677 69.192 27.107 ;
     RECT  74.544 26.147 78.408 27.107 ;
     RECT  95.904 26.819 99.912 27.107 ;
     RECT  72.6 23.987 72.912 27.109 ;
     RECT  82.8 26.819 84.936 27.299 ;
     RECT  12.528 26.773 14.472 27.301 ;
     RECT  16.944 25.475 17.064 27.347 ;
     RECT  23.616 26.915 24.312 27.347 ;
     RECT  72.6 27.109 73.416 27.347 ;
     RECT  80.016 27.205 80.04 27.347 ;
     RECT  37.872 25.621 43.464 27.445 ;
     RECT  44.784 26.005 46.728 27.445 ;
     RECT  12.528 27.301 14.808 27.541 ;
     RECT  36.576 26.291 36.84 27.589 ;
     RECT  37.872 27.445 46.728 27.589 ;
     RECT  82.8 27.299 84.792 27.635 ;
     RECT  74.592 27.107 78.408 27.637 ;
     RECT  10.224 26.771 10.248 27.731 ;
     RECT  26.736 26.869 28.056 27.731 ;
     RECT  36.576 27.589 46.728 27.779 ;
     RECT  31.2 25.811 32.472 27.781 ;
     RECT  33.456 26.051 33.48 27.781 ;
     RECT  28.032 27.731 28.056 27.827 ;
     RECT  91.584 26.291 92.28 27.829 ;
     RECT  93.744 26.819 94.68 27.829 ;
     RECT  74.592 27.637 78.504 27.875 ;
     RECT  64.368 27.107 69.192 27.923 ;
     RECT  65.088 27.923 69.192 27.971 ;
     RECT  22.32 26.819 22.344 28.165 ;
     RECT  23.856 27.347 24.312 28.213 ;
     RECT  83.04 27.635 84.792 28.259 ;
     RECT  10.8 28.165 10.824 28.307 ;
     RECT  78 27.875 78.504 28.355 ;
     RECT  12.144 27.541 14.808 28.451 ;
     RECT  65.088 27.971 67.608 28.451 ;
     RECT  91.584 27.829 94.68 28.451 ;
     RECT  98.16 27.107 99.912 28.451 ;
     RECT  16.992 27.347 17.064 28.453 ;
     RECT  29.4 24.515 30.024 28.453 ;
     RECT  72.6 27.347 73.128 28.499 ;
     RECT  63.12 27.107 63.144 28.501 ;
     RECT  6.096 25.045 8.112 28.595 ;
     RECT  59.568 25.955 62.112 28.643 ;
     RECT  83.28 28.259 84.792 28.693 ;
     RECT  26.736 27.731 26.76 28.739 ;
     RECT  67.2 28.451 67.608 28.787 ;
     RECT  74.592 27.875 76.632 28.787 ;
     RECT  83.28 28.693 84.84 28.835 ;
     RECT  87.072 26.627 89.688 28.931 ;
     RECT  59.616 28.643 62.112 28.933 ;
     RECT  63.12 28.501 63.24 28.933 ;
     RECT  65.088 28.451 66.12 28.979 ;
     RECT  65.088 28.979 65.544 28.981 ;
     RECT  54.912 25.955 58.296 29.029 ;
     RECT  22.224 28.165 22.344 29.075 ;
     RECT  59.616 28.933 63.24 29.075 ;
     RECT  50.592 26.243 52.056 29.125 ;
     RECT  53.568 28.213 53.592 29.125 ;
     RECT  95.904 27.107 96.792 29.125 ;
     RECT  68.592 27.971 69.192 29.219 ;
     RECT  68.592 29.219 69.144 29.221 ;
     RECT  74.592 28.787 75.24 29.315 ;
     RECT  22.32 29.075 22.344 29.317 ;
     RECT  37.872 27.779 46.728 29.365 ;
     RECT  54.912 29.029 58.632 29.459 ;
     RECT  50.592 29.125 53.592 29.461 ;
     RECT  63.216 29.075 63.24 29.507 ;
     RECT  95.904 29.125 96.936 29.507 ;
     RECT  78 28.355 78.408 29.555 ;
     RECT  18.6 26.627 18.912 29.557 ;
     RECT  22.32 29.317 22.824 29.603 ;
     RECT  49.968 29.461 53.592 29.651 ;
     RECT  29.4 28.453 30.216 29.653 ;
     RECT  22.32 29.603 22.344 29.699 ;
     RECT  96.768 29.507 96.936 29.699 ;
     RECT  16.56 28.453 17.064 29.701 ;
     RECT  12.912 28.451 14.808 29.843 ;
     RECT  53.568 29.651 53.592 29.843 ;
     RECT  55.248 29.459 58.632 29.843 ;
     RECT  23.856 28.213 24.6 30.035 ;
     RECT  34.512 26.051 35.304 30.181 ;
     RECT  36.576 27.779 36.84 30.181 ;
     RECT  6.864 28.595 8.112 30.275 ;
     RECT  23.856 30.035 24.552 30.275 ;
     RECT  37.872 29.365 46.968 30.275 ;
     RECT  68.544 29.221 69.144 30.275 ;
     RECT  92.976 28.451 94.68 30.275 ;
     RECT  91.584 28.451 91.896 30.371 ;
     RECT  96.768 29.699 96.792 30.371 ;
     RECT  78 29.555 78.312 30.373 ;
     RECT  55.248 29.843 58.296 30.419 ;
     RECT  74.592 29.315 74.952 30.419 ;
     RECT  55.248 30.419 57.768 30.469 ;
     RECT  74.592 30.419 74.856 30.563 ;
     RECT  15.936 29.701 17.064 30.611 ;
     RECT  23.856 30.275 24.312 30.611 ;
     RECT  64.704 28.981 65.544 30.611 ;
     RECT  94.2 30.275 94.68 30.611 ;
     RECT  18.48 29.557 18.912 30.613 ;
     RECT  4.944 25.237 4.968 30.709 ;
     RECT  14.784 29.843 14.808 30.709 ;
     RECT  54.624 30.469 57.768 30.709 ;
     RECT  67.2 28.787 67.512 30.709 ;
     RECT  68.544 30.275 68.952 30.709 ;
     RECT  91.872 30.371 91.896 30.709 ;
     RECT  92.976 30.275 93.192 30.709 ;
     RECT  74.736 30.563 74.856 30.755 ;
     RECT  19.92 22.979 20.52 30.803 ;
     RECT  49.968 29.651 52.44 30.805 ;
     RECT  87.744 28.931 89.688 30.805 ;
     RECT  63.504 29.653 63.528 30.851 ;
     RECT  4.944 30.709 5.64 30.949 ;
     RECT  4.944 30.949 6.504 30.995 ;
     RECT  87.744 30.805 90.072 31.043 ;
     RECT  74.832 30.755 74.856 31.091 ;
     RECT  65.28 30.611 65.544 31.139 ;
     RECT  77.76 30.373 78.312 31.139 ;
     RECT  91.872 30.709 93.192 31.139 ;
     RECT  38.016 30.275 46.968 31.141 ;
     RECT  48.672 26.771 48.696 31.141 ;
     RECT  16.56 30.611 17.064 31.187 ;
     RECT  38.016 31.141 48.696 31.187 ;
     RECT  16.752 31.187 17.064 31.235 ;
     RECT  25.824 31.189 25.848 31.237 ;
     RECT  28.656 29.653 30.216 31.237 ;
     RECT  31.2 27.781 33.48 31.237 ;
     RECT  25.584 31.237 25.848 31.331 ;
     RECT  34.512 30.181 36.84 31.331 ;
     RECT  80.4 29.029 80.424 31.333 ;
     RECT  28.656 31.237 33.48 31.379 ;
     RECT  91.872 31.139 93 31.379 ;
     RECT  67.2 30.709 68.952 31.523 ;
     RECT  49.968 30.805 53.16 31.525 ;
     RECT  54.48 30.709 57.768 31.525 ;
     RECT  78 31.139 78.312 31.621 ;
     RECT  38.016 31.187 48.216 31.667 ;
     RECT  80.016 31.333 80.424 31.667 ;
     RECT  78 31.621 78.408 31.765 ;
     RECT  38.016 31.667 48.024 31.811 ;
     RECT  68.592 31.523 68.952 31.859 ;
     RECT  18.432 30.613 18.912 31.861 ;
     RECT  19.92 30.803 19.944 31.861 ;
     RECT  21.744 31.381 21.768 31.861 ;
     RECT  87.744 31.043 87.768 31.861 ;
     RECT  96.864 31.285 96.888 31.861 ;
     RECT  14.784 30.709 15.432 31.955 ;
     RECT  29.4 31.379 33.48 31.955 ;
     RECT  38.016 31.811 47.928 31.955 ;
     RECT  49.968 31.525 57.768 31.955 ;
     RECT  24 30.611 24.312 31.957 ;
     RECT  5.616 30.995 6.504 32.003 ;
     RECT  53.952 31.955 57.768 32.003 ;
     RECT  23.904 31.957 24.312 32.005 ;
     RECT  25.584 31.331 25.704 32.005 ;
     RECT  27.456 31.669 27.48 32.101 ;
     RECT  11.568 31.093 11.592 32.195 ;
     RECT  18.432 31.861 21.768 32.195 ;
     RECT  39.888 31.955 47.928 32.195 ;
     RECT  80.016 31.667 80.04 32.195 ;
     RECT  23.904 32.005 25.704 32.243 ;
     RECT  44.784 32.195 47.928 32.243 ;
     RECT  27.264 32.101 27.48 32.245 ;
     RECT  92.976 31.379 93 32.341 ;
     RECT  94.2 30.611 94.512 32.341 ;
     RECT  39.888 32.195 43.368 32.483 ;
     RECT  26.88 32.245 27.48 32.531 ;
     RECT  29.4 31.955 32.856 32.579 ;
     RECT  47.904 32.243 47.928 32.579 ;
     RECT  18.432 32.195 20.856 32.723 ;
     RECT  12.912 29.843 13.656 32.725 ;
     RECT  16.992 31.235 17.064 32.725 ;
     RECT  18.432 32.723 18.912 32.725 ;
     RECT  83.28 28.835 84.792 32.773 ;
     RECT  31.2 32.579 32.856 32.819 ;
     RECT  53.952 32.003 57.624 32.819 ;
     RECT  69.072 32.341 69.096 32.869 ;
     RECT  68.976 32.869 69.096 32.915 ;
     RECT  83.28 32.773 84.936 32.915 ;
     RECT  76.464 28.787 76.632 32.963 ;
     RECT  87.216 31.861 87.768 32.963 ;
     RECT  78 31.765 78.84 33.011 ;
     RECT  16.992 32.725 18.912 33.013 ;
     RECT  78 33.011 78.408 33.059 ;
     RECT  96.864 31.861 96.936 33.059 ;
     RECT  40.08 32.483 43.368 33.107 ;
     RECT  59.616 29.075 62.112 33.107 ;
     RECT  65.28 31.139 65.4 33.107 ;
     RECT  76.608 32.963 76.632 33.107 ;
     RECT  91.872 31.379 91.896 33.107 ;
     RECT  98.352 28.451 99.912 33.107 ;
     RECT  59.616 33.107 59.64 33.155 ;
     RECT  92.976 32.341 94.512 33.203 ;
     RECT  53.952 32.819 57.576 33.251 ;
     RECT  49.968 31.955 52.488 33.253 ;
     RECT  19.92 32.723 20.856 33.299 ;
     RECT  88.8 31.043 90.072 33.299 ;
     RECT  93.792 33.203 94.512 33.299 ;
     RECT  60.624 33.107 62.112 33.347 ;
     RECT  53.952 33.251 56.808 33.443 ;
     RECT  76.896 33.109 76.92 33.491 ;
     RECT  12.528 32.725 13.656 33.541 ;
     RECT  22.752 32.677 22.776 33.541 ;
     RECT  24 32.243 25.368 33.541 ;
     RECT  49.056 33.253 52.488 33.635 ;
     RECT  65.376 33.107 65.4 33.637 ;
     RECT  83.28 32.915 84.792 33.683 ;
     RECT  29.4 32.579 30.024 33.685 ;
     RECT  49.104 33.635 52.488 33.779 ;
     RECT  67.2 31.523 67.608 33.779 ;
     RECT  68.976 32.915 69 33.827 ;
     RECT  81.456 33.061 81.48 33.827 ;
     RECT  12.48 33.541 13.656 33.875 ;
     RECT  40.08 33.107 43.224 33.923 ;
     RECT  26.976 32.531 27.48 33.971 ;
     RECT  88.8 33.299 89.688 33.971 ;
     RECT  31.632 32.819 32.856 34.019 ;
     RECT  44.784 32.243 46.008 34.069 ;
     RECT  53.952 33.443 56.712 34.115 ;
     RECT  52.464 33.779 52.488 34.163 ;
     RECT  53.952 34.115 55.32 34.165 ;
     RECT  65.376 33.637 65.88 34.355 ;
     RECT  14.88 31.955 15.432 34.451 ;
     RECT  29.4 33.685 30.264 34.597 ;
     RECT  16.848 33.013 18.912 34.693 ;
     RECT  19.92 33.299 19.944 34.693 ;
     RECT  40.08 33.923 43.176 34.739 ;
     RECT  56.4 34.115 56.712 34.741 ;
     RECT  36.576 31.331 36.84 34.787 ;
     RECT  53.808 34.165 55.32 34.787 ;
     RECT  32.832 34.019 32.856 34.835 ;
     RECT  60.624 33.347 60.696 34.835 ;
     RECT  95.76 33.925 95.784 34.835 ;
     RECT  27.456 33.971 27.48 34.931 ;
     RECT  60.624 34.835 60.648 34.931 ;
     RECT  6.48 32.003 6.504 34.979 ;
     RECT  36.816 34.787 36.84 34.979 ;
     RECT  22.752 33.541 25.368 35.171 ;
     RECT  28.512 34.597 30.264 35.171 ;
     RECT  56.4 34.741 56.808 35.269 ;
     RECT  58.032 34.741 58.056 35.269 ;
     RECT  44.784 34.069 46.776 35.315 ;
     RECT  11.136 34.117 11.16 35.363 ;
     RECT  12.48 33.875 13.608 35.363 ;
     RECT  28.512 35.171 29.832 35.363 ;
     RECT  49.104 33.779 51.312 35.363 ;
     RECT  87.744 32.963 87.768 35.363 ;
     RECT  12.48 35.363 13.512 35.459 ;
     RECT  25.344 35.171 25.368 35.459 ;
     RECT  88.8 33.971 89.304 35.507 ;
     RECT  12.528 35.459 13.512 35.747 ;
     RECT  16.848 34.693 19.944 35.747 ;
     RECT  31.632 34.019 31.656 35.747 ;
     RECT  49.104 35.363 49.128 35.747 ;
     RECT  55.248 34.787 55.32 35.747 ;
     RECT  34.512 31.331 35.208 35.845 ;
     RECT  44.784 35.315 45.912 35.891 ;
     RECT  56.4 35.269 58.056 35.939 ;
     RECT  22.752 35.171 24.312 35.989 ;
     RECT  9.792 34.165 9.816 36.229 ;
     RECT  40.2 34.739 43.176 36.229 ;
     RECT  29.4 35.363 29.832 36.275 ;
     RECT  50.496 35.363 51.312 36.275 ;
     RECT  96.864 33.059 96.888 36.421 ;
     RECT  65.856 34.355 65.88 36.515 ;
     RECT  55.296 35.747 55.32 36.563 ;
     RECT  22.32 35.989 24.312 36.803 ;
     RECT  26.784 36.757 26.808 36.899 ;
     RECT  16.848 35.747 18.912 36.901 ;
     RECT  58.416 36.085 58.44 36.947 ;
     RECT  9.12 36.229 9.816 37.091 ;
     RECT  34.176 35.845 35.208 37.091 ;
     RECT  48.144 36.421 48.168 37.091 ;
     RECT  53.808 34.787 53.976 37.189 ;
     RECT  96.864 36.421 97.368 37.573 ;
     RECT  98.352 33.107 98.376 37.573 ;
     RECT  16.56 36.901 18.912 37.619 ;
     RECT  9.792 37.091 9.816 37.859 ;
     RECT  38.016 31.955 38.136 37.861 ;
     RECT  32.784 37.093 32.808 37.957 ;
     RECT  34.176 37.091 35.112 37.957 ;
     RECT  32.784 37.957 35.112 38.003 ;
     RECT  16.56 37.619 17.064 38.099 ;
     RECT  21.792 37.285 21.816 38.099 ;
     RECT  31.344 36.469 31.368 38.099 ;
     RECT  38.016 37.861 38.76 38.149 ;
     RECT  17.04 38.099 17.064 38.195 ;
     RECT  23.184 36.803 24.312 38.243 ;
     RECT  44.544 38.149 44.568 38.245 ;
     RECT  45.6 35.891 45.912 38.245 ;
     RECT  32.784 38.003 33.672 38.339 ;
     RECT  10.8 37.045 10.824 38.387 ;
     RECT  44.544 38.245 45.912 38.435 ;
     RECT  44.544 38.435 44.568 38.483 ;
     RECT  51 36.275 51.312 38.581 ;
     RECT  53.088 37.189 53.976 38.581 ;
     RECT  15.408 34.451 15.432 38.629 ;
     RECT  37.056 38.149 38.76 38.675 ;
     RECT  52.992 38.581 53.976 38.675 ;
     RECT  52.992 38.675 53.832 38.723 ;
     RECT  37.056 38.675 37.08 38.725 ;
     RECT  53.808 38.723 53.832 38.819 ;
     RECT  96.864 37.573 98.376 38.819 ;
     RECT  15.408 38.629 15.528 38.867 ;
     RECT  23.808 38.243 24.312 38.963 ;
     RECT  36.288 38.725 37.08 38.963 ;
     RECT  25.92 38.629 25.944 39.395 ;
     RECT  50.016 38.581 51.312 39.491 ;
     RECT  36.288 38.963 36.312 39.539 ;
     RECT  18.6 37.619 18.912 39.733 ;
     RECT  15.408 38.867 15.432 39.779 ;
     RECT  29.4 36.275 29.712 39.781 ;
     RECT  33.648 38.339 33.672 39.923 ;
     RECT  16.944 39.349 16.968 40.019 ;
     RECT  18.48 39.733 18.912 40.067 ;
     RECT  38.736 38.675 38.76 40.213 ;
     RECT  38.304 40.213 38.76 40.259 ;
     RECT  96.864 38.819 96.888 40.405 ;
     RECT  29.4 39.781 29.928 40.451 ;
     RECT  40.2 36.229 43.272 40.499 ;
     RECT  26.064 40.405 26.088 40.883 ;
     RECT  19.92 35.747 19.944 41.075 ;
     RECT  96.864 40.405 97.368 42.421 ;
     RECT  98.352 38.819 98.376 42.421 ;
     RECT  40.2 40.499 43.176 42.707 ;
     RECT  40.2 42.707 43.128 42.755 ;
     RECT  38.304 40.259 38.328 43.955 ;
     RECT  36.432 40.549 36.456 44.003 ;
     RECT  96.864 42.421 98.376 44.147 ;
     RECT  42.096 42.755 43.128 44.771 ;
     RECT  83.4 33.683 84.792 44.963 ;
     RECT  42.336 44.771 43.128 45.539 ;
     RECT  96.864 44.147 97.176 46.787 ;
     RECT  83.4 44.963 83.88 47.363 ;
     RECT  98.352 44.147 98.376 47.651 ;
     RECT  96.864 46.787 96.888 47.989 ;
     RECT  7.8 30.275 8.112 48.373 ;
     RECT  36.192 44.773 36.216 48.419 ;
     RECT  43.104 45.539 43.128 48.419 ;
     RECT  96.864 47.989 96.936 48.851 ;
     RECT  7.8 48.373 8.232 49.331 ;
     RECT  2.4 16.403 2.712 49.477 ;
     RECT  95.808 48.805 95.832 50.389 ;
     RECT  96.864 48.851 96.888 50.389 ;
     RECT  95.808 50.389 96.888 50.435 ;
     RECT  96.288 50.435 96.888 52.549 ;
     RECT  95.76 52.549 96.888 52.595 ;
     RECT  95.76 52.595 95.784 54.179 ;
     RECT  96.864 52.595 96.888 56.389 ;
     RECT  96.864 56.389 97.416 57.347 ;
     RECT  96.864 57.347 97.176 60.949 ;
     RECT  96.864 60.949 97.416 62.629 ;
     RECT  96.864 62.629 97.464 62.771 ;
     RECT  2.4 49.477 3.672 63.299 ;
     RECT  97.44 66.085 97.464 67.331 ;
     RECT  95.808 63.589 95.832 68.435 ;
     RECT  2.4 63.299 2.712 69.129 ;
     RECT  7.8 49.331 8.112 69.129 ;
     RECT  13.2 35.747 13.512 69.129 ;
     RECT  18.6 40.067 18.912 69.129 ;
     RECT  24 38.963 24.312 69.129 ;
     RECT  29.4 40.451 29.712 69.129 ;
     RECT  34.8 38.003 35.112 69.129 ;
     RECT  40.2 42.755 40.512 69.129 ;
     RECT  45.6 38.435 45.912 69.129 ;
     RECT  51 39.491 51.312 69.129 ;
     RECT  56.4 35.939 56.712 69.129 ;
     RECT  61.8 33.347 62.112 69.129 ;
     RECT  67.2 33.779 67.512 69.129 ;
     RECT  72.6 28.499 72.912 69.129 ;
     RECT  78 33.059 78.312 69.129 ;
     RECT  83.4 47.363 83.712 69.129 ;
     RECT  88.8 35.507 89.112 69.129 ;
     RECT  94.2 33.299 94.512 69.129 ;
     RECT  99.6 33.107 99.912 69.129 ;
     RECT  2.4 69.129 2.52 69.143 ;
     RECT  7.8 69.129 7.92 69.143 ;
     RECT  13.2 69.129 13.32 69.143 ;
     RECT  18.6 69.129 18.72 69.143 ;
     RECT  24 69.129 24.12 69.143 ;
     RECT  29.4 69.129 29.52 69.143 ;
     RECT  34.8 69.129 34.92 69.143 ;
     RECT  40.2 69.129 40.32 69.143 ;
     RECT  83.4 69.129 83.52 69.143 ;
     RECT  88.8 69.129 88.92 69.143 ;
     RECT  94.2 69.129 94.32 69.143 ;
     RECT  99.6 69.129 99.72 69.143 ;
  END
END ot_hgi_coll_fj_q2_r128
END LIBRARY
